# Generated by FakeRAM 2.0
VERSION 5.7 ;
BUSBITCHARS "[]" ;
PROPERTYDEFINITIONS
  MACRO width INTEGER ;
  MACRO depth INTEGER ;
  MACRO banks INTEGER ;
END PROPERTYDEFINITIONS
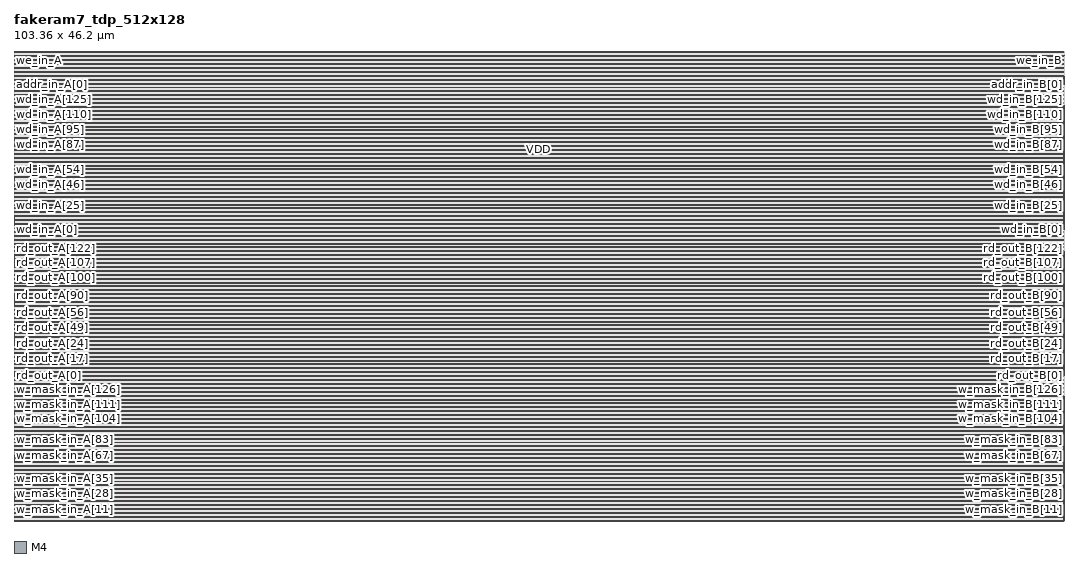
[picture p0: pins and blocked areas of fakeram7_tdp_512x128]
MACRO fakeram7_tdp_512x128
  PROPERTY width 128 ;
  PROPERTY depth 512 ;
  PROPERTY banks 4 ;
  FOREIGN fakeram7_tdp_512x128 0 0 ;
  SYMMETRY X Y ;
  SIZE 103.360 BY 46.200 ;
  CLASS BLOCK ;
  PIN w_mask_in_A[0]
    DIRECTION INPUT ;
    USE SIGNAL ;
    SHAPE ABUTMENT ;
    PORT
      LAYER M4 ;
      RECT 0.000 0.048 0.024 0.072 ;
    END
  END w_mask_in_A[0]
  PIN w_mask_in_B[0]
    DIRECTION INPUT ;
    USE SIGNAL ;
    SHAPE ABUTMENT ;
    PORT
      LAYER M4 ;
      RECT 103.336 0.048 103.360 0.072 ;
    END
  END w_mask_in_B[0]
  PIN w_mask_in_A[1]
    DIRECTION INPUT ;
    USE SIGNAL ;
    SHAPE ABUTMENT ;
    PORT
      LAYER M4 ;
      RECT 0.000 0.144 0.024 0.168 ;
    END
  END w_mask_in_A[1]
  PIN w_mask_in_B[1]
    DIRECTION INPUT ;
    USE SIGNAL ;
    SHAPE ABUTMENT ;
    PORT
      LAYER M4 ;
      RECT 103.336 0.144 103.360 0.168 ;
    END
  END w_mask_in_B[1]
  PIN w_mask_in_A[2]
    DIRECTION INPUT ;
    USE SIGNAL ;
    SHAPE ABUTMENT ;
    PORT
      LAYER M4 ;
      RECT 0.000 0.240 0.024 0.264 ;
    END
  END w_mask_in_A[2]
  PIN w_mask_in_B[2]
    DIRECTION INPUT ;
    USE SIGNAL ;
    SHAPE ABUTMENT ;
    PORT
      LAYER M4 ;
      RECT 103.336 0.240 103.360 0.264 ;
    END
  END w_mask_in_B[2]
  PIN w_mask_in_A[3]
    DIRECTION INPUT ;
    USE SIGNAL ;
    SHAPE ABUTMENT ;
    PORT
      LAYER M4 ;
      RECT 0.000 0.336 0.024 0.360 ;
    END
  END w_mask_in_A[3]
  PIN w_mask_in_B[3]
    DIRECTION INPUT ;
    USE SIGNAL ;
    SHAPE ABUTMENT ;
    PORT
      LAYER M4 ;
      RECT 103.336 0.336 103.360 0.360 ;
    END
  END w_mask_in_B[3]
  PIN w_mask_in_A[4]
    DIRECTION INPUT ;
    USE SIGNAL ;
    SHAPE ABUTMENT ;
    PORT
      LAYER M4 ;
      RECT 0.000 0.432 0.024 0.456 ;
    END
  END w_mask_in_A[4]
  PIN w_mask_in_B[4]
    DIRECTION INPUT ;
    USE SIGNAL ;
    SHAPE ABUTMENT ;
    PORT
      LAYER M4 ;
      RECT 103.336 0.432 103.360 0.456 ;
    END
  END w_mask_in_B[4]
  PIN w_mask_in_A[5]
    DIRECTION INPUT ;
    USE SIGNAL ;
    SHAPE ABUTMENT ;
    PORT
      LAYER M4 ;
      RECT 0.000 0.528 0.024 0.552 ;
    END
  END w_mask_in_A[5]
  PIN w_mask_in_B[5]
    DIRECTION INPUT ;
    USE SIGNAL ;
    SHAPE ABUTMENT ;
    PORT
      LAYER M4 ;
      RECT 103.336 0.528 103.360 0.552 ;
    END
  END w_mask_in_B[5]
  PIN w_mask_in_A[6]
    DIRECTION INPUT ;
    USE SIGNAL ;
    SHAPE ABUTMENT ;
    PORT
      LAYER M4 ;
      RECT 0.000 0.624 0.024 0.648 ;
    END
  END w_mask_in_A[6]
  PIN w_mask_in_B[6]
    DIRECTION INPUT ;
    USE SIGNAL ;
    SHAPE ABUTMENT ;
    PORT
      LAYER M4 ;
      RECT 103.336 0.624 103.360 0.648 ;
    END
  END w_mask_in_B[6]
  PIN w_mask_in_A[7]
    DIRECTION INPUT ;
    USE SIGNAL ;
    SHAPE ABUTMENT ;
    PORT
      LAYER M4 ;
      RECT 0.000 0.720 0.024 0.744 ;
    END
  END w_mask_in_A[7]
  PIN w_mask_in_B[7]
    DIRECTION INPUT ;
    USE SIGNAL ;
    SHAPE ABUTMENT ;
    PORT
      LAYER M4 ;
      RECT 103.336 0.720 103.360 0.744 ;
    END
  END w_mask_in_B[7]
  PIN w_mask_in_A[8]
    DIRECTION INPUT ;
    USE SIGNAL ;
    SHAPE ABUTMENT ;
    PORT
      LAYER M4 ;
      RECT 0.000 0.816 0.024 0.840 ;
    END
  END w_mask_in_A[8]
  PIN w_mask_in_B[8]
    DIRECTION INPUT ;
    USE SIGNAL ;
    SHAPE ABUTMENT ;
    PORT
      LAYER M4 ;
      RECT 103.336 0.816 103.360 0.840 ;
    END
  END w_mask_in_B[8]
  PIN w_mask_in_A[9]
    DIRECTION INPUT ;
    USE SIGNAL ;
    SHAPE ABUTMENT ;
    PORT
      LAYER M4 ;
      RECT 0.000 0.912 0.024 0.936 ;
    END
  END w_mask_in_A[9]
  PIN w_mask_in_B[9]
    DIRECTION INPUT ;
    USE SIGNAL ;
    SHAPE ABUTMENT ;
    PORT
      LAYER M4 ;
      RECT 103.336 0.912 103.360 0.936 ;
    END
  END w_mask_in_B[9]
  PIN w_mask_in_A[10]
    DIRECTION INPUT ;
    USE SIGNAL ;
    SHAPE ABUTMENT ;
    PORT
      LAYER M4 ;
      RECT 0.000 1.008 0.024 1.032 ;
    END
  END w_mask_in_A[10]
  PIN w_mask_in_B[10]
    DIRECTION INPUT ;
    USE SIGNAL ;
    SHAPE ABUTMENT ;
    PORT
      LAYER M4 ;
      RECT 103.336 1.008 103.360 1.032 ;
    END
  END w_mask_in_B[10]
  PIN w_mask_in_A[11]
    DIRECTION INPUT ;
    USE SIGNAL ;
    SHAPE ABUTMENT ;
    PORT
      LAYER M4 ;
      RECT 0.000 1.104 0.024 1.128 ;
    END
  END w_mask_in_A[11]
  PIN w_mask_in_B[11]
    DIRECTION INPUT ;
    USE SIGNAL ;
    SHAPE ABUTMENT ;
    PORT
      LAYER M4 ;
      RECT 103.336 1.104 103.360 1.128 ;
    END
  END w_mask_in_B[11]
  PIN w_mask_in_A[12]
    DIRECTION INPUT ;
    USE SIGNAL ;
    SHAPE ABUTMENT ;
    PORT
      LAYER M4 ;
      RECT 0.000 1.200 0.024 1.224 ;
    END
  END w_mask_in_A[12]
  PIN w_mask_in_B[12]
    DIRECTION INPUT ;
    USE SIGNAL ;
    SHAPE ABUTMENT ;
    PORT
      LAYER M4 ;
      RECT 103.336 1.200 103.360 1.224 ;
    END
  END w_mask_in_B[12]
  PIN w_mask_in_A[13]
    DIRECTION INPUT ;
    USE SIGNAL ;
    SHAPE ABUTMENT ;
    PORT
      LAYER M4 ;
      RECT 0.000 1.296 0.024 1.320 ;
    END
  END w_mask_in_A[13]
  PIN w_mask_in_B[13]
    DIRECTION INPUT ;
    USE SIGNAL ;
    SHAPE ABUTMENT ;
    PORT
      LAYER M4 ;
      RECT 103.336 1.296 103.360 1.320 ;
    END
  END w_mask_in_B[13]
  PIN w_mask_in_A[14]
    DIRECTION INPUT ;
    USE SIGNAL ;
    SHAPE ABUTMENT ;
    PORT
      LAYER M4 ;
      RECT 0.000 1.392 0.024 1.416 ;
    END
  END w_mask_in_A[14]
  PIN w_mask_in_B[14]
    DIRECTION INPUT ;
    USE SIGNAL ;
    SHAPE ABUTMENT ;
    PORT
      LAYER M4 ;
      RECT 103.336 1.392 103.360 1.416 ;
    END
  END w_mask_in_B[14]
  PIN w_mask_in_A[15]
    DIRECTION INPUT ;
    USE SIGNAL ;
    SHAPE ABUTMENT ;
    PORT
      LAYER M4 ;
      RECT 0.000 1.488 0.024 1.512 ;
    END
  END w_mask_in_A[15]
  PIN w_mask_in_B[15]
    DIRECTION INPUT ;
    USE SIGNAL ;
    SHAPE ABUTMENT ;
    PORT
      LAYER M4 ;
      RECT 103.336 1.488 103.360 1.512 ;
    END
  END w_mask_in_B[15]
  PIN w_mask_in_A[16]
    DIRECTION INPUT ;
    USE SIGNAL ;
    SHAPE ABUTMENT ;
    PORT
      LAYER M4 ;
      RECT 0.000 1.584 0.024 1.608 ;
    END
  END w_mask_in_A[16]
  PIN w_mask_in_B[16]
    DIRECTION INPUT ;
    USE SIGNAL ;
    SHAPE ABUTMENT ;
    PORT
      LAYER M4 ;
      RECT 103.336 1.584 103.360 1.608 ;
    END
  END w_mask_in_B[16]
  PIN w_mask_in_A[17]
    DIRECTION INPUT ;
    USE SIGNAL ;
    SHAPE ABUTMENT ;
    PORT
      LAYER M4 ;
      RECT 0.000 1.680 0.024 1.704 ;
    END
  END w_mask_in_A[17]
  PIN w_mask_in_B[17]
    DIRECTION INPUT ;
    USE SIGNAL ;
    SHAPE ABUTMENT ;
    PORT
      LAYER M4 ;
      RECT 103.336 1.680 103.360 1.704 ;
    END
  END w_mask_in_B[17]
  PIN w_mask_in_A[18]
    DIRECTION INPUT ;
    USE SIGNAL ;
    SHAPE ABUTMENT ;
    PORT
      LAYER M4 ;
      RECT 0.000 1.776 0.024 1.800 ;
    END
  END w_mask_in_A[18]
  PIN w_mask_in_B[18]
    DIRECTION INPUT ;
    USE SIGNAL ;
    SHAPE ABUTMENT ;
    PORT
      LAYER M4 ;
      RECT 103.336 1.776 103.360 1.800 ;
    END
  END w_mask_in_B[18]
  PIN w_mask_in_A[19]
    DIRECTION INPUT ;
    USE SIGNAL ;
    SHAPE ABUTMENT ;
    PORT
      LAYER M4 ;
      RECT 0.000 1.872 0.024 1.896 ;
    END
  END w_mask_in_A[19]
  PIN w_mask_in_B[19]
    DIRECTION INPUT ;
    USE SIGNAL ;
    SHAPE ABUTMENT ;
    PORT
      LAYER M4 ;
      RECT 103.336 1.872 103.360 1.896 ;
    END
  END w_mask_in_B[19]
  PIN w_mask_in_A[20]
    DIRECTION INPUT ;
    USE SIGNAL ;
    SHAPE ABUTMENT ;
    PORT
      LAYER M4 ;
      RECT 0.000 1.968 0.024 1.992 ;
    END
  END w_mask_in_A[20]
  PIN w_mask_in_B[20]
    DIRECTION INPUT ;
    USE SIGNAL ;
    SHAPE ABUTMENT ;
    PORT
      LAYER M4 ;
      RECT 103.336 1.968 103.360 1.992 ;
    END
  END w_mask_in_B[20]
  PIN w_mask_in_A[21]
    DIRECTION INPUT ;
    USE SIGNAL ;
    SHAPE ABUTMENT ;
    PORT
      LAYER M4 ;
      RECT 0.000 2.064 0.024 2.088 ;
    END
  END w_mask_in_A[21]
  PIN w_mask_in_B[21]
    DIRECTION INPUT ;
    USE SIGNAL ;
    SHAPE ABUTMENT ;
    PORT
      LAYER M4 ;
      RECT 103.336 2.064 103.360 2.088 ;
    END
  END w_mask_in_B[21]
  PIN w_mask_in_A[22]
    DIRECTION INPUT ;
    USE SIGNAL ;
    SHAPE ABUTMENT ;
    PORT
      LAYER M4 ;
      RECT 0.000 2.160 0.024 2.184 ;
    END
  END w_mask_in_A[22]
  PIN w_mask_in_B[22]
    DIRECTION INPUT ;
    USE SIGNAL ;
    SHAPE ABUTMENT ;
    PORT
      LAYER M4 ;
      RECT 103.336 2.160 103.360 2.184 ;
    END
  END w_mask_in_B[22]
  PIN w_mask_in_A[23]
    DIRECTION INPUT ;
    USE SIGNAL ;
    SHAPE ABUTMENT ;
    PORT
      LAYER M4 ;
      RECT 0.000 2.256 0.024 2.280 ;
    END
  END w_mask_in_A[23]
  PIN w_mask_in_B[23]
    DIRECTION INPUT ;
    USE SIGNAL ;
    SHAPE ABUTMENT ;
    PORT
      LAYER M4 ;
      RECT 103.336 2.256 103.360 2.280 ;
    END
  END w_mask_in_B[23]
  PIN w_mask_in_A[24]
    DIRECTION INPUT ;
    USE SIGNAL ;
    SHAPE ABUTMENT ;
    PORT
      LAYER M4 ;
      RECT 0.000 2.352 0.024 2.376 ;
    END
  END w_mask_in_A[24]
  PIN w_mask_in_B[24]
    DIRECTION INPUT ;
    USE SIGNAL ;
    SHAPE ABUTMENT ;
    PORT
      LAYER M4 ;
      RECT 103.336 2.352 103.360 2.376 ;
    END
  END w_mask_in_B[24]
  PIN w_mask_in_A[25]
    DIRECTION INPUT ;
    USE SIGNAL ;
    SHAPE ABUTMENT ;
    PORT
      LAYER M4 ;
      RECT 0.000 2.448 0.024 2.472 ;
    END
  END w_mask_in_A[25]
  PIN w_mask_in_B[25]
    DIRECTION INPUT ;
    USE SIGNAL ;
    SHAPE ABUTMENT ;
    PORT
      LAYER M4 ;
      RECT 103.336 2.448 103.360 2.472 ;
    END
  END w_mask_in_B[25]
  PIN w_mask_in_A[26]
    DIRECTION INPUT ;
    USE SIGNAL ;
    SHAPE ABUTMENT ;
    PORT
      LAYER M4 ;
      RECT 0.000 2.544 0.024 2.568 ;
    END
  END w_mask_in_A[26]
  PIN w_mask_in_B[26]
    DIRECTION INPUT ;
    USE SIGNAL ;
    SHAPE ABUTMENT ;
    PORT
      LAYER M4 ;
      RECT 103.336 2.544 103.360 2.568 ;
    END
  END w_mask_in_B[26]
  PIN w_mask_in_A[27]
    DIRECTION INPUT ;
    USE SIGNAL ;
    SHAPE ABUTMENT ;
    PORT
      LAYER M4 ;
      RECT 0.000 2.640 0.024 2.664 ;
    END
  END w_mask_in_A[27]
  PIN w_mask_in_B[27]
    DIRECTION INPUT ;
    USE SIGNAL ;
    SHAPE ABUTMENT ;
    PORT
      LAYER M4 ;
      RECT 103.336 2.640 103.360 2.664 ;
    END
  END w_mask_in_B[27]
  PIN w_mask_in_A[28]
    DIRECTION INPUT ;
    USE SIGNAL ;
    SHAPE ABUTMENT ;
    PORT
      LAYER M4 ;
      RECT 0.000 2.736 0.024 2.760 ;
    END
  END w_mask_in_A[28]
  PIN w_mask_in_B[28]
    DIRECTION INPUT ;
    USE SIGNAL ;
    SHAPE ABUTMENT ;
    PORT
      LAYER M4 ;
      RECT 103.336 2.736 103.360 2.760 ;
    END
  END w_mask_in_B[28]
  PIN w_mask_in_A[29]
    DIRECTION INPUT ;
    USE SIGNAL ;
    SHAPE ABUTMENT ;
    PORT
      LAYER M4 ;
      RECT 0.000 2.832 0.024 2.856 ;
    END
  END w_mask_in_A[29]
  PIN w_mask_in_B[29]
    DIRECTION INPUT ;
    USE SIGNAL ;
    SHAPE ABUTMENT ;
    PORT
      LAYER M4 ;
      RECT 103.336 2.832 103.360 2.856 ;
    END
  END w_mask_in_B[29]
  PIN w_mask_in_A[30]
    DIRECTION INPUT ;
    USE SIGNAL ;
    SHAPE ABUTMENT ;
    PORT
      LAYER M4 ;
      RECT 0.000 2.928 0.024 2.952 ;
    END
  END w_mask_in_A[30]
  PIN w_mask_in_B[30]
    DIRECTION INPUT ;
    USE SIGNAL ;
    SHAPE ABUTMENT ;
    PORT
      LAYER M4 ;
      RECT 103.336 2.928 103.360 2.952 ;
    END
  END w_mask_in_B[30]
  PIN w_mask_in_A[31]
    DIRECTION INPUT ;
    USE SIGNAL ;
    SHAPE ABUTMENT ;
    PORT
      LAYER M4 ;
      RECT 0.000 3.024 0.024 3.048 ;
    END
  END w_mask_in_A[31]
  PIN w_mask_in_B[31]
    DIRECTION INPUT ;
    USE SIGNAL ;
    SHAPE ABUTMENT ;
    PORT
      LAYER M4 ;
      RECT 103.336 3.024 103.360 3.048 ;
    END
  END w_mask_in_B[31]
  PIN w_mask_in_A[32]
    DIRECTION INPUT ;
    USE SIGNAL ;
    SHAPE ABUTMENT ;
    PORT
      LAYER M4 ;
      RECT 0.000 3.120 0.024 3.144 ;
    END
  END w_mask_in_A[32]
  PIN w_mask_in_B[32]
    DIRECTION INPUT ;
    USE SIGNAL ;
    SHAPE ABUTMENT ;
    PORT
      LAYER M4 ;
      RECT 103.336 3.120 103.360 3.144 ;
    END
  END w_mask_in_B[32]
  PIN w_mask_in_A[33]
    DIRECTION INPUT ;
    USE SIGNAL ;
    SHAPE ABUTMENT ;
    PORT
      LAYER M4 ;
      RECT 0.000 3.216 0.024 3.240 ;
    END
  END w_mask_in_A[33]
  PIN w_mask_in_B[33]
    DIRECTION INPUT ;
    USE SIGNAL ;
    SHAPE ABUTMENT ;
    PORT
      LAYER M4 ;
      RECT 103.336 3.216 103.360 3.240 ;
    END
  END w_mask_in_B[33]
  PIN w_mask_in_A[34]
    DIRECTION INPUT ;
    USE SIGNAL ;
    SHAPE ABUTMENT ;
    PORT
      LAYER M4 ;
      RECT 0.000 3.312 0.024 3.336 ;
    END
  END w_mask_in_A[34]
  PIN w_mask_in_B[34]
    DIRECTION INPUT ;
    USE SIGNAL ;
    SHAPE ABUTMENT ;
    PORT
      LAYER M4 ;
      RECT 103.336 3.312 103.360 3.336 ;
    END
  END w_mask_in_B[34]
  PIN w_mask_in_A[35]
    DIRECTION INPUT ;
    USE SIGNAL ;
    SHAPE ABUTMENT ;
    PORT
      LAYER M4 ;
      RECT 0.000 3.408 0.024 3.432 ;
    END
  END w_mask_in_A[35]
  PIN w_mask_in_B[35]
    DIRECTION INPUT ;
    USE SIGNAL ;
    SHAPE ABUTMENT ;
    PORT
      LAYER M4 ;
      RECT 103.336 3.408 103.360 3.432 ;
    END
  END w_mask_in_B[35]
  PIN w_mask_in_A[36]
    DIRECTION INPUT ;
    USE SIGNAL ;
    SHAPE ABUTMENT ;
    PORT
      LAYER M4 ;
      RECT 0.000 3.504 0.024 3.528 ;
    END
  END w_mask_in_A[36]
  PIN w_mask_in_B[36]
    DIRECTION INPUT ;
    USE SIGNAL ;
    SHAPE ABUTMENT ;
    PORT
      LAYER M4 ;
      RECT 103.336 3.504 103.360 3.528 ;
    END
  END w_mask_in_B[36]
  PIN w_mask_in_A[37]
    DIRECTION INPUT ;
    USE SIGNAL ;
    SHAPE ABUTMENT ;
    PORT
      LAYER M4 ;
      RECT 0.000 3.600 0.024 3.624 ;
    END
  END w_mask_in_A[37]
  PIN w_mask_in_B[37]
    DIRECTION INPUT ;
    USE SIGNAL ;
    SHAPE ABUTMENT ;
    PORT
      LAYER M4 ;
      RECT 103.336 3.600 103.360 3.624 ;
    END
  END w_mask_in_B[37]
  PIN w_mask_in_A[38]
    DIRECTION INPUT ;
    USE SIGNAL ;
    SHAPE ABUTMENT ;
    PORT
      LAYER M4 ;
      RECT 0.000 3.696 0.024 3.720 ;
    END
  END w_mask_in_A[38]
  PIN w_mask_in_B[38]
    DIRECTION INPUT ;
    USE SIGNAL ;
    SHAPE ABUTMENT ;
    PORT
      LAYER M4 ;
      RECT 103.336 3.696 103.360 3.720 ;
    END
  END w_mask_in_B[38]
  PIN w_mask_in_A[39]
    DIRECTION INPUT ;
    USE SIGNAL ;
    SHAPE ABUTMENT ;
    PORT
      LAYER M4 ;
      RECT 0.000 3.792 0.024 3.816 ;
    END
  END w_mask_in_A[39]
  PIN w_mask_in_B[39]
    DIRECTION INPUT ;
    USE SIGNAL ;
    SHAPE ABUTMENT ;
    PORT
      LAYER M4 ;
      RECT 103.336 3.792 103.360 3.816 ;
    END
  END w_mask_in_B[39]
  PIN w_mask_in_A[40]
    DIRECTION INPUT ;
    USE SIGNAL ;
    SHAPE ABUTMENT ;
    PORT
      LAYER M4 ;
      RECT 0.000 3.888 0.024 3.912 ;
    END
  END w_mask_in_A[40]
  PIN w_mask_in_B[40]
    DIRECTION INPUT ;
    USE SIGNAL ;
    SHAPE ABUTMENT ;
    PORT
      LAYER M4 ;
      RECT 103.336 3.888 103.360 3.912 ;
    END
  END w_mask_in_B[40]
  PIN w_mask_in_A[41]
    DIRECTION INPUT ;
    USE SIGNAL ;
    SHAPE ABUTMENT ;
    PORT
      LAYER M4 ;
      RECT 0.000 3.984 0.024 4.008 ;
    END
  END w_mask_in_A[41]
  PIN w_mask_in_B[41]
    DIRECTION INPUT ;
    USE SIGNAL ;
    SHAPE ABUTMENT ;
    PORT
      LAYER M4 ;
      RECT 103.336 3.984 103.360 4.008 ;
    END
  END w_mask_in_B[41]
  PIN w_mask_in_A[42]
    DIRECTION INPUT ;
    USE SIGNAL ;
    SHAPE ABUTMENT ;
    PORT
      LAYER M4 ;
      RECT 0.000 4.080 0.024 4.104 ;
    END
  END w_mask_in_A[42]
  PIN w_mask_in_B[42]
    DIRECTION INPUT ;
    USE SIGNAL ;
    SHAPE ABUTMENT ;
    PORT
      LAYER M4 ;
      RECT 103.336 4.080 103.360 4.104 ;
    END
  END w_mask_in_B[42]
  PIN w_mask_in_A[43]
    DIRECTION INPUT ;
    USE SIGNAL ;
    SHAPE ABUTMENT ;
    PORT
      LAYER M4 ;
      RECT 0.000 4.176 0.024 4.200 ;
    END
  END w_mask_in_A[43]
  PIN w_mask_in_B[43]
    DIRECTION INPUT ;
    USE SIGNAL ;
    SHAPE ABUTMENT ;
    PORT
      LAYER M4 ;
      RECT 103.336 4.176 103.360 4.200 ;
    END
  END w_mask_in_B[43]
  PIN w_mask_in_A[44]
    DIRECTION INPUT ;
    USE SIGNAL ;
    SHAPE ABUTMENT ;
    PORT
      LAYER M4 ;
      RECT 0.000 4.272 0.024 4.296 ;
    END
  END w_mask_in_A[44]
  PIN w_mask_in_B[44]
    DIRECTION INPUT ;
    USE SIGNAL ;
    SHAPE ABUTMENT ;
    PORT
      LAYER M4 ;
      RECT 103.336 4.272 103.360 4.296 ;
    END
  END w_mask_in_B[44]
  PIN w_mask_in_A[45]
    DIRECTION INPUT ;
    USE SIGNAL ;
    SHAPE ABUTMENT ;
    PORT
      LAYER M4 ;
      RECT 0.000 4.368 0.024 4.392 ;
    END
  END w_mask_in_A[45]
  PIN w_mask_in_B[45]
    DIRECTION INPUT ;
    USE SIGNAL ;
    SHAPE ABUTMENT ;
    PORT
      LAYER M4 ;
      RECT 103.336 4.368 103.360 4.392 ;
    END
  END w_mask_in_B[45]
  PIN w_mask_in_A[46]
    DIRECTION INPUT ;
    USE SIGNAL ;
    SHAPE ABUTMENT ;
    PORT
      LAYER M4 ;
      RECT 0.000 4.464 0.024 4.488 ;
    END
  END w_mask_in_A[46]
  PIN w_mask_in_B[46]
    DIRECTION INPUT ;
    USE SIGNAL ;
    SHAPE ABUTMENT ;
    PORT
      LAYER M4 ;
      RECT 103.336 4.464 103.360 4.488 ;
    END
  END w_mask_in_B[46]
  PIN w_mask_in_A[47]
    DIRECTION INPUT ;
    USE SIGNAL ;
    SHAPE ABUTMENT ;
    PORT
      LAYER M4 ;
      RECT 0.000 4.560 0.024 4.584 ;
    END
  END w_mask_in_A[47]
  PIN w_mask_in_B[47]
    DIRECTION INPUT ;
    USE SIGNAL ;
    SHAPE ABUTMENT ;
    PORT
      LAYER M4 ;
      RECT 103.336 4.560 103.360 4.584 ;
    END
  END w_mask_in_B[47]
  PIN w_mask_in_A[48]
    DIRECTION INPUT ;
    USE SIGNAL ;
    SHAPE ABUTMENT ;
    PORT
      LAYER M4 ;
      RECT 0.000 4.656 0.024 4.680 ;
    END
  END w_mask_in_A[48]
  PIN w_mask_in_B[48]
    DIRECTION INPUT ;
    USE SIGNAL ;
    SHAPE ABUTMENT ;
    PORT
      LAYER M4 ;
      RECT 103.336 4.656 103.360 4.680 ;
    END
  END w_mask_in_B[48]
  PIN w_mask_in_A[49]
    DIRECTION INPUT ;
    USE SIGNAL ;
    SHAPE ABUTMENT ;
    PORT
      LAYER M4 ;
      RECT 0.000 4.752 0.024 4.776 ;
    END
  END w_mask_in_A[49]
  PIN w_mask_in_B[49]
    DIRECTION INPUT ;
    USE SIGNAL ;
    SHAPE ABUTMENT ;
    PORT
      LAYER M4 ;
      RECT 103.336 4.752 103.360 4.776 ;
    END
  END w_mask_in_B[49]
  PIN w_mask_in_A[50]
    DIRECTION INPUT ;
    USE SIGNAL ;
    SHAPE ABUTMENT ;
    PORT
      LAYER M4 ;
      RECT 0.000 4.848 0.024 4.872 ;
    END
  END w_mask_in_A[50]
  PIN w_mask_in_B[50]
    DIRECTION INPUT ;
    USE SIGNAL ;
    SHAPE ABUTMENT ;
    PORT
      LAYER M4 ;
      RECT 103.336 4.848 103.360 4.872 ;
    END
  END w_mask_in_B[50]
  PIN w_mask_in_A[51]
    DIRECTION INPUT ;
    USE SIGNAL ;
    SHAPE ABUTMENT ;
    PORT
      LAYER M4 ;
      RECT 0.000 4.944 0.024 4.968 ;
    END
  END w_mask_in_A[51]
  PIN w_mask_in_B[51]
    DIRECTION INPUT ;
    USE SIGNAL ;
    SHAPE ABUTMENT ;
    PORT
      LAYER M4 ;
      RECT 103.336 4.944 103.360 4.968 ;
    END
  END w_mask_in_B[51]
  PIN w_mask_in_A[52]
    DIRECTION INPUT ;
    USE SIGNAL ;
    SHAPE ABUTMENT ;
    PORT
      LAYER M4 ;
      RECT 0.000 5.040 0.024 5.064 ;
    END
  END w_mask_in_A[52]
  PIN w_mask_in_B[52]
    DIRECTION INPUT ;
    USE SIGNAL ;
    SHAPE ABUTMENT ;
    PORT
      LAYER M4 ;
      RECT 103.336 5.040 103.360 5.064 ;
    END
  END w_mask_in_B[52]
  PIN w_mask_in_A[53]
    DIRECTION INPUT ;
    USE SIGNAL ;
    SHAPE ABUTMENT ;
    PORT
      LAYER M4 ;
      RECT 0.000 5.136 0.024 5.160 ;
    END
  END w_mask_in_A[53]
  PIN w_mask_in_B[53]
    DIRECTION INPUT ;
    USE SIGNAL ;
    SHAPE ABUTMENT ;
    PORT
      LAYER M4 ;
      RECT 103.336 5.136 103.360 5.160 ;
    END
  END w_mask_in_B[53]
  PIN w_mask_in_A[54]
    DIRECTION INPUT ;
    USE SIGNAL ;
    SHAPE ABUTMENT ;
    PORT
      LAYER M4 ;
      RECT 0.000 5.232 0.024 5.256 ;
    END
  END w_mask_in_A[54]
  PIN w_mask_in_B[54]
    DIRECTION INPUT ;
    USE SIGNAL ;
    SHAPE ABUTMENT ;
    PORT
      LAYER M4 ;
      RECT 103.336 5.232 103.360 5.256 ;
    END
  END w_mask_in_B[54]
  PIN w_mask_in_A[55]
    DIRECTION INPUT ;
    USE SIGNAL ;
    SHAPE ABUTMENT ;
    PORT
      LAYER M4 ;
      RECT 0.000 5.328 0.024 5.352 ;
    END
  END w_mask_in_A[55]
  PIN w_mask_in_B[55]
    DIRECTION INPUT ;
    USE SIGNAL ;
    SHAPE ABUTMENT ;
    PORT
      LAYER M4 ;
      RECT 103.336 5.328 103.360 5.352 ;
    END
  END w_mask_in_B[55]
  PIN w_mask_in_A[56]
    DIRECTION INPUT ;
    USE SIGNAL ;
    SHAPE ABUTMENT ;
    PORT
      LAYER M4 ;
      RECT 0.000 5.424 0.024 5.448 ;
    END
  END w_mask_in_A[56]
  PIN w_mask_in_B[56]
    DIRECTION INPUT ;
    USE SIGNAL ;
    SHAPE ABUTMENT ;
    PORT
      LAYER M4 ;
      RECT 103.336 5.424 103.360 5.448 ;
    END
  END w_mask_in_B[56]
  PIN w_mask_in_A[57]
    DIRECTION INPUT ;
    USE SIGNAL ;
    SHAPE ABUTMENT ;
    PORT
      LAYER M4 ;
      RECT 0.000 5.520 0.024 5.544 ;
    END
  END w_mask_in_A[57]
  PIN w_mask_in_B[57]
    DIRECTION INPUT ;
    USE SIGNAL ;
    SHAPE ABUTMENT ;
    PORT
      LAYER M4 ;
      RECT 103.336 5.520 103.360 5.544 ;
    END
  END w_mask_in_B[57]
  PIN w_mask_in_A[58]
    DIRECTION INPUT ;
    USE SIGNAL ;
    SHAPE ABUTMENT ;
    PORT
      LAYER M4 ;
      RECT 0.000 5.616 0.024 5.640 ;
    END
  END w_mask_in_A[58]
  PIN w_mask_in_B[58]
    DIRECTION INPUT ;
    USE SIGNAL ;
    SHAPE ABUTMENT ;
    PORT
      LAYER M4 ;
      RECT 103.336 5.616 103.360 5.640 ;
    END
  END w_mask_in_B[58]
  PIN w_mask_in_A[59]
    DIRECTION INPUT ;
    USE SIGNAL ;
    SHAPE ABUTMENT ;
    PORT
      LAYER M4 ;
      RECT 0.000 5.712 0.024 5.736 ;
    END
  END w_mask_in_A[59]
  PIN w_mask_in_B[59]
    DIRECTION INPUT ;
    USE SIGNAL ;
    SHAPE ABUTMENT ;
    PORT
      LAYER M4 ;
      RECT 103.336 5.712 103.360 5.736 ;
    END
  END w_mask_in_B[59]
  PIN w_mask_in_A[60]
    DIRECTION INPUT ;
    USE SIGNAL ;
    SHAPE ABUTMENT ;
    PORT
      LAYER M4 ;
      RECT 0.000 5.808 0.024 5.832 ;
    END
  END w_mask_in_A[60]
  PIN w_mask_in_B[60]
    DIRECTION INPUT ;
    USE SIGNAL ;
    SHAPE ABUTMENT ;
    PORT
      LAYER M4 ;
      RECT 103.336 5.808 103.360 5.832 ;
    END
  END w_mask_in_B[60]
  PIN w_mask_in_A[61]
    DIRECTION INPUT ;
    USE SIGNAL ;
    SHAPE ABUTMENT ;
    PORT
      LAYER M4 ;
      RECT 0.000 5.904 0.024 5.928 ;
    END
  END w_mask_in_A[61]
  PIN w_mask_in_B[61]
    DIRECTION INPUT ;
    USE SIGNAL ;
    SHAPE ABUTMENT ;
    PORT
      LAYER M4 ;
      RECT 103.336 5.904 103.360 5.928 ;
    END
  END w_mask_in_B[61]
  PIN w_mask_in_A[62]
    DIRECTION INPUT ;
    USE SIGNAL ;
    SHAPE ABUTMENT ;
    PORT
      LAYER M4 ;
      RECT 0.000 6.000 0.024 6.024 ;
    END
  END w_mask_in_A[62]
  PIN w_mask_in_B[62]
    DIRECTION INPUT ;
    USE SIGNAL ;
    SHAPE ABUTMENT ;
    PORT
      LAYER M4 ;
      RECT 103.336 6.000 103.360 6.024 ;
    END
  END w_mask_in_B[62]
  PIN w_mask_in_A[63]
    DIRECTION INPUT ;
    USE SIGNAL ;
    SHAPE ABUTMENT ;
    PORT
      LAYER M4 ;
      RECT 0.000 6.096 0.024 6.120 ;
    END
  END w_mask_in_A[63]
  PIN w_mask_in_B[63]
    DIRECTION INPUT ;
    USE SIGNAL ;
    SHAPE ABUTMENT ;
    PORT
      LAYER M4 ;
      RECT 103.336 6.096 103.360 6.120 ;
    END
  END w_mask_in_B[63]
  PIN w_mask_in_A[64]
    DIRECTION INPUT ;
    USE SIGNAL ;
    SHAPE ABUTMENT ;
    PORT
      LAYER M4 ;
      RECT 0.000 6.192 0.024 6.216 ;
    END
  END w_mask_in_A[64]
  PIN w_mask_in_B[64]
    DIRECTION INPUT ;
    USE SIGNAL ;
    SHAPE ABUTMENT ;
    PORT
      LAYER M4 ;
      RECT 103.336 6.192 103.360 6.216 ;
    END
  END w_mask_in_B[64]
  PIN w_mask_in_A[65]
    DIRECTION INPUT ;
    USE SIGNAL ;
    SHAPE ABUTMENT ;
    PORT
      LAYER M4 ;
      RECT 0.000 6.288 0.024 6.312 ;
    END
  END w_mask_in_A[65]
  PIN w_mask_in_B[65]
    DIRECTION INPUT ;
    USE SIGNAL ;
    SHAPE ABUTMENT ;
    PORT
      LAYER M4 ;
      RECT 103.336 6.288 103.360 6.312 ;
    END
  END w_mask_in_B[65]
  PIN w_mask_in_A[66]
    DIRECTION INPUT ;
    USE SIGNAL ;
    SHAPE ABUTMENT ;
    PORT
      LAYER M4 ;
      RECT 0.000 6.384 0.024 6.408 ;
    END
  END w_mask_in_A[66]
  PIN w_mask_in_B[66]
    DIRECTION INPUT ;
    USE SIGNAL ;
    SHAPE ABUTMENT ;
    PORT
      LAYER M4 ;
      RECT 103.336 6.384 103.360 6.408 ;
    END
  END w_mask_in_B[66]
  PIN w_mask_in_A[67]
    DIRECTION INPUT ;
    USE SIGNAL ;
    SHAPE ABUTMENT ;
    PORT
      LAYER M4 ;
      RECT 0.000 6.480 0.024 6.504 ;
    END
  END w_mask_in_A[67]
  PIN w_mask_in_B[67]
    DIRECTION INPUT ;
    USE SIGNAL ;
    SHAPE ABUTMENT ;
    PORT
      LAYER M4 ;
      RECT 103.336 6.480 103.360 6.504 ;
    END
  END w_mask_in_B[67]
  PIN w_mask_in_A[68]
    DIRECTION INPUT ;
    USE SIGNAL ;
    SHAPE ABUTMENT ;
    PORT
      LAYER M4 ;
      RECT 0.000 6.576 0.024 6.600 ;
    END
  END w_mask_in_A[68]
  PIN w_mask_in_B[68]
    DIRECTION INPUT ;
    USE SIGNAL ;
    SHAPE ABUTMENT ;
    PORT
      LAYER M4 ;
      RECT 103.336 6.576 103.360 6.600 ;
    END
  END w_mask_in_B[68]
  PIN w_mask_in_A[69]
    DIRECTION INPUT ;
    USE SIGNAL ;
    SHAPE ABUTMENT ;
    PORT
      LAYER M4 ;
      RECT 0.000 6.672 0.024 6.696 ;
    END
  END w_mask_in_A[69]
  PIN w_mask_in_B[69]
    DIRECTION INPUT ;
    USE SIGNAL ;
    SHAPE ABUTMENT ;
    PORT
      LAYER M4 ;
      RECT 103.336 6.672 103.360 6.696 ;
    END
  END w_mask_in_B[69]
  PIN w_mask_in_A[70]
    DIRECTION INPUT ;
    USE SIGNAL ;
    SHAPE ABUTMENT ;
    PORT
      LAYER M4 ;
      RECT 0.000 6.768 0.024 6.792 ;
    END
  END w_mask_in_A[70]
  PIN w_mask_in_B[70]
    DIRECTION INPUT ;
    USE SIGNAL ;
    SHAPE ABUTMENT ;
    PORT
      LAYER M4 ;
      RECT 103.336 6.768 103.360 6.792 ;
    END
  END w_mask_in_B[70]
  PIN w_mask_in_A[71]
    DIRECTION INPUT ;
    USE SIGNAL ;
    SHAPE ABUTMENT ;
    PORT
      LAYER M4 ;
      RECT 0.000 6.864 0.024 6.888 ;
    END
  END w_mask_in_A[71]
  PIN w_mask_in_B[71]
    DIRECTION INPUT ;
    USE SIGNAL ;
    SHAPE ABUTMENT ;
    PORT
      LAYER M4 ;
      RECT 103.336 6.864 103.360 6.888 ;
    END
  END w_mask_in_B[71]
  PIN w_mask_in_A[72]
    DIRECTION INPUT ;
    USE SIGNAL ;
    SHAPE ABUTMENT ;
    PORT
      LAYER M4 ;
      RECT 0.000 6.960 0.024 6.984 ;
    END
  END w_mask_in_A[72]
  PIN w_mask_in_B[72]
    DIRECTION INPUT ;
    USE SIGNAL ;
    SHAPE ABUTMENT ;
    PORT
      LAYER M4 ;
      RECT 103.336 6.960 103.360 6.984 ;
    END
  END w_mask_in_B[72]
  PIN w_mask_in_A[73]
    DIRECTION INPUT ;
    USE SIGNAL ;
    SHAPE ABUTMENT ;
    PORT
      LAYER M4 ;
      RECT 0.000 7.056 0.024 7.080 ;
    END
  END w_mask_in_A[73]
  PIN w_mask_in_B[73]
    DIRECTION INPUT ;
    USE SIGNAL ;
    SHAPE ABUTMENT ;
    PORT
      LAYER M4 ;
      RECT 103.336 7.056 103.360 7.080 ;
    END
  END w_mask_in_B[73]
  PIN w_mask_in_A[74]
    DIRECTION INPUT ;
    USE SIGNAL ;
    SHAPE ABUTMENT ;
    PORT
      LAYER M4 ;
      RECT 0.000 7.152 0.024 7.176 ;
    END
  END w_mask_in_A[74]
  PIN w_mask_in_B[74]
    DIRECTION INPUT ;
    USE SIGNAL ;
    SHAPE ABUTMENT ;
    PORT
      LAYER M4 ;
      RECT 103.336 7.152 103.360 7.176 ;
    END
  END w_mask_in_B[74]
  PIN w_mask_in_A[75]
    DIRECTION INPUT ;
    USE SIGNAL ;
    SHAPE ABUTMENT ;
    PORT
      LAYER M4 ;
      RECT 0.000 7.248 0.024 7.272 ;
    END
  END w_mask_in_A[75]
  PIN w_mask_in_B[75]
    DIRECTION INPUT ;
    USE SIGNAL ;
    SHAPE ABUTMENT ;
    PORT
      LAYER M4 ;
      RECT 103.336 7.248 103.360 7.272 ;
    END
  END w_mask_in_B[75]
  PIN w_mask_in_A[76]
    DIRECTION INPUT ;
    USE SIGNAL ;
    SHAPE ABUTMENT ;
    PORT
      LAYER M4 ;
      RECT 0.000 7.344 0.024 7.368 ;
    END
  END w_mask_in_A[76]
  PIN w_mask_in_B[76]
    DIRECTION INPUT ;
    USE SIGNAL ;
    SHAPE ABUTMENT ;
    PORT
      LAYER M4 ;
      RECT 103.336 7.344 103.360 7.368 ;
    END
  END w_mask_in_B[76]
  PIN w_mask_in_A[77]
    DIRECTION INPUT ;
    USE SIGNAL ;
    SHAPE ABUTMENT ;
    PORT
      LAYER M4 ;
      RECT 0.000 7.440 0.024 7.464 ;
    END
  END w_mask_in_A[77]
  PIN w_mask_in_B[77]
    DIRECTION INPUT ;
    USE SIGNAL ;
    SHAPE ABUTMENT ;
    PORT
      LAYER M4 ;
      RECT 103.336 7.440 103.360 7.464 ;
    END
  END w_mask_in_B[77]
  PIN w_mask_in_A[78]
    DIRECTION INPUT ;
    USE SIGNAL ;
    SHAPE ABUTMENT ;
    PORT
      LAYER M4 ;
      RECT 0.000 7.536 0.024 7.560 ;
    END
  END w_mask_in_A[78]
  PIN w_mask_in_B[78]
    DIRECTION INPUT ;
    USE SIGNAL ;
    SHAPE ABUTMENT ;
    PORT
      LAYER M4 ;
      RECT 103.336 7.536 103.360 7.560 ;
    END
  END w_mask_in_B[78]
  PIN w_mask_in_A[79]
    DIRECTION INPUT ;
    USE SIGNAL ;
    SHAPE ABUTMENT ;
    PORT
      LAYER M4 ;
      RECT 0.000 7.632 0.024 7.656 ;
    END
  END w_mask_in_A[79]
  PIN w_mask_in_B[79]
    DIRECTION INPUT ;
    USE SIGNAL ;
    SHAPE ABUTMENT ;
    PORT
      LAYER M4 ;
      RECT 103.336 7.632 103.360 7.656 ;
    END
  END w_mask_in_B[79]
  PIN w_mask_in_A[80]
    DIRECTION INPUT ;
    USE SIGNAL ;
    SHAPE ABUTMENT ;
    PORT
      LAYER M4 ;
      RECT 0.000 7.728 0.024 7.752 ;
    END
  END w_mask_in_A[80]
  PIN w_mask_in_B[80]
    DIRECTION INPUT ;
    USE SIGNAL ;
    SHAPE ABUTMENT ;
    PORT
      LAYER M4 ;
      RECT 103.336 7.728 103.360 7.752 ;
    END
  END w_mask_in_B[80]
  PIN w_mask_in_A[81]
    DIRECTION INPUT ;
    USE SIGNAL ;
    SHAPE ABUTMENT ;
    PORT
      LAYER M4 ;
      RECT 0.000 7.824 0.024 7.848 ;
    END
  END w_mask_in_A[81]
  PIN w_mask_in_B[81]
    DIRECTION INPUT ;
    USE SIGNAL ;
    SHAPE ABUTMENT ;
    PORT
      LAYER M4 ;
      RECT 103.336 7.824 103.360 7.848 ;
    END
  END w_mask_in_B[81]
  PIN w_mask_in_A[82]
    DIRECTION INPUT ;
    USE SIGNAL ;
    SHAPE ABUTMENT ;
    PORT
      LAYER M4 ;
      RECT 0.000 7.920 0.024 7.944 ;
    END
  END w_mask_in_A[82]
  PIN w_mask_in_B[82]
    DIRECTION INPUT ;
    USE SIGNAL ;
    SHAPE ABUTMENT ;
    PORT
      LAYER M4 ;
      RECT 103.336 7.920 103.360 7.944 ;
    END
  END w_mask_in_B[82]
  PIN w_mask_in_A[83]
    DIRECTION INPUT ;
    USE SIGNAL ;
    SHAPE ABUTMENT ;
    PORT
      LAYER M4 ;
      RECT 0.000 8.016 0.024 8.040 ;
    END
  END w_mask_in_A[83]
  PIN w_mask_in_B[83]
    DIRECTION INPUT ;
    USE SIGNAL ;
    SHAPE ABUTMENT ;
    PORT
      LAYER M4 ;
      RECT 103.336 8.016 103.360 8.040 ;
    END
  END w_mask_in_B[83]
  PIN w_mask_in_A[84]
    DIRECTION INPUT ;
    USE SIGNAL ;
    SHAPE ABUTMENT ;
    PORT
      LAYER M4 ;
      RECT 0.000 8.112 0.024 8.136 ;
    END
  END w_mask_in_A[84]
  PIN w_mask_in_B[84]
    DIRECTION INPUT ;
    USE SIGNAL ;
    SHAPE ABUTMENT ;
    PORT
      LAYER M4 ;
      RECT 103.336 8.112 103.360 8.136 ;
    END
  END w_mask_in_B[84]
  PIN w_mask_in_A[85]
    DIRECTION INPUT ;
    USE SIGNAL ;
    SHAPE ABUTMENT ;
    PORT
      LAYER M4 ;
      RECT 0.000 8.208 0.024 8.232 ;
    END
  END w_mask_in_A[85]
  PIN w_mask_in_B[85]
    DIRECTION INPUT ;
    USE SIGNAL ;
    SHAPE ABUTMENT ;
    PORT
      LAYER M4 ;
      RECT 103.336 8.208 103.360 8.232 ;
    END
  END w_mask_in_B[85]
  PIN w_mask_in_A[86]
    DIRECTION INPUT ;
    USE SIGNAL ;
    SHAPE ABUTMENT ;
    PORT
      LAYER M4 ;
      RECT 0.000 8.304 0.024 8.328 ;
    END
  END w_mask_in_A[86]
  PIN w_mask_in_B[86]
    DIRECTION INPUT ;
    USE SIGNAL ;
    SHAPE ABUTMENT ;
    PORT
      LAYER M4 ;
      RECT 103.336 8.304 103.360 8.328 ;
    END
  END w_mask_in_B[86]
  PIN w_mask_in_A[87]
    DIRECTION INPUT ;
    USE SIGNAL ;
    SHAPE ABUTMENT ;
    PORT
      LAYER M4 ;
      RECT 0.000 8.400 0.024 8.424 ;
    END
  END w_mask_in_A[87]
  PIN w_mask_in_B[87]
    DIRECTION INPUT ;
    USE SIGNAL ;
    SHAPE ABUTMENT ;
    PORT
      LAYER M4 ;
      RECT 103.336 8.400 103.360 8.424 ;
    END
  END w_mask_in_B[87]
  PIN w_mask_in_A[88]
    DIRECTION INPUT ;
    USE SIGNAL ;
    SHAPE ABUTMENT ;
    PORT
      LAYER M4 ;
      RECT 0.000 8.496 0.024 8.520 ;
    END
  END w_mask_in_A[88]
  PIN w_mask_in_B[88]
    DIRECTION INPUT ;
    USE SIGNAL ;
    SHAPE ABUTMENT ;
    PORT
      LAYER M4 ;
      RECT 103.336 8.496 103.360 8.520 ;
    END
  END w_mask_in_B[88]
  PIN w_mask_in_A[89]
    DIRECTION INPUT ;
    USE SIGNAL ;
    SHAPE ABUTMENT ;
    PORT
      LAYER M4 ;
      RECT 0.000 8.592 0.024 8.616 ;
    END
  END w_mask_in_A[89]
  PIN w_mask_in_B[89]
    DIRECTION INPUT ;
    USE SIGNAL ;
    SHAPE ABUTMENT ;
    PORT
      LAYER M4 ;
      RECT 103.336 8.592 103.360 8.616 ;
    END
  END w_mask_in_B[89]
  PIN w_mask_in_A[90]
    DIRECTION INPUT ;
    USE SIGNAL ;
    SHAPE ABUTMENT ;
    PORT
      LAYER M4 ;
      RECT 0.000 8.688 0.024 8.712 ;
    END
  END w_mask_in_A[90]
  PIN w_mask_in_B[90]
    DIRECTION INPUT ;
    USE SIGNAL ;
    SHAPE ABUTMENT ;
    PORT
      LAYER M4 ;
      RECT 103.336 8.688 103.360 8.712 ;
    END
  END w_mask_in_B[90]
  PIN w_mask_in_A[91]
    DIRECTION INPUT ;
    USE SIGNAL ;
    SHAPE ABUTMENT ;
    PORT
      LAYER M4 ;
      RECT 0.000 8.784 0.024 8.808 ;
    END
  END w_mask_in_A[91]
  PIN w_mask_in_B[91]
    DIRECTION INPUT ;
    USE SIGNAL ;
    SHAPE ABUTMENT ;
    PORT
      LAYER M4 ;
      RECT 103.336 8.784 103.360 8.808 ;
    END
  END w_mask_in_B[91]
  PIN w_mask_in_A[92]
    DIRECTION INPUT ;
    USE SIGNAL ;
    SHAPE ABUTMENT ;
    PORT
      LAYER M4 ;
      RECT 0.000 8.880 0.024 8.904 ;
    END
  END w_mask_in_A[92]
  PIN w_mask_in_B[92]
    DIRECTION INPUT ;
    USE SIGNAL ;
    SHAPE ABUTMENT ;
    PORT
      LAYER M4 ;
      RECT 103.336 8.880 103.360 8.904 ;
    END
  END w_mask_in_B[92]
  PIN w_mask_in_A[93]
    DIRECTION INPUT ;
    USE SIGNAL ;
    SHAPE ABUTMENT ;
    PORT
      LAYER M4 ;
      RECT 0.000 8.976 0.024 9.000 ;
    END
  END w_mask_in_A[93]
  PIN w_mask_in_B[93]
    DIRECTION INPUT ;
    USE SIGNAL ;
    SHAPE ABUTMENT ;
    PORT
      LAYER M4 ;
      RECT 103.336 8.976 103.360 9.000 ;
    END
  END w_mask_in_B[93]
  PIN w_mask_in_A[94]
    DIRECTION INPUT ;
    USE SIGNAL ;
    SHAPE ABUTMENT ;
    PORT
      LAYER M4 ;
      RECT 0.000 9.072 0.024 9.096 ;
    END
  END w_mask_in_A[94]
  PIN w_mask_in_B[94]
    DIRECTION INPUT ;
    USE SIGNAL ;
    SHAPE ABUTMENT ;
    PORT
      LAYER M4 ;
      RECT 103.336 9.072 103.360 9.096 ;
    END
  END w_mask_in_B[94]
  PIN w_mask_in_A[95]
    DIRECTION INPUT ;
    USE SIGNAL ;
    SHAPE ABUTMENT ;
    PORT
      LAYER M4 ;
      RECT 0.000 9.168 0.024 9.192 ;
    END
  END w_mask_in_A[95]
  PIN w_mask_in_B[95]
    DIRECTION INPUT ;
    USE SIGNAL ;
    SHAPE ABUTMENT ;
    PORT
      LAYER M4 ;
      RECT 103.336 9.168 103.360 9.192 ;
    END
  END w_mask_in_B[95]
  PIN w_mask_in_A[96]
    DIRECTION INPUT ;
    USE SIGNAL ;
    SHAPE ABUTMENT ;
    PORT
      LAYER M4 ;
      RECT 0.000 9.264 0.024 9.288 ;
    END
  END w_mask_in_A[96]
  PIN w_mask_in_B[96]
    DIRECTION INPUT ;
    USE SIGNAL ;
    SHAPE ABUTMENT ;
    PORT
      LAYER M4 ;
      RECT 103.336 9.264 103.360 9.288 ;
    END
  END w_mask_in_B[96]
  PIN w_mask_in_A[97]
    DIRECTION INPUT ;
    USE SIGNAL ;
    SHAPE ABUTMENT ;
    PORT
      LAYER M4 ;
      RECT 0.000 9.360 0.024 9.384 ;
    END
  END w_mask_in_A[97]
  PIN w_mask_in_B[97]
    DIRECTION INPUT ;
    USE SIGNAL ;
    SHAPE ABUTMENT ;
    PORT
      LAYER M4 ;
      RECT 103.336 9.360 103.360 9.384 ;
    END
  END w_mask_in_B[97]
  PIN w_mask_in_A[98]
    DIRECTION INPUT ;
    USE SIGNAL ;
    SHAPE ABUTMENT ;
    PORT
      LAYER M4 ;
      RECT 0.000 9.456 0.024 9.480 ;
    END
  END w_mask_in_A[98]
  PIN w_mask_in_B[98]
    DIRECTION INPUT ;
    USE SIGNAL ;
    SHAPE ABUTMENT ;
    PORT
      LAYER M4 ;
      RECT 103.336 9.456 103.360 9.480 ;
    END
  END w_mask_in_B[98]
  PIN w_mask_in_A[99]
    DIRECTION INPUT ;
    USE SIGNAL ;
    SHAPE ABUTMENT ;
    PORT
      LAYER M4 ;
      RECT 0.000 9.552 0.024 9.576 ;
    END
  END w_mask_in_A[99]
  PIN w_mask_in_B[99]
    DIRECTION INPUT ;
    USE SIGNAL ;
    SHAPE ABUTMENT ;
    PORT
      LAYER M4 ;
      RECT 103.336 9.552 103.360 9.576 ;
    END
  END w_mask_in_B[99]
  PIN w_mask_in_A[100]
    DIRECTION INPUT ;
    USE SIGNAL ;
    SHAPE ABUTMENT ;
    PORT
      LAYER M4 ;
      RECT 0.000 9.648 0.024 9.672 ;
    END
  END w_mask_in_A[100]
  PIN w_mask_in_B[100]
    DIRECTION INPUT ;
    USE SIGNAL ;
    SHAPE ABUTMENT ;
    PORT
      LAYER M4 ;
      RECT 103.336 9.648 103.360 9.672 ;
    END
  END w_mask_in_B[100]
  PIN w_mask_in_A[101]
    DIRECTION INPUT ;
    USE SIGNAL ;
    SHAPE ABUTMENT ;
    PORT
      LAYER M4 ;
      RECT 0.000 9.744 0.024 9.768 ;
    END
  END w_mask_in_A[101]
  PIN w_mask_in_B[101]
    DIRECTION INPUT ;
    USE SIGNAL ;
    SHAPE ABUTMENT ;
    PORT
      LAYER M4 ;
      RECT 103.336 9.744 103.360 9.768 ;
    END
  END w_mask_in_B[101]
  PIN w_mask_in_A[102]
    DIRECTION INPUT ;
    USE SIGNAL ;
    SHAPE ABUTMENT ;
    PORT
      LAYER M4 ;
      RECT 0.000 9.840 0.024 9.864 ;
    END
  END w_mask_in_A[102]
  PIN w_mask_in_B[102]
    DIRECTION INPUT ;
    USE SIGNAL ;
    SHAPE ABUTMENT ;
    PORT
      LAYER M4 ;
      RECT 103.336 9.840 103.360 9.864 ;
    END
  END w_mask_in_B[102]
  PIN w_mask_in_A[103]
    DIRECTION INPUT ;
    USE SIGNAL ;
    SHAPE ABUTMENT ;
    PORT
      LAYER M4 ;
      RECT 0.000 9.936 0.024 9.960 ;
    END
  END w_mask_in_A[103]
  PIN w_mask_in_B[103]
    DIRECTION INPUT ;
    USE SIGNAL ;
    SHAPE ABUTMENT ;
    PORT
      LAYER M4 ;
      RECT 103.336 9.936 103.360 9.960 ;
    END
  END w_mask_in_B[103]
  PIN w_mask_in_A[104]
    DIRECTION INPUT ;
    USE SIGNAL ;
    SHAPE ABUTMENT ;
    PORT
      LAYER M4 ;
      RECT 0.000 10.032 0.024 10.056 ;
    END
  END w_mask_in_A[104]
  PIN w_mask_in_B[104]
    DIRECTION INPUT ;
    USE SIGNAL ;
    SHAPE ABUTMENT ;
    PORT
      LAYER M4 ;
      RECT 103.336 10.032 103.360 10.056 ;
    END
  END w_mask_in_B[104]
  PIN w_mask_in_A[105]
    DIRECTION INPUT ;
    USE SIGNAL ;
    SHAPE ABUTMENT ;
    PORT
      LAYER M4 ;
      RECT 0.000 10.128 0.024 10.152 ;
    END
  END w_mask_in_A[105]
  PIN w_mask_in_B[105]
    DIRECTION INPUT ;
    USE SIGNAL ;
    SHAPE ABUTMENT ;
    PORT
      LAYER M4 ;
      RECT 103.336 10.128 103.360 10.152 ;
    END
  END w_mask_in_B[105]
  PIN w_mask_in_A[106]
    DIRECTION INPUT ;
    USE SIGNAL ;
    SHAPE ABUTMENT ;
    PORT
      LAYER M4 ;
      RECT 0.000 10.224 0.024 10.248 ;
    END
  END w_mask_in_A[106]
  PIN w_mask_in_B[106]
    DIRECTION INPUT ;
    USE SIGNAL ;
    SHAPE ABUTMENT ;
    PORT
      LAYER M4 ;
      RECT 103.336 10.224 103.360 10.248 ;
    END
  END w_mask_in_B[106]
  PIN w_mask_in_A[107]
    DIRECTION INPUT ;
    USE SIGNAL ;
    SHAPE ABUTMENT ;
    PORT
      LAYER M4 ;
      RECT 0.000 10.320 0.024 10.344 ;
    END
  END w_mask_in_A[107]
  PIN w_mask_in_B[107]
    DIRECTION INPUT ;
    USE SIGNAL ;
    SHAPE ABUTMENT ;
    PORT
      LAYER M4 ;
      RECT 103.336 10.320 103.360 10.344 ;
    END
  END w_mask_in_B[107]
  PIN w_mask_in_A[108]
    DIRECTION INPUT ;
    USE SIGNAL ;
    SHAPE ABUTMENT ;
    PORT
      LAYER M4 ;
      RECT 0.000 10.416 0.024 10.440 ;
    END
  END w_mask_in_A[108]
  PIN w_mask_in_B[108]
    DIRECTION INPUT ;
    USE SIGNAL ;
    SHAPE ABUTMENT ;
    PORT
      LAYER M4 ;
      RECT 103.336 10.416 103.360 10.440 ;
    END
  END w_mask_in_B[108]
  PIN w_mask_in_A[109]
    DIRECTION INPUT ;
    USE SIGNAL ;
    SHAPE ABUTMENT ;
    PORT
      LAYER M4 ;
      RECT 0.000 10.512 0.024 10.536 ;
    END
  END w_mask_in_A[109]
  PIN w_mask_in_B[109]
    DIRECTION INPUT ;
    USE SIGNAL ;
    SHAPE ABUTMENT ;
    PORT
      LAYER M4 ;
      RECT 103.336 10.512 103.360 10.536 ;
    END
  END w_mask_in_B[109]
  PIN w_mask_in_A[110]
    DIRECTION INPUT ;
    USE SIGNAL ;
    SHAPE ABUTMENT ;
    PORT
      LAYER M4 ;
      RECT 0.000 10.608 0.024 10.632 ;
    END
  END w_mask_in_A[110]
  PIN w_mask_in_B[110]
    DIRECTION INPUT ;
    USE SIGNAL ;
    SHAPE ABUTMENT ;
    PORT
      LAYER M4 ;
      RECT 103.336 10.608 103.360 10.632 ;
    END
  END w_mask_in_B[110]
  PIN w_mask_in_A[111]
    DIRECTION INPUT ;
    USE SIGNAL ;
    SHAPE ABUTMENT ;
    PORT
      LAYER M4 ;
      RECT 0.000 10.704 0.024 10.728 ;
    END
  END w_mask_in_A[111]
  PIN w_mask_in_B[111]
    DIRECTION INPUT ;
    USE SIGNAL ;
    SHAPE ABUTMENT ;
    PORT
      LAYER M4 ;
      RECT 103.336 10.704 103.360 10.728 ;
    END
  END w_mask_in_B[111]
  PIN w_mask_in_A[112]
    DIRECTION INPUT ;
    USE SIGNAL ;
    SHAPE ABUTMENT ;
    PORT
      LAYER M4 ;
      RECT 0.000 10.800 0.024 10.824 ;
    END
  END w_mask_in_A[112]
  PIN w_mask_in_B[112]
    DIRECTION INPUT ;
    USE SIGNAL ;
    SHAPE ABUTMENT ;
    PORT
      LAYER M4 ;
      RECT 103.336 10.800 103.360 10.824 ;
    END
  END w_mask_in_B[112]
  PIN w_mask_in_A[113]
    DIRECTION INPUT ;
    USE SIGNAL ;
    SHAPE ABUTMENT ;
    PORT
      LAYER M4 ;
      RECT 0.000 10.896 0.024 10.920 ;
    END
  END w_mask_in_A[113]
  PIN w_mask_in_B[113]
    DIRECTION INPUT ;
    USE SIGNAL ;
    SHAPE ABUTMENT ;
    PORT
      LAYER M4 ;
      RECT 103.336 10.896 103.360 10.920 ;
    END
  END w_mask_in_B[113]
  PIN w_mask_in_A[114]
    DIRECTION INPUT ;
    USE SIGNAL ;
    SHAPE ABUTMENT ;
    PORT
      LAYER M4 ;
      RECT 0.000 10.992 0.024 11.016 ;
    END
  END w_mask_in_A[114]
  PIN w_mask_in_B[114]
    DIRECTION INPUT ;
    USE SIGNAL ;
    SHAPE ABUTMENT ;
    PORT
      LAYER M4 ;
      RECT 103.336 10.992 103.360 11.016 ;
    END
  END w_mask_in_B[114]
  PIN w_mask_in_A[115]
    DIRECTION INPUT ;
    USE SIGNAL ;
    SHAPE ABUTMENT ;
    PORT
      LAYER M4 ;
      RECT 0.000 11.088 0.024 11.112 ;
    END
  END w_mask_in_A[115]
  PIN w_mask_in_B[115]
    DIRECTION INPUT ;
    USE SIGNAL ;
    SHAPE ABUTMENT ;
    PORT
      LAYER M4 ;
      RECT 103.336 11.088 103.360 11.112 ;
    END
  END w_mask_in_B[115]
  PIN w_mask_in_A[116]
    DIRECTION INPUT ;
    USE SIGNAL ;
    SHAPE ABUTMENT ;
    PORT
      LAYER M4 ;
      RECT 0.000 11.184 0.024 11.208 ;
    END
  END w_mask_in_A[116]
  PIN w_mask_in_B[116]
    DIRECTION INPUT ;
    USE SIGNAL ;
    SHAPE ABUTMENT ;
    PORT
      LAYER M4 ;
      RECT 103.336 11.184 103.360 11.208 ;
    END
  END w_mask_in_B[116]
  PIN w_mask_in_A[117]
    DIRECTION INPUT ;
    USE SIGNAL ;
    SHAPE ABUTMENT ;
    PORT
      LAYER M4 ;
      RECT 0.000 11.280 0.024 11.304 ;
    END
  END w_mask_in_A[117]
  PIN w_mask_in_B[117]
    DIRECTION INPUT ;
    USE SIGNAL ;
    SHAPE ABUTMENT ;
    PORT
      LAYER M4 ;
      RECT 103.336 11.280 103.360 11.304 ;
    END
  END w_mask_in_B[117]
  PIN w_mask_in_A[118]
    DIRECTION INPUT ;
    USE SIGNAL ;
    SHAPE ABUTMENT ;
    PORT
      LAYER M4 ;
      RECT 0.000 11.376 0.024 11.400 ;
    END
  END w_mask_in_A[118]
  PIN w_mask_in_B[118]
    DIRECTION INPUT ;
    USE SIGNAL ;
    SHAPE ABUTMENT ;
    PORT
      LAYER M4 ;
      RECT 103.336 11.376 103.360 11.400 ;
    END
  END w_mask_in_B[118]
  PIN w_mask_in_A[119]
    DIRECTION INPUT ;
    USE SIGNAL ;
    SHAPE ABUTMENT ;
    PORT
      LAYER M4 ;
      RECT 0.000 11.472 0.024 11.496 ;
    END
  END w_mask_in_A[119]
  PIN w_mask_in_B[119]
    DIRECTION INPUT ;
    USE SIGNAL ;
    SHAPE ABUTMENT ;
    PORT
      LAYER M4 ;
      RECT 103.336 11.472 103.360 11.496 ;
    END
  END w_mask_in_B[119]
  PIN w_mask_in_A[120]
    DIRECTION INPUT ;
    USE SIGNAL ;
    SHAPE ABUTMENT ;
    PORT
      LAYER M4 ;
      RECT 0.000 11.568 0.024 11.592 ;
    END
  END w_mask_in_A[120]
  PIN w_mask_in_B[120]
    DIRECTION INPUT ;
    USE SIGNAL ;
    SHAPE ABUTMENT ;
    PORT
      LAYER M4 ;
      RECT 103.336 11.568 103.360 11.592 ;
    END
  END w_mask_in_B[120]
  PIN w_mask_in_A[121]
    DIRECTION INPUT ;
    USE SIGNAL ;
    SHAPE ABUTMENT ;
    PORT
      LAYER M4 ;
      RECT 0.000 11.664 0.024 11.688 ;
    END
  END w_mask_in_A[121]
  PIN w_mask_in_B[121]
    DIRECTION INPUT ;
    USE SIGNAL ;
    SHAPE ABUTMENT ;
    PORT
      LAYER M4 ;
      RECT 103.336 11.664 103.360 11.688 ;
    END
  END w_mask_in_B[121]
  PIN w_mask_in_A[122]
    DIRECTION INPUT ;
    USE SIGNAL ;
    SHAPE ABUTMENT ;
    PORT
      LAYER M4 ;
      RECT 0.000 11.760 0.024 11.784 ;
    END
  END w_mask_in_A[122]
  PIN w_mask_in_B[122]
    DIRECTION INPUT ;
    USE SIGNAL ;
    SHAPE ABUTMENT ;
    PORT
      LAYER M4 ;
      RECT 103.336 11.760 103.360 11.784 ;
    END
  END w_mask_in_B[122]
  PIN w_mask_in_A[123]
    DIRECTION INPUT ;
    USE SIGNAL ;
    SHAPE ABUTMENT ;
    PORT
      LAYER M4 ;
      RECT 0.000 11.856 0.024 11.880 ;
    END
  END w_mask_in_A[123]
  PIN w_mask_in_B[123]
    DIRECTION INPUT ;
    USE SIGNAL ;
    SHAPE ABUTMENT ;
    PORT
      LAYER M4 ;
      RECT 103.336 11.856 103.360 11.880 ;
    END
  END w_mask_in_B[123]
  PIN w_mask_in_A[124]
    DIRECTION INPUT ;
    USE SIGNAL ;
    SHAPE ABUTMENT ;
    PORT
      LAYER M4 ;
      RECT 0.000 11.952 0.024 11.976 ;
    END
  END w_mask_in_A[124]
  PIN w_mask_in_B[124]
    DIRECTION INPUT ;
    USE SIGNAL ;
    SHAPE ABUTMENT ;
    PORT
      LAYER M4 ;
      RECT 103.336 11.952 103.360 11.976 ;
    END
  END w_mask_in_B[124]
  PIN w_mask_in_A[125]
    DIRECTION INPUT ;
    USE SIGNAL ;
    SHAPE ABUTMENT ;
    PORT
      LAYER M4 ;
      RECT 0.000 12.048 0.024 12.072 ;
    END
  END w_mask_in_A[125]
  PIN w_mask_in_B[125]
    DIRECTION INPUT ;
    USE SIGNAL ;
    SHAPE ABUTMENT ;
    PORT
      LAYER M4 ;
      RECT 103.336 12.048 103.360 12.072 ;
    END
  END w_mask_in_B[125]
  PIN w_mask_in_A[126]
    DIRECTION INPUT ;
    USE SIGNAL ;
    SHAPE ABUTMENT ;
    PORT
      LAYER M4 ;
      RECT 0.000 12.144 0.024 12.168 ;
    END
  END w_mask_in_A[126]
  PIN w_mask_in_B[126]
    DIRECTION INPUT ;
    USE SIGNAL ;
    SHAPE ABUTMENT ;
    PORT
      LAYER M4 ;
      RECT 103.336 12.144 103.360 12.168 ;
    END
  END w_mask_in_B[126]
  PIN w_mask_in_A[127]
    DIRECTION INPUT ;
    USE SIGNAL ;
    SHAPE ABUTMENT ;
    PORT
      LAYER M4 ;
      RECT 0.000 12.240 0.024 12.264 ;
    END
  END w_mask_in_A[127]
  PIN w_mask_in_B[127]
    DIRECTION INPUT ;
    USE SIGNAL ;
    SHAPE ABUTMENT ;
    PORT
      LAYER M4 ;
      RECT 103.336 12.240 103.360 12.264 ;
    END
  END w_mask_in_B[127]
  PIN rd_out_A[0]
    DIRECTION OUTPUT ;
    USE SIGNAL ;
    SHAPE ABUTMENT ;
    PORT
      LAYER M4 ;
      RECT 0.000 14.352 0.024 14.376 ;
    END
  END rd_out_A[0]
  PIN rd_out_B[0]
    DIRECTION OUTPUT ;
    USE SIGNAL ;
    SHAPE ABUTMENT ;
    PORT
      LAYER M4 ;
      RECT 103.336 14.352 103.360 14.376 ;
    END
  END rd_out_B[0]
  PIN rd_out_A[1]
    DIRECTION OUTPUT ;
    USE SIGNAL ;
    SHAPE ABUTMENT ;
    PORT
      LAYER M4 ;
      RECT 0.000 14.448 0.024 14.472 ;
    END
  END rd_out_A[1]
  PIN rd_out_B[1]
    DIRECTION OUTPUT ;
    USE SIGNAL ;
    SHAPE ABUTMENT ;
    PORT
      LAYER M4 ;
      RECT 103.336 14.448 103.360 14.472 ;
    END
  END rd_out_B[1]
  PIN rd_out_A[2]
    DIRECTION OUTPUT ;
    USE SIGNAL ;
    SHAPE ABUTMENT ;
    PORT
      LAYER M4 ;
      RECT 0.000 14.544 0.024 14.568 ;
    END
  END rd_out_A[2]
  PIN rd_out_B[2]
    DIRECTION OUTPUT ;
    USE SIGNAL ;
    SHAPE ABUTMENT ;
    PORT
      LAYER M4 ;
      RECT 103.336 14.544 103.360 14.568 ;
    END
  END rd_out_B[2]
  PIN rd_out_A[3]
    DIRECTION OUTPUT ;
    USE SIGNAL ;
    SHAPE ABUTMENT ;
    PORT
      LAYER M4 ;
      RECT 0.000 14.640 0.024 14.664 ;
    END
  END rd_out_A[3]
  PIN rd_out_B[3]
    DIRECTION OUTPUT ;
    USE SIGNAL ;
    SHAPE ABUTMENT ;
    PORT
      LAYER M4 ;
      RECT 103.336 14.640 103.360 14.664 ;
    END
  END rd_out_B[3]
  PIN rd_out_A[4]
    DIRECTION OUTPUT ;
    USE SIGNAL ;
    SHAPE ABUTMENT ;
    PORT
      LAYER M4 ;
      RECT 0.000 14.736 0.024 14.760 ;
    END
  END rd_out_A[4]
  PIN rd_out_B[4]
    DIRECTION OUTPUT ;
    USE SIGNAL ;
    SHAPE ABUTMENT ;
    PORT
      LAYER M4 ;
      RECT 103.336 14.736 103.360 14.760 ;
    END
  END rd_out_B[4]
  PIN rd_out_A[5]
    DIRECTION OUTPUT ;
    USE SIGNAL ;
    SHAPE ABUTMENT ;
    PORT
      LAYER M4 ;
      RECT 0.000 14.832 0.024 14.856 ;
    END
  END rd_out_A[5]
  PIN rd_out_B[5]
    DIRECTION OUTPUT ;
    USE SIGNAL ;
    SHAPE ABUTMENT ;
    PORT
      LAYER M4 ;
      RECT 103.336 14.832 103.360 14.856 ;
    END
  END rd_out_B[5]
  PIN rd_out_A[6]
    DIRECTION OUTPUT ;
    USE SIGNAL ;
    SHAPE ABUTMENT ;
    PORT
      LAYER M4 ;
      RECT 0.000 14.928 0.024 14.952 ;
    END
  END rd_out_A[6]
  PIN rd_out_B[6]
    DIRECTION OUTPUT ;
    USE SIGNAL ;
    SHAPE ABUTMENT ;
    PORT
      LAYER M4 ;
      RECT 103.336 14.928 103.360 14.952 ;
    END
  END rd_out_B[6]
  PIN rd_out_A[7]
    DIRECTION OUTPUT ;
    USE SIGNAL ;
    SHAPE ABUTMENT ;
    PORT
      LAYER M4 ;
      RECT 0.000 15.024 0.024 15.048 ;
    END
  END rd_out_A[7]
  PIN rd_out_B[7]
    DIRECTION OUTPUT ;
    USE SIGNAL ;
    SHAPE ABUTMENT ;
    PORT
      LAYER M4 ;
      RECT 103.336 15.024 103.360 15.048 ;
    END
  END rd_out_B[7]
  PIN rd_out_A[8]
    DIRECTION OUTPUT ;
    USE SIGNAL ;
    SHAPE ABUTMENT ;
    PORT
      LAYER M4 ;
      RECT 0.000 15.120 0.024 15.144 ;
    END
  END rd_out_A[8]
  PIN rd_out_B[8]
    DIRECTION OUTPUT ;
    USE SIGNAL ;
    SHAPE ABUTMENT ;
    PORT
      LAYER M4 ;
      RECT 103.336 15.120 103.360 15.144 ;
    END
  END rd_out_B[8]
  PIN rd_out_A[9]
    DIRECTION OUTPUT ;
    USE SIGNAL ;
    SHAPE ABUTMENT ;
    PORT
      LAYER M4 ;
      RECT 0.000 15.216 0.024 15.240 ;
    END
  END rd_out_A[9]
  PIN rd_out_B[9]
    DIRECTION OUTPUT ;
    USE SIGNAL ;
    SHAPE ABUTMENT ;
    PORT
      LAYER M4 ;
      RECT 103.336 15.216 103.360 15.240 ;
    END
  END rd_out_B[9]
  PIN rd_out_A[10]
    DIRECTION OUTPUT ;
    USE SIGNAL ;
    SHAPE ABUTMENT ;
    PORT
      LAYER M4 ;
      RECT 0.000 15.312 0.024 15.336 ;
    END
  END rd_out_A[10]
  PIN rd_out_B[10]
    DIRECTION OUTPUT ;
    USE SIGNAL ;
    SHAPE ABUTMENT ;
    PORT
      LAYER M4 ;
      RECT 103.336 15.312 103.360 15.336 ;
    END
  END rd_out_B[10]
  PIN rd_out_A[11]
    DIRECTION OUTPUT ;
    USE SIGNAL ;
    SHAPE ABUTMENT ;
    PORT
      LAYER M4 ;
      RECT 0.000 15.408 0.024 15.432 ;
    END
  END rd_out_A[11]
  PIN rd_out_B[11]
    DIRECTION OUTPUT ;
    USE SIGNAL ;
    SHAPE ABUTMENT ;
    PORT
      LAYER M4 ;
      RECT 103.336 15.408 103.360 15.432 ;
    END
  END rd_out_B[11]
  PIN rd_out_A[12]
    DIRECTION OUTPUT ;
    USE SIGNAL ;
    SHAPE ABUTMENT ;
    PORT
      LAYER M4 ;
      RECT 0.000 15.504 0.024 15.528 ;
    END
  END rd_out_A[12]
  PIN rd_out_B[12]
    DIRECTION OUTPUT ;
    USE SIGNAL ;
    SHAPE ABUTMENT ;
    PORT
      LAYER M4 ;
      RECT 103.336 15.504 103.360 15.528 ;
    END
  END rd_out_B[12]
  PIN rd_out_A[13]
    DIRECTION OUTPUT ;
    USE SIGNAL ;
    SHAPE ABUTMENT ;
    PORT
      LAYER M4 ;
      RECT 0.000 15.600 0.024 15.624 ;
    END
  END rd_out_A[13]
  PIN rd_out_B[13]
    DIRECTION OUTPUT ;
    USE SIGNAL ;
    SHAPE ABUTMENT ;
    PORT
      LAYER M4 ;
      RECT 103.336 15.600 103.360 15.624 ;
    END
  END rd_out_B[13]
  PIN rd_out_A[14]
    DIRECTION OUTPUT ;
    USE SIGNAL ;
    SHAPE ABUTMENT ;
    PORT
      LAYER M4 ;
      RECT 0.000 15.696 0.024 15.720 ;
    END
  END rd_out_A[14]
  PIN rd_out_B[14]
    DIRECTION OUTPUT ;
    USE SIGNAL ;
    SHAPE ABUTMENT ;
    PORT
      LAYER M4 ;
      RECT 103.336 15.696 103.360 15.720 ;
    END
  END rd_out_B[14]
  PIN rd_out_A[15]
    DIRECTION OUTPUT ;
    USE SIGNAL ;
    SHAPE ABUTMENT ;
    PORT
      LAYER M4 ;
      RECT 0.000 15.792 0.024 15.816 ;
    END
  END rd_out_A[15]
  PIN rd_out_B[15]
    DIRECTION OUTPUT ;
    USE SIGNAL ;
    SHAPE ABUTMENT ;
    PORT
      LAYER M4 ;
      RECT 103.336 15.792 103.360 15.816 ;
    END
  END rd_out_B[15]
  PIN rd_out_A[16]
    DIRECTION OUTPUT ;
    USE SIGNAL ;
    SHAPE ABUTMENT ;
    PORT
      LAYER M4 ;
      RECT 0.000 15.888 0.024 15.912 ;
    END
  END rd_out_A[16]
  PIN rd_out_B[16]
    DIRECTION OUTPUT ;
    USE SIGNAL ;
    SHAPE ABUTMENT ;
    PORT
      LAYER M4 ;
      RECT 103.336 15.888 103.360 15.912 ;
    END
  END rd_out_B[16]
  PIN rd_out_A[17]
    DIRECTION OUTPUT ;
    USE SIGNAL ;
    SHAPE ABUTMENT ;
    PORT
      LAYER M4 ;
      RECT 0.000 15.984 0.024 16.008 ;
    END
  END rd_out_A[17]
  PIN rd_out_B[17]
    DIRECTION OUTPUT ;
    USE SIGNAL ;
    SHAPE ABUTMENT ;
    PORT
      LAYER M4 ;
      RECT 103.336 15.984 103.360 16.008 ;
    END
  END rd_out_B[17]
  PIN rd_out_A[18]
    DIRECTION OUTPUT ;
    USE SIGNAL ;
    SHAPE ABUTMENT ;
    PORT
      LAYER M4 ;
      RECT 0.000 16.080 0.024 16.104 ;
    END
  END rd_out_A[18]
  PIN rd_out_B[18]
    DIRECTION OUTPUT ;
    USE SIGNAL ;
    SHAPE ABUTMENT ;
    PORT
      LAYER M4 ;
      RECT 103.336 16.080 103.360 16.104 ;
    END
  END rd_out_B[18]
  PIN rd_out_A[19]
    DIRECTION OUTPUT ;
    USE SIGNAL ;
    SHAPE ABUTMENT ;
    PORT
      LAYER M4 ;
      RECT 0.000 16.176 0.024 16.200 ;
    END
  END rd_out_A[19]
  PIN rd_out_B[19]
    DIRECTION OUTPUT ;
    USE SIGNAL ;
    SHAPE ABUTMENT ;
    PORT
      LAYER M4 ;
      RECT 103.336 16.176 103.360 16.200 ;
    END
  END rd_out_B[19]
  PIN rd_out_A[20]
    DIRECTION OUTPUT ;
    USE SIGNAL ;
    SHAPE ABUTMENT ;
    PORT
      LAYER M4 ;
      RECT 0.000 16.272 0.024 16.296 ;
    END
  END rd_out_A[20]
  PIN rd_out_B[20]
    DIRECTION OUTPUT ;
    USE SIGNAL ;
    SHAPE ABUTMENT ;
    PORT
      LAYER M4 ;
      RECT 103.336 16.272 103.360 16.296 ;
    END
  END rd_out_B[20]
  PIN rd_out_A[21]
    DIRECTION OUTPUT ;
    USE SIGNAL ;
    SHAPE ABUTMENT ;
    PORT
      LAYER M4 ;
      RECT 0.000 16.368 0.024 16.392 ;
    END
  END rd_out_A[21]
  PIN rd_out_B[21]
    DIRECTION OUTPUT ;
    USE SIGNAL ;
    SHAPE ABUTMENT ;
    PORT
      LAYER M4 ;
      RECT 103.336 16.368 103.360 16.392 ;
    END
  END rd_out_B[21]
  PIN rd_out_A[22]
    DIRECTION OUTPUT ;
    USE SIGNAL ;
    SHAPE ABUTMENT ;
    PORT
      LAYER M4 ;
      RECT 0.000 16.464 0.024 16.488 ;
    END
  END rd_out_A[22]
  PIN rd_out_B[22]
    DIRECTION OUTPUT ;
    USE SIGNAL ;
    SHAPE ABUTMENT ;
    PORT
      LAYER M4 ;
      RECT 103.336 16.464 103.360 16.488 ;
    END
  END rd_out_B[22]
  PIN rd_out_A[23]
    DIRECTION OUTPUT ;
    USE SIGNAL ;
    SHAPE ABUTMENT ;
    PORT
      LAYER M4 ;
      RECT 0.000 16.560 0.024 16.584 ;
    END
  END rd_out_A[23]
  PIN rd_out_B[23]
    DIRECTION OUTPUT ;
    USE SIGNAL ;
    SHAPE ABUTMENT ;
    PORT
      LAYER M4 ;
      RECT 103.336 16.560 103.360 16.584 ;
    END
  END rd_out_B[23]
  PIN rd_out_A[24]
    DIRECTION OUTPUT ;
    USE SIGNAL ;
    SHAPE ABUTMENT ;
    PORT
      LAYER M4 ;
      RECT 0.000 16.656 0.024 16.680 ;
    END
  END rd_out_A[24]
  PIN rd_out_B[24]
    DIRECTION OUTPUT ;
    USE SIGNAL ;
    SHAPE ABUTMENT ;
    PORT
      LAYER M4 ;
      RECT 103.336 16.656 103.360 16.680 ;
    END
  END rd_out_B[24]
  PIN rd_out_A[25]
    DIRECTION OUTPUT ;
    USE SIGNAL ;
    SHAPE ABUTMENT ;
    PORT
      LAYER M4 ;
      RECT 0.000 16.752 0.024 16.776 ;
    END
  END rd_out_A[25]
  PIN rd_out_B[25]
    DIRECTION OUTPUT ;
    USE SIGNAL ;
    SHAPE ABUTMENT ;
    PORT
      LAYER M4 ;
      RECT 103.336 16.752 103.360 16.776 ;
    END
  END rd_out_B[25]
  PIN rd_out_A[26]
    DIRECTION OUTPUT ;
    USE SIGNAL ;
    SHAPE ABUTMENT ;
    PORT
      LAYER M4 ;
      RECT 0.000 16.848 0.024 16.872 ;
    END
  END rd_out_A[26]
  PIN rd_out_B[26]
    DIRECTION OUTPUT ;
    USE SIGNAL ;
    SHAPE ABUTMENT ;
    PORT
      LAYER M4 ;
      RECT 103.336 16.848 103.360 16.872 ;
    END
  END rd_out_B[26]
  PIN rd_out_A[27]
    DIRECTION OUTPUT ;
    USE SIGNAL ;
    SHAPE ABUTMENT ;
    PORT
      LAYER M4 ;
      RECT 0.000 16.944 0.024 16.968 ;
    END
  END rd_out_A[27]
  PIN rd_out_B[27]
    DIRECTION OUTPUT ;
    USE SIGNAL ;
    SHAPE ABUTMENT ;
    PORT
      LAYER M4 ;
      RECT 103.336 16.944 103.360 16.968 ;
    END
  END rd_out_B[27]
  PIN rd_out_A[28]
    DIRECTION OUTPUT ;
    USE SIGNAL ;
    SHAPE ABUTMENT ;
    PORT
      LAYER M4 ;
      RECT 0.000 17.040 0.024 17.064 ;
    END
  END rd_out_A[28]
  PIN rd_out_B[28]
    DIRECTION OUTPUT ;
    USE SIGNAL ;
    SHAPE ABUTMENT ;
    PORT
      LAYER M4 ;
      RECT 103.336 17.040 103.360 17.064 ;
    END
  END rd_out_B[28]
  PIN rd_out_A[29]
    DIRECTION OUTPUT ;
    USE SIGNAL ;
    SHAPE ABUTMENT ;
    PORT
      LAYER M4 ;
      RECT 0.000 17.136 0.024 17.160 ;
    END
  END rd_out_A[29]
  PIN rd_out_B[29]
    DIRECTION OUTPUT ;
    USE SIGNAL ;
    SHAPE ABUTMENT ;
    PORT
      LAYER M4 ;
      RECT 103.336 17.136 103.360 17.160 ;
    END
  END rd_out_B[29]
  PIN rd_out_A[30]
    DIRECTION OUTPUT ;
    USE SIGNAL ;
    SHAPE ABUTMENT ;
    PORT
      LAYER M4 ;
      RECT 0.000 17.232 0.024 17.256 ;
    END
  END rd_out_A[30]
  PIN rd_out_B[30]
    DIRECTION OUTPUT ;
    USE SIGNAL ;
    SHAPE ABUTMENT ;
    PORT
      LAYER M4 ;
      RECT 103.336 17.232 103.360 17.256 ;
    END
  END rd_out_B[30]
  PIN rd_out_A[31]
    DIRECTION OUTPUT ;
    USE SIGNAL ;
    SHAPE ABUTMENT ;
    PORT
      LAYER M4 ;
      RECT 0.000 17.328 0.024 17.352 ;
    END
  END rd_out_A[31]
  PIN rd_out_B[31]
    DIRECTION OUTPUT ;
    USE SIGNAL ;
    SHAPE ABUTMENT ;
    PORT
      LAYER M4 ;
      RECT 103.336 17.328 103.360 17.352 ;
    END
  END rd_out_B[31]
  PIN rd_out_A[32]
    DIRECTION OUTPUT ;
    USE SIGNAL ;
    SHAPE ABUTMENT ;
    PORT
      LAYER M4 ;
      RECT 0.000 17.424 0.024 17.448 ;
    END
  END rd_out_A[32]
  PIN rd_out_B[32]
    DIRECTION OUTPUT ;
    USE SIGNAL ;
    SHAPE ABUTMENT ;
    PORT
      LAYER M4 ;
      RECT 103.336 17.424 103.360 17.448 ;
    END
  END rd_out_B[32]
  PIN rd_out_A[33]
    DIRECTION OUTPUT ;
    USE SIGNAL ;
    SHAPE ABUTMENT ;
    PORT
      LAYER M4 ;
      RECT 0.000 17.520 0.024 17.544 ;
    END
  END rd_out_A[33]
  PIN rd_out_B[33]
    DIRECTION OUTPUT ;
    USE SIGNAL ;
    SHAPE ABUTMENT ;
    PORT
      LAYER M4 ;
      RECT 103.336 17.520 103.360 17.544 ;
    END
  END rd_out_B[33]
  PIN rd_out_A[34]
    DIRECTION OUTPUT ;
    USE SIGNAL ;
    SHAPE ABUTMENT ;
    PORT
      LAYER M4 ;
      RECT 0.000 17.616 0.024 17.640 ;
    END
  END rd_out_A[34]
  PIN rd_out_B[34]
    DIRECTION OUTPUT ;
    USE SIGNAL ;
    SHAPE ABUTMENT ;
    PORT
      LAYER M4 ;
      RECT 103.336 17.616 103.360 17.640 ;
    END
  END rd_out_B[34]
  PIN rd_out_A[35]
    DIRECTION OUTPUT ;
    USE SIGNAL ;
    SHAPE ABUTMENT ;
    PORT
      LAYER M4 ;
      RECT 0.000 17.712 0.024 17.736 ;
    END
  END rd_out_A[35]
  PIN rd_out_B[35]
    DIRECTION OUTPUT ;
    USE SIGNAL ;
    SHAPE ABUTMENT ;
    PORT
      LAYER M4 ;
      RECT 103.336 17.712 103.360 17.736 ;
    END
  END rd_out_B[35]
  PIN rd_out_A[36]
    DIRECTION OUTPUT ;
    USE SIGNAL ;
    SHAPE ABUTMENT ;
    PORT
      LAYER M4 ;
      RECT 0.000 17.808 0.024 17.832 ;
    END
  END rd_out_A[36]
  PIN rd_out_B[36]
    DIRECTION OUTPUT ;
    USE SIGNAL ;
    SHAPE ABUTMENT ;
    PORT
      LAYER M4 ;
      RECT 103.336 17.808 103.360 17.832 ;
    END
  END rd_out_B[36]
  PIN rd_out_A[37]
    DIRECTION OUTPUT ;
    USE SIGNAL ;
    SHAPE ABUTMENT ;
    PORT
      LAYER M4 ;
      RECT 0.000 17.904 0.024 17.928 ;
    END
  END rd_out_A[37]
  PIN rd_out_B[37]
    DIRECTION OUTPUT ;
    USE SIGNAL ;
    SHAPE ABUTMENT ;
    PORT
      LAYER M4 ;
      RECT 103.336 17.904 103.360 17.928 ;
    END
  END rd_out_B[37]
  PIN rd_out_A[38]
    DIRECTION OUTPUT ;
    USE SIGNAL ;
    SHAPE ABUTMENT ;
    PORT
      LAYER M4 ;
      RECT 0.000 18.000 0.024 18.024 ;
    END
  END rd_out_A[38]
  PIN rd_out_B[38]
    DIRECTION OUTPUT ;
    USE SIGNAL ;
    SHAPE ABUTMENT ;
    PORT
      LAYER M4 ;
      RECT 103.336 18.000 103.360 18.024 ;
    END
  END rd_out_B[38]
  PIN rd_out_A[39]
    DIRECTION OUTPUT ;
    USE SIGNAL ;
    SHAPE ABUTMENT ;
    PORT
      LAYER M4 ;
      RECT 0.000 18.096 0.024 18.120 ;
    END
  END rd_out_A[39]
  PIN rd_out_B[39]
    DIRECTION OUTPUT ;
    USE SIGNAL ;
    SHAPE ABUTMENT ;
    PORT
      LAYER M4 ;
      RECT 103.336 18.096 103.360 18.120 ;
    END
  END rd_out_B[39]
  PIN rd_out_A[40]
    DIRECTION OUTPUT ;
    USE SIGNAL ;
    SHAPE ABUTMENT ;
    PORT
      LAYER M4 ;
      RECT 0.000 18.192 0.024 18.216 ;
    END
  END rd_out_A[40]
  PIN rd_out_B[40]
    DIRECTION OUTPUT ;
    USE SIGNAL ;
    SHAPE ABUTMENT ;
    PORT
      LAYER M4 ;
      RECT 103.336 18.192 103.360 18.216 ;
    END
  END rd_out_B[40]
  PIN rd_out_A[41]
    DIRECTION OUTPUT ;
    USE SIGNAL ;
    SHAPE ABUTMENT ;
    PORT
      LAYER M4 ;
      RECT 0.000 18.288 0.024 18.312 ;
    END
  END rd_out_A[41]
  PIN rd_out_B[41]
    DIRECTION OUTPUT ;
    USE SIGNAL ;
    SHAPE ABUTMENT ;
    PORT
      LAYER M4 ;
      RECT 103.336 18.288 103.360 18.312 ;
    END
  END rd_out_B[41]
  PIN rd_out_A[42]
    DIRECTION OUTPUT ;
    USE SIGNAL ;
    SHAPE ABUTMENT ;
    PORT
      LAYER M4 ;
      RECT 0.000 18.384 0.024 18.408 ;
    END
  END rd_out_A[42]
  PIN rd_out_B[42]
    DIRECTION OUTPUT ;
    USE SIGNAL ;
    SHAPE ABUTMENT ;
    PORT
      LAYER M4 ;
      RECT 103.336 18.384 103.360 18.408 ;
    END
  END rd_out_B[42]
  PIN rd_out_A[43]
    DIRECTION OUTPUT ;
    USE SIGNAL ;
    SHAPE ABUTMENT ;
    PORT
      LAYER M4 ;
      RECT 0.000 18.480 0.024 18.504 ;
    END
  END rd_out_A[43]
  PIN rd_out_B[43]
    DIRECTION OUTPUT ;
    USE SIGNAL ;
    SHAPE ABUTMENT ;
    PORT
      LAYER M4 ;
      RECT 103.336 18.480 103.360 18.504 ;
    END
  END rd_out_B[43]
  PIN rd_out_A[44]
    DIRECTION OUTPUT ;
    USE SIGNAL ;
    SHAPE ABUTMENT ;
    PORT
      LAYER M4 ;
      RECT 0.000 18.576 0.024 18.600 ;
    END
  END rd_out_A[44]
  PIN rd_out_B[44]
    DIRECTION OUTPUT ;
    USE SIGNAL ;
    SHAPE ABUTMENT ;
    PORT
      LAYER M4 ;
      RECT 103.336 18.576 103.360 18.600 ;
    END
  END rd_out_B[44]
  PIN rd_out_A[45]
    DIRECTION OUTPUT ;
    USE SIGNAL ;
    SHAPE ABUTMENT ;
    PORT
      LAYER M4 ;
      RECT 0.000 18.672 0.024 18.696 ;
    END
  END rd_out_A[45]
  PIN rd_out_B[45]
    DIRECTION OUTPUT ;
    USE SIGNAL ;
    SHAPE ABUTMENT ;
    PORT
      LAYER M4 ;
      RECT 103.336 18.672 103.360 18.696 ;
    END
  END rd_out_B[45]
  PIN rd_out_A[46]
    DIRECTION OUTPUT ;
    USE SIGNAL ;
    SHAPE ABUTMENT ;
    PORT
      LAYER M4 ;
      RECT 0.000 18.768 0.024 18.792 ;
    END
  END rd_out_A[46]
  PIN rd_out_B[46]
    DIRECTION OUTPUT ;
    USE SIGNAL ;
    SHAPE ABUTMENT ;
    PORT
      LAYER M4 ;
      RECT 103.336 18.768 103.360 18.792 ;
    END
  END rd_out_B[46]
  PIN rd_out_A[47]
    DIRECTION OUTPUT ;
    USE SIGNAL ;
    SHAPE ABUTMENT ;
    PORT
      LAYER M4 ;
      RECT 0.000 18.864 0.024 18.888 ;
    END
  END rd_out_A[47]
  PIN rd_out_B[47]
    DIRECTION OUTPUT ;
    USE SIGNAL ;
    SHAPE ABUTMENT ;
    PORT
      LAYER M4 ;
      RECT 103.336 18.864 103.360 18.888 ;
    END
  END rd_out_B[47]
  PIN rd_out_A[48]
    DIRECTION OUTPUT ;
    USE SIGNAL ;
    SHAPE ABUTMENT ;
    PORT
      LAYER M4 ;
      RECT 0.000 18.960 0.024 18.984 ;
    END
  END rd_out_A[48]
  PIN rd_out_B[48]
    DIRECTION OUTPUT ;
    USE SIGNAL ;
    SHAPE ABUTMENT ;
    PORT
      LAYER M4 ;
      RECT 103.336 18.960 103.360 18.984 ;
    END
  END rd_out_B[48]
  PIN rd_out_A[49]
    DIRECTION OUTPUT ;
    USE SIGNAL ;
    SHAPE ABUTMENT ;
    PORT
      LAYER M4 ;
      RECT 0.000 19.056 0.024 19.080 ;
    END
  END rd_out_A[49]
  PIN rd_out_B[49]
    DIRECTION OUTPUT ;
    USE SIGNAL ;
    SHAPE ABUTMENT ;
    PORT
      LAYER M4 ;
      RECT 103.336 19.056 103.360 19.080 ;
    END
  END rd_out_B[49]
  PIN rd_out_A[50]
    DIRECTION OUTPUT ;
    USE SIGNAL ;
    SHAPE ABUTMENT ;
    PORT
      LAYER M4 ;
      RECT 0.000 19.152 0.024 19.176 ;
    END
  END rd_out_A[50]
  PIN rd_out_B[50]
    DIRECTION OUTPUT ;
    USE SIGNAL ;
    SHAPE ABUTMENT ;
    PORT
      LAYER M4 ;
      RECT 103.336 19.152 103.360 19.176 ;
    END
  END rd_out_B[50]
  PIN rd_out_A[51]
    DIRECTION OUTPUT ;
    USE SIGNAL ;
    SHAPE ABUTMENT ;
    PORT
      LAYER M4 ;
      RECT 0.000 19.248 0.024 19.272 ;
    END
  END rd_out_A[51]
  PIN rd_out_B[51]
    DIRECTION OUTPUT ;
    USE SIGNAL ;
    SHAPE ABUTMENT ;
    PORT
      LAYER M4 ;
      RECT 103.336 19.248 103.360 19.272 ;
    END
  END rd_out_B[51]
  PIN rd_out_A[52]
    DIRECTION OUTPUT ;
    USE SIGNAL ;
    SHAPE ABUTMENT ;
    PORT
      LAYER M4 ;
      RECT 0.000 19.344 0.024 19.368 ;
    END
  END rd_out_A[52]
  PIN rd_out_B[52]
    DIRECTION OUTPUT ;
    USE SIGNAL ;
    SHAPE ABUTMENT ;
    PORT
      LAYER M4 ;
      RECT 103.336 19.344 103.360 19.368 ;
    END
  END rd_out_B[52]
  PIN rd_out_A[53]
    DIRECTION OUTPUT ;
    USE SIGNAL ;
    SHAPE ABUTMENT ;
    PORT
      LAYER M4 ;
      RECT 0.000 19.440 0.024 19.464 ;
    END
  END rd_out_A[53]
  PIN rd_out_B[53]
    DIRECTION OUTPUT ;
    USE SIGNAL ;
    SHAPE ABUTMENT ;
    PORT
      LAYER M4 ;
      RECT 103.336 19.440 103.360 19.464 ;
    END
  END rd_out_B[53]
  PIN rd_out_A[54]
    DIRECTION OUTPUT ;
    USE SIGNAL ;
    SHAPE ABUTMENT ;
    PORT
      LAYER M4 ;
      RECT 0.000 19.536 0.024 19.560 ;
    END
  END rd_out_A[54]
  PIN rd_out_B[54]
    DIRECTION OUTPUT ;
    USE SIGNAL ;
    SHAPE ABUTMENT ;
    PORT
      LAYER M4 ;
      RECT 103.336 19.536 103.360 19.560 ;
    END
  END rd_out_B[54]
  PIN rd_out_A[55]
    DIRECTION OUTPUT ;
    USE SIGNAL ;
    SHAPE ABUTMENT ;
    PORT
      LAYER M4 ;
      RECT 0.000 19.632 0.024 19.656 ;
    END
  END rd_out_A[55]
  PIN rd_out_B[55]
    DIRECTION OUTPUT ;
    USE SIGNAL ;
    SHAPE ABUTMENT ;
    PORT
      LAYER M4 ;
      RECT 103.336 19.632 103.360 19.656 ;
    END
  END rd_out_B[55]
  PIN rd_out_A[56]
    DIRECTION OUTPUT ;
    USE SIGNAL ;
    SHAPE ABUTMENT ;
    PORT
      LAYER M4 ;
      RECT 0.000 19.728 0.024 19.752 ;
    END
  END rd_out_A[56]
  PIN rd_out_B[56]
    DIRECTION OUTPUT ;
    USE SIGNAL ;
    SHAPE ABUTMENT ;
    PORT
      LAYER M4 ;
      RECT 103.336 19.728 103.360 19.752 ;
    END
  END rd_out_B[56]
  PIN rd_out_A[57]
    DIRECTION OUTPUT ;
    USE SIGNAL ;
    SHAPE ABUTMENT ;
    PORT
      LAYER M4 ;
      RECT 0.000 19.824 0.024 19.848 ;
    END
  END rd_out_A[57]
  PIN rd_out_B[57]
    DIRECTION OUTPUT ;
    USE SIGNAL ;
    SHAPE ABUTMENT ;
    PORT
      LAYER M4 ;
      RECT 103.336 19.824 103.360 19.848 ;
    END
  END rd_out_B[57]
  PIN rd_out_A[58]
    DIRECTION OUTPUT ;
    USE SIGNAL ;
    SHAPE ABUTMENT ;
    PORT
      LAYER M4 ;
      RECT 0.000 19.920 0.024 19.944 ;
    END
  END rd_out_A[58]
  PIN rd_out_B[58]
    DIRECTION OUTPUT ;
    USE SIGNAL ;
    SHAPE ABUTMENT ;
    PORT
      LAYER M4 ;
      RECT 103.336 19.920 103.360 19.944 ;
    END
  END rd_out_B[58]
  PIN rd_out_A[59]
    DIRECTION OUTPUT ;
    USE SIGNAL ;
    SHAPE ABUTMENT ;
    PORT
      LAYER M4 ;
      RECT 0.000 20.016 0.024 20.040 ;
    END
  END rd_out_A[59]
  PIN rd_out_B[59]
    DIRECTION OUTPUT ;
    USE SIGNAL ;
    SHAPE ABUTMENT ;
    PORT
      LAYER M4 ;
      RECT 103.336 20.016 103.360 20.040 ;
    END
  END rd_out_B[59]
  PIN rd_out_A[60]
    DIRECTION OUTPUT ;
    USE SIGNAL ;
    SHAPE ABUTMENT ;
    PORT
      LAYER M4 ;
      RECT 0.000 20.112 0.024 20.136 ;
    END
  END rd_out_A[60]
  PIN rd_out_B[60]
    DIRECTION OUTPUT ;
    USE SIGNAL ;
    SHAPE ABUTMENT ;
    PORT
      LAYER M4 ;
      RECT 103.336 20.112 103.360 20.136 ;
    END
  END rd_out_B[60]
  PIN rd_out_A[61]
    DIRECTION OUTPUT ;
    USE SIGNAL ;
    SHAPE ABUTMENT ;
    PORT
      LAYER M4 ;
      RECT 0.000 20.208 0.024 20.232 ;
    END
  END rd_out_A[61]
  PIN rd_out_B[61]
    DIRECTION OUTPUT ;
    USE SIGNAL ;
    SHAPE ABUTMENT ;
    PORT
      LAYER M4 ;
      RECT 103.336 20.208 103.360 20.232 ;
    END
  END rd_out_B[61]
  PIN rd_out_A[62]
    DIRECTION OUTPUT ;
    USE SIGNAL ;
    SHAPE ABUTMENT ;
    PORT
      LAYER M4 ;
      RECT 0.000 20.304 0.024 20.328 ;
    END
  END rd_out_A[62]
  PIN rd_out_B[62]
    DIRECTION OUTPUT ;
    USE SIGNAL ;
    SHAPE ABUTMENT ;
    PORT
      LAYER M4 ;
      RECT 103.336 20.304 103.360 20.328 ;
    END
  END rd_out_B[62]
  PIN rd_out_A[63]
    DIRECTION OUTPUT ;
    USE SIGNAL ;
    SHAPE ABUTMENT ;
    PORT
      LAYER M4 ;
      RECT 0.000 20.400 0.024 20.424 ;
    END
  END rd_out_A[63]
  PIN rd_out_B[63]
    DIRECTION OUTPUT ;
    USE SIGNAL ;
    SHAPE ABUTMENT ;
    PORT
      LAYER M4 ;
      RECT 103.336 20.400 103.360 20.424 ;
    END
  END rd_out_B[63]
  PIN rd_out_A[64]
    DIRECTION OUTPUT ;
    USE SIGNAL ;
    SHAPE ABUTMENT ;
    PORT
      LAYER M4 ;
      RECT 0.000 20.496 0.024 20.520 ;
    END
  END rd_out_A[64]
  PIN rd_out_B[64]
    DIRECTION OUTPUT ;
    USE SIGNAL ;
    SHAPE ABUTMENT ;
    PORT
      LAYER M4 ;
      RECT 103.336 20.496 103.360 20.520 ;
    END
  END rd_out_B[64]
  PIN rd_out_A[65]
    DIRECTION OUTPUT ;
    USE SIGNAL ;
    SHAPE ABUTMENT ;
    PORT
      LAYER M4 ;
      RECT 0.000 20.592 0.024 20.616 ;
    END
  END rd_out_A[65]
  PIN rd_out_B[65]
    DIRECTION OUTPUT ;
    USE SIGNAL ;
    SHAPE ABUTMENT ;
    PORT
      LAYER M4 ;
      RECT 103.336 20.592 103.360 20.616 ;
    END
  END rd_out_B[65]
  PIN rd_out_A[66]
    DIRECTION OUTPUT ;
    USE SIGNAL ;
    SHAPE ABUTMENT ;
    PORT
      LAYER M4 ;
      RECT 0.000 20.688 0.024 20.712 ;
    END
  END rd_out_A[66]
  PIN rd_out_B[66]
    DIRECTION OUTPUT ;
    USE SIGNAL ;
    SHAPE ABUTMENT ;
    PORT
      LAYER M4 ;
      RECT 103.336 20.688 103.360 20.712 ;
    END
  END rd_out_B[66]
  PIN rd_out_A[67]
    DIRECTION OUTPUT ;
    USE SIGNAL ;
    SHAPE ABUTMENT ;
    PORT
      LAYER M4 ;
      RECT 0.000 20.784 0.024 20.808 ;
    END
  END rd_out_A[67]
  PIN rd_out_B[67]
    DIRECTION OUTPUT ;
    USE SIGNAL ;
    SHAPE ABUTMENT ;
    PORT
      LAYER M4 ;
      RECT 103.336 20.784 103.360 20.808 ;
    END
  END rd_out_B[67]
  PIN rd_out_A[68]
    DIRECTION OUTPUT ;
    USE SIGNAL ;
    SHAPE ABUTMENT ;
    PORT
      LAYER M4 ;
      RECT 0.000 20.880 0.024 20.904 ;
    END
  END rd_out_A[68]
  PIN rd_out_B[68]
    DIRECTION OUTPUT ;
    USE SIGNAL ;
    SHAPE ABUTMENT ;
    PORT
      LAYER M4 ;
      RECT 103.336 20.880 103.360 20.904 ;
    END
  END rd_out_B[68]
  PIN rd_out_A[69]
    DIRECTION OUTPUT ;
    USE SIGNAL ;
    SHAPE ABUTMENT ;
    PORT
      LAYER M4 ;
      RECT 0.000 20.976 0.024 21.000 ;
    END
  END rd_out_A[69]
  PIN rd_out_B[69]
    DIRECTION OUTPUT ;
    USE SIGNAL ;
    SHAPE ABUTMENT ;
    PORT
      LAYER M4 ;
      RECT 103.336 20.976 103.360 21.000 ;
    END
  END rd_out_B[69]
  PIN rd_out_A[70]
    DIRECTION OUTPUT ;
    USE SIGNAL ;
    SHAPE ABUTMENT ;
    PORT
      LAYER M4 ;
      RECT 0.000 21.072 0.024 21.096 ;
    END
  END rd_out_A[70]
  PIN rd_out_B[70]
    DIRECTION OUTPUT ;
    USE SIGNAL ;
    SHAPE ABUTMENT ;
    PORT
      LAYER M4 ;
      RECT 103.336 21.072 103.360 21.096 ;
    END
  END rd_out_B[70]
  PIN rd_out_A[71]
    DIRECTION OUTPUT ;
    USE SIGNAL ;
    SHAPE ABUTMENT ;
    PORT
      LAYER M4 ;
      RECT 0.000 21.168 0.024 21.192 ;
    END
  END rd_out_A[71]
  PIN rd_out_B[71]
    DIRECTION OUTPUT ;
    USE SIGNAL ;
    SHAPE ABUTMENT ;
    PORT
      LAYER M4 ;
      RECT 103.336 21.168 103.360 21.192 ;
    END
  END rd_out_B[71]
  PIN rd_out_A[72]
    DIRECTION OUTPUT ;
    USE SIGNAL ;
    SHAPE ABUTMENT ;
    PORT
      LAYER M4 ;
      RECT 0.000 21.264 0.024 21.288 ;
    END
  END rd_out_A[72]
  PIN rd_out_B[72]
    DIRECTION OUTPUT ;
    USE SIGNAL ;
    SHAPE ABUTMENT ;
    PORT
      LAYER M4 ;
      RECT 103.336 21.264 103.360 21.288 ;
    END
  END rd_out_B[72]
  PIN rd_out_A[73]
    DIRECTION OUTPUT ;
    USE SIGNAL ;
    SHAPE ABUTMENT ;
    PORT
      LAYER M4 ;
      RECT 0.000 21.360 0.024 21.384 ;
    END
  END rd_out_A[73]
  PIN rd_out_B[73]
    DIRECTION OUTPUT ;
    USE SIGNAL ;
    SHAPE ABUTMENT ;
    PORT
      LAYER M4 ;
      RECT 103.336 21.360 103.360 21.384 ;
    END
  END rd_out_B[73]
  PIN rd_out_A[74]
    DIRECTION OUTPUT ;
    USE SIGNAL ;
    SHAPE ABUTMENT ;
    PORT
      LAYER M4 ;
      RECT 0.000 21.456 0.024 21.480 ;
    END
  END rd_out_A[74]
  PIN rd_out_B[74]
    DIRECTION OUTPUT ;
    USE SIGNAL ;
    SHAPE ABUTMENT ;
    PORT
      LAYER M4 ;
      RECT 103.336 21.456 103.360 21.480 ;
    END
  END rd_out_B[74]
  PIN rd_out_A[75]
    DIRECTION OUTPUT ;
    USE SIGNAL ;
    SHAPE ABUTMENT ;
    PORT
      LAYER M4 ;
      RECT 0.000 21.552 0.024 21.576 ;
    END
  END rd_out_A[75]
  PIN rd_out_B[75]
    DIRECTION OUTPUT ;
    USE SIGNAL ;
    SHAPE ABUTMENT ;
    PORT
      LAYER M4 ;
      RECT 103.336 21.552 103.360 21.576 ;
    END
  END rd_out_B[75]
  PIN rd_out_A[76]
    DIRECTION OUTPUT ;
    USE SIGNAL ;
    SHAPE ABUTMENT ;
    PORT
      LAYER M4 ;
      RECT 0.000 21.648 0.024 21.672 ;
    END
  END rd_out_A[76]
  PIN rd_out_B[76]
    DIRECTION OUTPUT ;
    USE SIGNAL ;
    SHAPE ABUTMENT ;
    PORT
      LAYER M4 ;
      RECT 103.336 21.648 103.360 21.672 ;
    END
  END rd_out_B[76]
  PIN rd_out_A[77]
    DIRECTION OUTPUT ;
    USE SIGNAL ;
    SHAPE ABUTMENT ;
    PORT
      LAYER M4 ;
      RECT 0.000 21.744 0.024 21.768 ;
    END
  END rd_out_A[77]
  PIN rd_out_B[77]
    DIRECTION OUTPUT ;
    USE SIGNAL ;
    SHAPE ABUTMENT ;
    PORT
      LAYER M4 ;
      RECT 103.336 21.744 103.360 21.768 ;
    END
  END rd_out_B[77]
  PIN rd_out_A[78]
    DIRECTION OUTPUT ;
    USE SIGNAL ;
    SHAPE ABUTMENT ;
    PORT
      LAYER M4 ;
      RECT 0.000 21.840 0.024 21.864 ;
    END
  END rd_out_A[78]
  PIN rd_out_B[78]
    DIRECTION OUTPUT ;
    USE SIGNAL ;
    SHAPE ABUTMENT ;
    PORT
      LAYER M4 ;
      RECT 103.336 21.840 103.360 21.864 ;
    END
  END rd_out_B[78]
  PIN rd_out_A[79]
    DIRECTION OUTPUT ;
    USE SIGNAL ;
    SHAPE ABUTMENT ;
    PORT
      LAYER M4 ;
      RECT 0.000 21.936 0.024 21.960 ;
    END
  END rd_out_A[79]
  PIN rd_out_B[79]
    DIRECTION OUTPUT ;
    USE SIGNAL ;
    SHAPE ABUTMENT ;
    PORT
      LAYER M4 ;
      RECT 103.336 21.936 103.360 21.960 ;
    END
  END rd_out_B[79]
  PIN rd_out_A[80]
    DIRECTION OUTPUT ;
    USE SIGNAL ;
    SHAPE ABUTMENT ;
    PORT
      LAYER M4 ;
      RECT 0.000 22.032 0.024 22.056 ;
    END
  END rd_out_A[80]
  PIN rd_out_B[80]
    DIRECTION OUTPUT ;
    USE SIGNAL ;
    SHAPE ABUTMENT ;
    PORT
      LAYER M4 ;
      RECT 103.336 22.032 103.360 22.056 ;
    END
  END rd_out_B[80]
  PIN rd_out_A[81]
    DIRECTION OUTPUT ;
    USE SIGNAL ;
    SHAPE ABUTMENT ;
    PORT
      LAYER M4 ;
      RECT 0.000 22.128 0.024 22.152 ;
    END
  END rd_out_A[81]
  PIN rd_out_B[81]
    DIRECTION OUTPUT ;
    USE SIGNAL ;
    SHAPE ABUTMENT ;
    PORT
      LAYER M4 ;
      RECT 103.336 22.128 103.360 22.152 ;
    END
  END rd_out_B[81]
  PIN rd_out_A[82]
    DIRECTION OUTPUT ;
    USE SIGNAL ;
    SHAPE ABUTMENT ;
    PORT
      LAYER M4 ;
      RECT 0.000 22.224 0.024 22.248 ;
    END
  END rd_out_A[82]
  PIN rd_out_B[82]
    DIRECTION OUTPUT ;
    USE SIGNAL ;
    SHAPE ABUTMENT ;
    PORT
      LAYER M4 ;
      RECT 103.336 22.224 103.360 22.248 ;
    END
  END rd_out_B[82]
  PIN rd_out_A[83]
    DIRECTION OUTPUT ;
    USE SIGNAL ;
    SHAPE ABUTMENT ;
    PORT
      LAYER M4 ;
      RECT 0.000 22.320 0.024 22.344 ;
    END
  END rd_out_A[83]
  PIN rd_out_B[83]
    DIRECTION OUTPUT ;
    USE SIGNAL ;
    SHAPE ABUTMENT ;
    PORT
      LAYER M4 ;
      RECT 103.336 22.320 103.360 22.344 ;
    END
  END rd_out_B[83]
  PIN rd_out_A[84]
    DIRECTION OUTPUT ;
    USE SIGNAL ;
    SHAPE ABUTMENT ;
    PORT
      LAYER M4 ;
      RECT 0.000 22.416 0.024 22.440 ;
    END
  END rd_out_A[84]
  PIN rd_out_B[84]
    DIRECTION OUTPUT ;
    USE SIGNAL ;
    SHAPE ABUTMENT ;
    PORT
      LAYER M4 ;
      RECT 103.336 22.416 103.360 22.440 ;
    END
  END rd_out_B[84]
  PIN rd_out_A[85]
    DIRECTION OUTPUT ;
    USE SIGNAL ;
    SHAPE ABUTMENT ;
    PORT
      LAYER M4 ;
      RECT 0.000 22.512 0.024 22.536 ;
    END
  END rd_out_A[85]
  PIN rd_out_B[85]
    DIRECTION OUTPUT ;
    USE SIGNAL ;
    SHAPE ABUTMENT ;
    PORT
      LAYER M4 ;
      RECT 103.336 22.512 103.360 22.536 ;
    END
  END rd_out_B[85]
  PIN rd_out_A[86]
    DIRECTION OUTPUT ;
    USE SIGNAL ;
    SHAPE ABUTMENT ;
    PORT
      LAYER M4 ;
      RECT 0.000 22.608 0.024 22.632 ;
    END
  END rd_out_A[86]
  PIN rd_out_B[86]
    DIRECTION OUTPUT ;
    USE SIGNAL ;
    SHAPE ABUTMENT ;
    PORT
      LAYER M4 ;
      RECT 103.336 22.608 103.360 22.632 ;
    END
  END rd_out_B[86]
  PIN rd_out_A[87]
    DIRECTION OUTPUT ;
    USE SIGNAL ;
    SHAPE ABUTMENT ;
    PORT
      LAYER M4 ;
      RECT 0.000 22.704 0.024 22.728 ;
    END
  END rd_out_A[87]
  PIN rd_out_B[87]
    DIRECTION OUTPUT ;
    USE SIGNAL ;
    SHAPE ABUTMENT ;
    PORT
      LAYER M4 ;
      RECT 103.336 22.704 103.360 22.728 ;
    END
  END rd_out_B[87]
  PIN rd_out_A[88]
    DIRECTION OUTPUT ;
    USE SIGNAL ;
    SHAPE ABUTMENT ;
    PORT
      LAYER M4 ;
      RECT 0.000 22.800 0.024 22.824 ;
    END
  END rd_out_A[88]
  PIN rd_out_B[88]
    DIRECTION OUTPUT ;
    USE SIGNAL ;
    SHAPE ABUTMENT ;
    PORT
      LAYER M4 ;
      RECT 103.336 22.800 103.360 22.824 ;
    END
  END rd_out_B[88]
  PIN rd_out_A[89]
    DIRECTION OUTPUT ;
    USE SIGNAL ;
    SHAPE ABUTMENT ;
    PORT
      LAYER M4 ;
      RECT 0.000 22.896 0.024 22.920 ;
    END
  END rd_out_A[89]
  PIN rd_out_B[89]
    DIRECTION OUTPUT ;
    USE SIGNAL ;
    SHAPE ABUTMENT ;
    PORT
      LAYER M4 ;
      RECT 103.336 22.896 103.360 22.920 ;
    END
  END rd_out_B[89]
  PIN rd_out_A[90]
    DIRECTION OUTPUT ;
    USE SIGNAL ;
    SHAPE ABUTMENT ;
    PORT
      LAYER M4 ;
      RECT 0.000 22.992 0.024 23.016 ;
    END
  END rd_out_A[90]
  PIN rd_out_B[90]
    DIRECTION OUTPUT ;
    USE SIGNAL ;
    SHAPE ABUTMENT ;
    PORT
      LAYER M4 ;
      RECT 103.336 22.992 103.360 23.016 ;
    END
  END rd_out_B[90]
  PIN rd_out_A[91]
    DIRECTION OUTPUT ;
    USE SIGNAL ;
    SHAPE ABUTMENT ;
    PORT
      LAYER M4 ;
      RECT 0.000 23.088 0.024 23.112 ;
    END
  END rd_out_A[91]
  PIN rd_out_B[91]
    DIRECTION OUTPUT ;
    USE SIGNAL ;
    SHAPE ABUTMENT ;
    PORT
      LAYER M4 ;
      RECT 103.336 23.088 103.360 23.112 ;
    END
  END rd_out_B[91]
  PIN rd_out_A[92]
    DIRECTION OUTPUT ;
    USE SIGNAL ;
    SHAPE ABUTMENT ;
    PORT
      LAYER M4 ;
      RECT 0.000 23.184 0.024 23.208 ;
    END
  END rd_out_A[92]
  PIN rd_out_B[92]
    DIRECTION OUTPUT ;
    USE SIGNAL ;
    SHAPE ABUTMENT ;
    PORT
      LAYER M4 ;
      RECT 103.336 23.184 103.360 23.208 ;
    END
  END rd_out_B[92]
  PIN rd_out_A[93]
    DIRECTION OUTPUT ;
    USE SIGNAL ;
    SHAPE ABUTMENT ;
    PORT
      LAYER M4 ;
      RECT 0.000 23.280 0.024 23.304 ;
    END
  END rd_out_A[93]
  PIN rd_out_B[93]
    DIRECTION OUTPUT ;
    USE SIGNAL ;
    SHAPE ABUTMENT ;
    PORT
      LAYER M4 ;
      RECT 103.336 23.280 103.360 23.304 ;
    END
  END rd_out_B[93]
  PIN rd_out_A[94]
    DIRECTION OUTPUT ;
    USE SIGNAL ;
    SHAPE ABUTMENT ;
    PORT
      LAYER M4 ;
      RECT 0.000 23.376 0.024 23.400 ;
    END
  END rd_out_A[94]
  PIN rd_out_B[94]
    DIRECTION OUTPUT ;
    USE SIGNAL ;
    SHAPE ABUTMENT ;
    PORT
      LAYER M4 ;
      RECT 103.336 23.376 103.360 23.400 ;
    END
  END rd_out_B[94]
  PIN rd_out_A[95]
    DIRECTION OUTPUT ;
    USE SIGNAL ;
    SHAPE ABUTMENT ;
    PORT
      LAYER M4 ;
      RECT 0.000 23.472 0.024 23.496 ;
    END
  END rd_out_A[95]
  PIN rd_out_B[95]
    DIRECTION OUTPUT ;
    USE SIGNAL ;
    SHAPE ABUTMENT ;
    PORT
      LAYER M4 ;
      RECT 103.336 23.472 103.360 23.496 ;
    END
  END rd_out_B[95]
  PIN rd_out_A[96]
    DIRECTION OUTPUT ;
    USE SIGNAL ;
    SHAPE ABUTMENT ;
    PORT
      LAYER M4 ;
      RECT 0.000 23.568 0.024 23.592 ;
    END
  END rd_out_A[96]
  PIN rd_out_B[96]
    DIRECTION OUTPUT ;
    USE SIGNAL ;
    SHAPE ABUTMENT ;
    PORT
      LAYER M4 ;
      RECT 103.336 23.568 103.360 23.592 ;
    END
  END rd_out_B[96]
  PIN rd_out_A[97]
    DIRECTION OUTPUT ;
    USE SIGNAL ;
    SHAPE ABUTMENT ;
    PORT
      LAYER M4 ;
      RECT 0.000 23.664 0.024 23.688 ;
    END
  END rd_out_A[97]
  PIN rd_out_B[97]
    DIRECTION OUTPUT ;
    USE SIGNAL ;
    SHAPE ABUTMENT ;
    PORT
      LAYER M4 ;
      RECT 103.336 23.664 103.360 23.688 ;
    END
  END rd_out_B[97]
  PIN rd_out_A[98]
    DIRECTION OUTPUT ;
    USE SIGNAL ;
    SHAPE ABUTMENT ;
    PORT
      LAYER M4 ;
      RECT 0.000 23.760 0.024 23.784 ;
    END
  END rd_out_A[98]
  PIN rd_out_B[98]
    DIRECTION OUTPUT ;
    USE SIGNAL ;
    SHAPE ABUTMENT ;
    PORT
      LAYER M4 ;
      RECT 103.336 23.760 103.360 23.784 ;
    END
  END rd_out_B[98]
  PIN rd_out_A[99]
    DIRECTION OUTPUT ;
    USE SIGNAL ;
    SHAPE ABUTMENT ;
    PORT
      LAYER M4 ;
      RECT 0.000 23.856 0.024 23.880 ;
    END
  END rd_out_A[99]
  PIN rd_out_B[99]
    DIRECTION OUTPUT ;
    USE SIGNAL ;
    SHAPE ABUTMENT ;
    PORT
      LAYER M4 ;
      RECT 103.336 23.856 103.360 23.880 ;
    END
  END rd_out_B[99]
  PIN rd_out_A[100]
    DIRECTION OUTPUT ;
    USE SIGNAL ;
    SHAPE ABUTMENT ;
    PORT
      LAYER M4 ;
      RECT 0.000 23.952 0.024 23.976 ;
    END
  END rd_out_A[100]
  PIN rd_out_B[100]
    DIRECTION OUTPUT ;
    USE SIGNAL ;
    SHAPE ABUTMENT ;
    PORT
      LAYER M4 ;
      RECT 103.336 23.952 103.360 23.976 ;
    END
  END rd_out_B[100]
  PIN rd_out_A[101]
    DIRECTION OUTPUT ;
    USE SIGNAL ;
    SHAPE ABUTMENT ;
    PORT
      LAYER M4 ;
      RECT 0.000 24.048 0.024 24.072 ;
    END
  END rd_out_A[101]
  PIN rd_out_B[101]
    DIRECTION OUTPUT ;
    USE SIGNAL ;
    SHAPE ABUTMENT ;
    PORT
      LAYER M4 ;
      RECT 103.336 24.048 103.360 24.072 ;
    END
  END rd_out_B[101]
  PIN rd_out_A[102]
    DIRECTION OUTPUT ;
    USE SIGNAL ;
    SHAPE ABUTMENT ;
    PORT
      LAYER M4 ;
      RECT 0.000 24.144 0.024 24.168 ;
    END
  END rd_out_A[102]
  PIN rd_out_B[102]
    DIRECTION OUTPUT ;
    USE SIGNAL ;
    SHAPE ABUTMENT ;
    PORT
      LAYER M4 ;
      RECT 103.336 24.144 103.360 24.168 ;
    END
  END rd_out_B[102]
  PIN rd_out_A[103]
    DIRECTION OUTPUT ;
    USE SIGNAL ;
    SHAPE ABUTMENT ;
    PORT
      LAYER M4 ;
      RECT 0.000 24.240 0.024 24.264 ;
    END
  END rd_out_A[103]
  PIN rd_out_B[103]
    DIRECTION OUTPUT ;
    USE SIGNAL ;
    SHAPE ABUTMENT ;
    PORT
      LAYER M4 ;
      RECT 103.336 24.240 103.360 24.264 ;
    END
  END rd_out_B[103]
  PIN rd_out_A[104]
    DIRECTION OUTPUT ;
    USE SIGNAL ;
    SHAPE ABUTMENT ;
    PORT
      LAYER M4 ;
      RECT 0.000 24.336 0.024 24.360 ;
    END
  END rd_out_A[104]
  PIN rd_out_B[104]
    DIRECTION OUTPUT ;
    USE SIGNAL ;
    SHAPE ABUTMENT ;
    PORT
      LAYER M4 ;
      RECT 103.336 24.336 103.360 24.360 ;
    END
  END rd_out_B[104]
  PIN rd_out_A[105]
    DIRECTION OUTPUT ;
    USE SIGNAL ;
    SHAPE ABUTMENT ;
    PORT
      LAYER M4 ;
      RECT 0.000 24.432 0.024 24.456 ;
    END
  END rd_out_A[105]
  PIN rd_out_B[105]
    DIRECTION OUTPUT ;
    USE SIGNAL ;
    SHAPE ABUTMENT ;
    PORT
      LAYER M4 ;
      RECT 103.336 24.432 103.360 24.456 ;
    END
  END rd_out_B[105]
  PIN rd_out_A[106]
    DIRECTION OUTPUT ;
    USE SIGNAL ;
    SHAPE ABUTMENT ;
    PORT
      LAYER M4 ;
      RECT 0.000 24.528 0.024 24.552 ;
    END
  END rd_out_A[106]
  PIN rd_out_B[106]
    DIRECTION OUTPUT ;
    USE SIGNAL ;
    SHAPE ABUTMENT ;
    PORT
      LAYER M4 ;
      RECT 103.336 24.528 103.360 24.552 ;
    END
  END rd_out_B[106]
  PIN rd_out_A[107]
    DIRECTION OUTPUT ;
    USE SIGNAL ;
    SHAPE ABUTMENT ;
    PORT
      LAYER M4 ;
      RECT 0.000 24.624 0.024 24.648 ;
    END
  END rd_out_A[107]
  PIN rd_out_B[107]
    DIRECTION OUTPUT ;
    USE SIGNAL ;
    SHAPE ABUTMENT ;
    PORT
      LAYER M4 ;
      RECT 103.336 24.624 103.360 24.648 ;
    END
  END rd_out_B[107]
  PIN rd_out_A[108]
    DIRECTION OUTPUT ;
    USE SIGNAL ;
    SHAPE ABUTMENT ;
    PORT
      LAYER M4 ;
      RECT 0.000 24.720 0.024 24.744 ;
    END
  END rd_out_A[108]
  PIN rd_out_B[108]
    DIRECTION OUTPUT ;
    USE SIGNAL ;
    SHAPE ABUTMENT ;
    PORT
      LAYER M4 ;
      RECT 103.336 24.720 103.360 24.744 ;
    END
  END rd_out_B[108]
  PIN rd_out_A[109]
    DIRECTION OUTPUT ;
    USE SIGNAL ;
    SHAPE ABUTMENT ;
    PORT
      LAYER M4 ;
      RECT 0.000 24.816 0.024 24.840 ;
    END
  END rd_out_A[109]
  PIN rd_out_B[109]
    DIRECTION OUTPUT ;
    USE SIGNAL ;
    SHAPE ABUTMENT ;
    PORT
      LAYER M4 ;
      RECT 103.336 24.816 103.360 24.840 ;
    END
  END rd_out_B[109]
  PIN rd_out_A[110]
    DIRECTION OUTPUT ;
    USE SIGNAL ;
    SHAPE ABUTMENT ;
    PORT
      LAYER M4 ;
      RECT 0.000 24.912 0.024 24.936 ;
    END
  END rd_out_A[110]
  PIN rd_out_B[110]
    DIRECTION OUTPUT ;
    USE SIGNAL ;
    SHAPE ABUTMENT ;
    PORT
      LAYER M4 ;
      RECT 103.336 24.912 103.360 24.936 ;
    END
  END rd_out_B[110]
  PIN rd_out_A[111]
    DIRECTION OUTPUT ;
    USE SIGNAL ;
    SHAPE ABUTMENT ;
    PORT
      LAYER M4 ;
      RECT 0.000 25.008 0.024 25.032 ;
    END
  END rd_out_A[111]
  PIN rd_out_B[111]
    DIRECTION OUTPUT ;
    USE SIGNAL ;
    SHAPE ABUTMENT ;
    PORT
      LAYER M4 ;
      RECT 103.336 25.008 103.360 25.032 ;
    END
  END rd_out_B[111]
  PIN rd_out_A[112]
    DIRECTION OUTPUT ;
    USE SIGNAL ;
    SHAPE ABUTMENT ;
    PORT
      LAYER M4 ;
      RECT 0.000 25.104 0.024 25.128 ;
    END
  END rd_out_A[112]
  PIN rd_out_B[112]
    DIRECTION OUTPUT ;
    USE SIGNAL ;
    SHAPE ABUTMENT ;
    PORT
      LAYER M4 ;
      RECT 103.336 25.104 103.360 25.128 ;
    END
  END rd_out_B[112]
  PIN rd_out_A[113]
    DIRECTION OUTPUT ;
    USE SIGNAL ;
    SHAPE ABUTMENT ;
    PORT
      LAYER M4 ;
      RECT 0.000 25.200 0.024 25.224 ;
    END
  END rd_out_A[113]
  PIN rd_out_B[113]
    DIRECTION OUTPUT ;
    USE SIGNAL ;
    SHAPE ABUTMENT ;
    PORT
      LAYER M4 ;
      RECT 103.336 25.200 103.360 25.224 ;
    END
  END rd_out_B[113]
  PIN rd_out_A[114]
    DIRECTION OUTPUT ;
    USE SIGNAL ;
    SHAPE ABUTMENT ;
    PORT
      LAYER M4 ;
      RECT 0.000 25.296 0.024 25.320 ;
    END
  END rd_out_A[114]
  PIN rd_out_B[114]
    DIRECTION OUTPUT ;
    USE SIGNAL ;
    SHAPE ABUTMENT ;
    PORT
      LAYER M4 ;
      RECT 103.336 25.296 103.360 25.320 ;
    END
  END rd_out_B[114]
  PIN rd_out_A[115]
    DIRECTION OUTPUT ;
    USE SIGNAL ;
    SHAPE ABUTMENT ;
    PORT
      LAYER M4 ;
      RECT 0.000 25.392 0.024 25.416 ;
    END
  END rd_out_A[115]
  PIN rd_out_B[115]
    DIRECTION OUTPUT ;
    USE SIGNAL ;
    SHAPE ABUTMENT ;
    PORT
      LAYER M4 ;
      RECT 103.336 25.392 103.360 25.416 ;
    END
  END rd_out_B[115]
  PIN rd_out_A[116]
    DIRECTION OUTPUT ;
    USE SIGNAL ;
    SHAPE ABUTMENT ;
    PORT
      LAYER M4 ;
      RECT 0.000 25.488 0.024 25.512 ;
    END
  END rd_out_A[116]
  PIN rd_out_B[116]
    DIRECTION OUTPUT ;
    USE SIGNAL ;
    SHAPE ABUTMENT ;
    PORT
      LAYER M4 ;
      RECT 103.336 25.488 103.360 25.512 ;
    END
  END rd_out_B[116]
  PIN rd_out_A[117]
    DIRECTION OUTPUT ;
    USE SIGNAL ;
    SHAPE ABUTMENT ;
    PORT
      LAYER M4 ;
      RECT 0.000 25.584 0.024 25.608 ;
    END
  END rd_out_A[117]
  PIN rd_out_B[117]
    DIRECTION OUTPUT ;
    USE SIGNAL ;
    SHAPE ABUTMENT ;
    PORT
      LAYER M4 ;
      RECT 103.336 25.584 103.360 25.608 ;
    END
  END rd_out_B[117]
  PIN rd_out_A[118]
    DIRECTION OUTPUT ;
    USE SIGNAL ;
    SHAPE ABUTMENT ;
    PORT
      LAYER M4 ;
      RECT 0.000 25.680 0.024 25.704 ;
    END
  END rd_out_A[118]
  PIN rd_out_B[118]
    DIRECTION OUTPUT ;
    USE SIGNAL ;
    SHAPE ABUTMENT ;
    PORT
      LAYER M4 ;
      RECT 103.336 25.680 103.360 25.704 ;
    END
  END rd_out_B[118]
  PIN rd_out_A[119]
    DIRECTION OUTPUT ;
    USE SIGNAL ;
    SHAPE ABUTMENT ;
    PORT
      LAYER M4 ;
      RECT 0.000 25.776 0.024 25.800 ;
    END
  END rd_out_A[119]
  PIN rd_out_B[119]
    DIRECTION OUTPUT ;
    USE SIGNAL ;
    SHAPE ABUTMENT ;
    PORT
      LAYER M4 ;
      RECT 103.336 25.776 103.360 25.800 ;
    END
  END rd_out_B[119]
  PIN rd_out_A[120]
    DIRECTION OUTPUT ;
    USE SIGNAL ;
    SHAPE ABUTMENT ;
    PORT
      LAYER M4 ;
      RECT 0.000 25.872 0.024 25.896 ;
    END
  END rd_out_A[120]
  PIN rd_out_B[120]
    DIRECTION OUTPUT ;
    USE SIGNAL ;
    SHAPE ABUTMENT ;
    PORT
      LAYER M4 ;
      RECT 103.336 25.872 103.360 25.896 ;
    END
  END rd_out_B[120]
  PIN rd_out_A[121]
    DIRECTION OUTPUT ;
    USE SIGNAL ;
    SHAPE ABUTMENT ;
    PORT
      LAYER M4 ;
      RECT 0.000 25.968 0.024 25.992 ;
    END
  END rd_out_A[121]
  PIN rd_out_B[121]
    DIRECTION OUTPUT ;
    USE SIGNAL ;
    SHAPE ABUTMENT ;
    PORT
      LAYER M4 ;
      RECT 103.336 25.968 103.360 25.992 ;
    END
  END rd_out_B[121]
  PIN rd_out_A[122]
    DIRECTION OUTPUT ;
    USE SIGNAL ;
    SHAPE ABUTMENT ;
    PORT
      LAYER M4 ;
      RECT 0.000 26.064 0.024 26.088 ;
    END
  END rd_out_A[122]
  PIN rd_out_B[122]
    DIRECTION OUTPUT ;
    USE SIGNAL ;
    SHAPE ABUTMENT ;
    PORT
      LAYER M4 ;
      RECT 103.336 26.064 103.360 26.088 ;
    END
  END rd_out_B[122]
  PIN rd_out_A[123]
    DIRECTION OUTPUT ;
    USE SIGNAL ;
    SHAPE ABUTMENT ;
    PORT
      LAYER M4 ;
      RECT 0.000 26.160 0.024 26.184 ;
    END
  END rd_out_A[123]
  PIN rd_out_B[123]
    DIRECTION OUTPUT ;
    USE SIGNAL ;
    SHAPE ABUTMENT ;
    PORT
      LAYER M4 ;
      RECT 103.336 26.160 103.360 26.184 ;
    END
  END rd_out_B[123]
  PIN rd_out_A[124]
    DIRECTION OUTPUT ;
    USE SIGNAL ;
    SHAPE ABUTMENT ;
    PORT
      LAYER M4 ;
      RECT 0.000 26.256 0.024 26.280 ;
    END
  END rd_out_A[124]
  PIN rd_out_B[124]
    DIRECTION OUTPUT ;
    USE SIGNAL ;
    SHAPE ABUTMENT ;
    PORT
      LAYER M4 ;
      RECT 103.336 26.256 103.360 26.280 ;
    END
  END rd_out_B[124]
  PIN rd_out_A[125]
    DIRECTION OUTPUT ;
    USE SIGNAL ;
    SHAPE ABUTMENT ;
    PORT
      LAYER M4 ;
      RECT 0.000 26.352 0.024 26.376 ;
    END
  END rd_out_A[125]
  PIN rd_out_B[125]
    DIRECTION OUTPUT ;
    USE SIGNAL ;
    SHAPE ABUTMENT ;
    PORT
      LAYER M4 ;
      RECT 103.336 26.352 103.360 26.376 ;
    END
  END rd_out_B[125]
  PIN rd_out_A[126]
    DIRECTION OUTPUT ;
    USE SIGNAL ;
    SHAPE ABUTMENT ;
    PORT
      LAYER M4 ;
      RECT 0.000 26.448 0.024 26.472 ;
    END
  END rd_out_A[126]
  PIN rd_out_B[126]
    DIRECTION OUTPUT ;
    USE SIGNAL ;
    SHAPE ABUTMENT ;
    PORT
      LAYER M4 ;
      RECT 103.336 26.448 103.360 26.472 ;
    END
  END rd_out_B[126]
  PIN rd_out_A[127]
    DIRECTION OUTPUT ;
    USE SIGNAL ;
    SHAPE ABUTMENT ;
    PORT
      LAYER M4 ;
      RECT 0.000 26.544 0.024 26.568 ;
    END
  END rd_out_A[127]
  PIN rd_out_B[127]
    DIRECTION OUTPUT ;
    USE SIGNAL ;
    SHAPE ABUTMENT ;
    PORT
      LAYER M4 ;
      RECT 103.336 26.544 103.360 26.568 ;
    END
  END rd_out_B[127]
  PIN wd_in_A[0]
    DIRECTION INPUT ;
    USE SIGNAL ;
    SHAPE ABUTMENT ;
    PORT
      LAYER M4 ;
      RECT 0.000 28.656 0.024 28.680 ;
    END
  END wd_in_A[0]
  PIN wd_in_B[0]
    DIRECTION INPUT ;
    USE SIGNAL ;
    SHAPE ABUTMENT ;
    PORT
      LAYER M4 ;
      RECT 103.336 28.656 103.360 28.680 ;
    END
  END wd_in_B[0]
  PIN wd_in_A[1]
    DIRECTION INPUT ;
    USE SIGNAL ;
    SHAPE ABUTMENT ;
    PORT
      LAYER M4 ;
      RECT 0.000 28.752 0.024 28.776 ;
    END
  END wd_in_A[1]
  PIN wd_in_B[1]
    DIRECTION INPUT ;
    USE SIGNAL ;
    SHAPE ABUTMENT ;
    PORT
      LAYER M4 ;
      RECT 103.336 28.752 103.360 28.776 ;
    END
  END wd_in_B[1]
  PIN wd_in_A[2]
    DIRECTION INPUT ;
    USE SIGNAL ;
    SHAPE ABUTMENT ;
    PORT
      LAYER M4 ;
      RECT 0.000 28.848 0.024 28.872 ;
    END
  END wd_in_A[2]
  PIN wd_in_B[2]
    DIRECTION INPUT ;
    USE SIGNAL ;
    SHAPE ABUTMENT ;
    PORT
      LAYER M4 ;
      RECT 103.336 28.848 103.360 28.872 ;
    END
  END wd_in_B[2]
  PIN wd_in_A[3]
    DIRECTION INPUT ;
    USE SIGNAL ;
    SHAPE ABUTMENT ;
    PORT
      LAYER M4 ;
      RECT 0.000 28.944 0.024 28.968 ;
    END
  END wd_in_A[3]
  PIN wd_in_B[3]
    DIRECTION INPUT ;
    USE SIGNAL ;
    SHAPE ABUTMENT ;
    PORT
      LAYER M4 ;
      RECT 103.336 28.944 103.360 28.968 ;
    END
  END wd_in_B[3]
  PIN wd_in_A[4]
    DIRECTION INPUT ;
    USE SIGNAL ;
    SHAPE ABUTMENT ;
    PORT
      LAYER M4 ;
      RECT 0.000 29.040 0.024 29.064 ;
    END
  END wd_in_A[4]
  PIN wd_in_B[4]
    DIRECTION INPUT ;
    USE SIGNAL ;
    SHAPE ABUTMENT ;
    PORT
      LAYER M4 ;
      RECT 103.336 29.040 103.360 29.064 ;
    END
  END wd_in_B[4]
  PIN wd_in_A[5]
    DIRECTION INPUT ;
    USE SIGNAL ;
    SHAPE ABUTMENT ;
    PORT
      LAYER M4 ;
      RECT 0.000 29.136 0.024 29.160 ;
    END
  END wd_in_A[5]
  PIN wd_in_B[5]
    DIRECTION INPUT ;
    USE SIGNAL ;
    SHAPE ABUTMENT ;
    PORT
      LAYER M4 ;
      RECT 103.336 29.136 103.360 29.160 ;
    END
  END wd_in_B[5]
  PIN wd_in_A[6]
    DIRECTION INPUT ;
    USE SIGNAL ;
    SHAPE ABUTMENT ;
    PORT
      LAYER M4 ;
      RECT 0.000 29.232 0.024 29.256 ;
    END
  END wd_in_A[6]
  PIN wd_in_B[6]
    DIRECTION INPUT ;
    USE SIGNAL ;
    SHAPE ABUTMENT ;
    PORT
      LAYER M4 ;
      RECT 103.336 29.232 103.360 29.256 ;
    END
  END wd_in_B[6]
  PIN wd_in_A[7]
    DIRECTION INPUT ;
    USE SIGNAL ;
    SHAPE ABUTMENT ;
    PORT
      LAYER M4 ;
      RECT 0.000 29.328 0.024 29.352 ;
    END
  END wd_in_A[7]
  PIN wd_in_B[7]
    DIRECTION INPUT ;
    USE SIGNAL ;
    SHAPE ABUTMENT ;
    PORT
      LAYER M4 ;
      RECT 103.336 29.328 103.360 29.352 ;
    END
  END wd_in_B[7]
  PIN wd_in_A[8]
    DIRECTION INPUT ;
    USE SIGNAL ;
    SHAPE ABUTMENT ;
    PORT
      LAYER M4 ;
      RECT 0.000 29.424 0.024 29.448 ;
    END
  END wd_in_A[8]
  PIN wd_in_B[8]
    DIRECTION INPUT ;
    USE SIGNAL ;
    SHAPE ABUTMENT ;
    PORT
      LAYER M4 ;
      RECT 103.336 29.424 103.360 29.448 ;
    END
  END wd_in_B[8]
  PIN wd_in_A[9]
    DIRECTION INPUT ;
    USE SIGNAL ;
    SHAPE ABUTMENT ;
    PORT
      LAYER M4 ;
      RECT 0.000 29.520 0.024 29.544 ;
    END
  END wd_in_A[9]
  PIN wd_in_B[9]
    DIRECTION INPUT ;
    USE SIGNAL ;
    SHAPE ABUTMENT ;
    PORT
      LAYER M4 ;
      RECT 103.336 29.520 103.360 29.544 ;
    END
  END wd_in_B[9]
  PIN wd_in_A[10]
    DIRECTION INPUT ;
    USE SIGNAL ;
    SHAPE ABUTMENT ;
    PORT
      LAYER M4 ;
      RECT 0.000 29.616 0.024 29.640 ;
    END
  END wd_in_A[10]
  PIN wd_in_B[10]
    DIRECTION INPUT ;
    USE SIGNAL ;
    SHAPE ABUTMENT ;
    PORT
      LAYER M4 ;
      RECT 103.336 29.616 103.360 29.640 ;
    END
  END wd_in_B[10]
  PIN wd_in_A[11]
    DIRECTION INPUT ;
    USE SIGNAL ;
    SHAPE ABUTMENT ;
    PORT
      LAYER M4 ;
      RECT 0.000 29.712 0.024 29.736 ;
    END
  END wd_in_A[11]
  PIN wd_in_B[11]
    DIRECTION INPUT ;
    USE SIGNAL ;
    SHAPE ABUTMENT ;
    PORT
      LAYER M4 ;
      RECT 103.336 29.712 103.360 29.736 ;
    END
  END wd_in_B[11]
  PIN wd_in_A[12]
    DIRECTION INPUT ;
    USE SIGNAL ;
    SHAPE ABUTMENT ;
    PORT
      LAYER M4 ;
      RECT 0.000 29.808 0.024 29.832 ;
    END
  END wd_in_A[12]
  PIN wd_in_B[12]
    DIRECTION INPUT ;
    USE SIGNAL ;
    SHAPE ABUTMENT ;
    PORT
      LAYER M4 ;
      RECT 103.336 29.808 103.360 29.832 ;
    END
  END wd_in_B[12]
  PIN wd_in_A[13]
    DIRECTION INPUT ;
    USE SIGNAL ;
    SHAPE ABUTMENT ;
    PORT
      LAYER M4 ;
      RECT 0.000 29.904 0.024 29.928 ;
    END
  END wd_in_A[13]
  PIN wd_in_B[13]
    DIRECTION INPUT ;
    USE SIGNAL ;
    SHAPE ABUTMENT ;
    PORT
      LAYER M4 ;
      RECT 103.336 29.904 103.360 29.928 ;
    END
  END wd_in_B[13]
  PIN wd_in_A[14]
    DIRECTION INPUT ;
    USE SIGNAL ;
    SHAPE ABUTMENT ;
    PORT
      LAYER M4 ;
      RECT 0.000 30.000 0.024 30.024 ;
    END
  END wd_in_A[14]
  PIN wd_in_B[14]
    DIRECTION INPUT ;
    USE SIGNAL ;
    SHAPE ABUTMENT ;
    PORT
      LAYER M4 ;
      RECT 103.336 30.000 103.360 30.024 ;
    END
  END wd_in_B[14]
  PIN wd_in_A[15]
    DIRECTION INPUT ;
    USE SIGNAL ;
    SHAPE ABUTMENT ;
    PORT
      LAYER M4 ;
      RECT 0.000 30.096 0.024 30.120 ;
    END
  END wd_in_A[15]
  PIN wd_in_B[15]
    DIRECTION INPUT ;
    USE SIGNAL ;
    SHAPE ABUTMENT ;
    PORT
      LAYER M4 ;
      RECT 103.336 30.096 103.360 30.120 ;
    END
  END wd_in_B[15]
  PIN wd_in_A[16]
    DIRECTION INPUT ;
    USE SIGNAL ;
    SHAPE ABUTMENT ;
    PORT
      LAYER M4 ;
      RECT 0.000 30.192 0.024 30.216 ;
    END
  END wd_in_A[16]
  PIN wd_in_B[16]
    DIRECTION INPUT ;
    USE SIGNAL ;
    SHAPE ABUTMENT ;
    PORT
      LAYER M4 ;
      RECT 103.336 30.192 103.360 30.216 ;
    END
  END wd_in_B[16]
  PIN wd_in_A[17]
    DIRECTION INPUT ;
    USE SIGNAL ;
    SHAPE ABUTMENT ;
    PORT
      LAYER M4 ;
      RECT 0.000 30.288 0.024 30.312 ;
    END
  END wd_in_A[17]
  PIN wd_in_B[17]
    DIRECTION INPUT ;
    USE SIGNAL ;
    SHAPE ABUTMENT ;
    PORT
      LAYER M4 ;
      RECT 103.336 30.288 103.360 30.312 ;
    END
  END wd_in_B[17]
  PIN wd_in_A[18]
    DIRECTION INPUT ;
    USE SIGNAL ;
    SHAPE ABUTMENT ;
    PORT
      LAYER M4 ;
      RECT 0.000 30.384 0.024 30.408 ;
    END
  END wd_in_A[18]
  PIN wd_in_B[18]
    DIRECTION INPUT ;
    USE SIGNAL ;
    SHAPE ABUTMENT ;
    PORT
      LAYER M4 ;
      RECT 103.336 30.384 103.360 30.408 ;
    END
  END wd_in_B[18]
  PIN wd_in_A[19]
    DIRECTION INPUT ;
    USE SIGNAL ;
    SHAPE ABUTMENT ;
    PORT
      LAYER M4 ;
      RECT 0.000 30.480 0.024 30.504 ;
    END
  END wd_in_A[19]
  PIN wd_in_B[19]
    DIRECTION INPUT ;
    USE SIGNAL ;
    SHAPE ABUTMENT ;
    PORT
      LAYER M4 ;
      RECT 103.336 30.480 103.360 30.504 ;
    END
  END wd_in_B[19]
  PIN wd_in_A[20]
    DIRECTION INPUT ;
    USE SIGNAL ;
    SHAPE ABUTMENT ;
    PORT
      LAYER M4 ;
      RECT 0.000 30.576 0.024 30.600 ;
    END
  END wd_in_A[20]
  PIN wd_in_B[20]
    DIRECTION INPUT ;
    USE SIGNAL ;
    SHAPE ABUTMENT ;
    PORT
      LAYER M4 ;
      RECT 103.336 30.576 103.360 30.600 ;
    END
  END wd_in_B[20]
  PIN wd_in_A[21]
    DIRECTION INPUT ;
    USE SIGNAL ;
    SHAPE ABUTMENT ;
    PORT
      LAYER M4 ;
      RECT 0.000 30.672 0.024 30.696 ;
    END
  END wd_in_A[21]
  PIN wd_in_B[21]
    DIRECTION INPUT ;
    USE SIGNAL ;
    SHAPE ABUTMENT ;
    PORT
      LAYER M4 ;
      RECT 103.336 30.672 103.360 30.696 ;
    END
  END wd_in_B[21]
  PIN wd_in_A[22]
    DIRECTION INPUT ;
    USE SIGNAL ;
    SHAPE ABUTMENT ;
    PORT
      LAYER M4 ;
      RECT 0.000 30.768 0.024 30.792 ;
    END
  END wd_in_A[22]
  PIN wd_in_B[22]
    DIRECTION INPUT ;
    USE SIGNAL ;
    SHAPE ABUTMENT ;
    PORT
      LAYER M4 ;
      RECT 103.336 30.768 103.360 30.792 ;
    END
  END wd_in_B[22]
  PIN wd_in_A[23]
    DIRECTION INPUT ;
    USE SIGNAL ;
    SHAPE ABUTMENT ;
    PORT
      LAYER M4 ;
      RECT 0.000 30.864 0.024 30.888 ;
    END
  END wd_in_A[23]
  PIN wd_in_B[23]
    DIRECTION INPUT ;
    USE SIGNAL ;
    SHAPE ABUTMENT ;
    PORT
      LAYER M4 ;
      RECT 103.336 30.864 103.360 30.888 ;
    END
  END wd_in_B[23]
  PIN wd_in_A[24]
    DIRECTION INPUT ;
    USE SIGNAL ;
    SHAPE ABUTMENT ;
    PORT
      LAYER M4 ;
      RECT 0.000 30.960 0.024 30.984 ;
    END
  END wd_in_A[24]
  PIN wd_in_B[24]
    DIRECTION INPUT ;
    USE SIGNAL ;
    SHAPE ABUTMENT ;
    PORT
      LAYER M4 ;
      RECT 103.336 30.960 103.360 30.984 ;
    END
  END wd_in_B[24]
  PIN wd_in_A[25]
    DIRECTION INPUT ;
    USE SIGNAL ;
    SHAPE ABUTMENT ;
    PORT
      LAYER M4 ;
      RECT 0.000 31.056 0.024 31.080 ;
    END
  END wd_in_A[25]
  PIN wd_in_B[25]
    DIRECTION INPUT ;
    USE SIGNAL ;
    SHAPE ABUTMENT ;
    PORT
      LAYER M4 ;
      RECT 103.336 31.056 103.360 31.080 ;
    END
  END wd_in_B[25]
  PIN wd_in_A[26]
    DIRECTION INPUT ;
    USE SIGNAL ;
    SHAPE ABUTMENT ;
    PORT
      LAYER M4 ;
      RECT 0.000 31.152 0.024 31.176 ;
    END
  END wd_in_A[26]
  PIN wd_in_B[26]
    DIRECTION INPUT ;
    USE SIGNAL ;
    SHAPE ABUTMENT ;
    PORT
      LAYER M4 ;
      RECT 103.336 31.152 103.360 31.176 ;
    END
  END wd_in_B[26]
  PIN wd_in_A[27]
    DIRECTION INPUT ;
    USE SIGNAL ;
    SHAPE ABUTMENT ;
    PORT
      LAYER M4 ;
      RECT 0.000 31.248 0.024 31.272 ;
    END
  END wd_in_A[27]
  PIN wd_in_B[27]
    DIRECTION INPUT ;
    USE SIGNAL ;
    SHAPE ABUTMENT ;
    PORT
      LAYER M4 ;
      RECT 103.336 31.248 103.360 31.272 ;
    END
  END wd_in_B[27]
  PIN wd_in_A[28]
    DIRECTION INPUT ;
    USE SIGNAL ;
    SHAPE ABUTMENT ;
    PORT
      LAYER M4 ;
      RECT 0.000 31.344 0.024 31.368 ;
    END
  END wd_in_A[28]
  PIN wd_in_B[28]
    DIRECTION INPUT ;
    USE SIGNAL ;
    SHAPE ABUTMENT ;
    PORT
      LAYER M4 ;
      RECT 103.336 31.344 103.360 31.368 ;
    END
  END wd_in_B[28]
  PIN wd_in_A[29]
    DIRECTION INPUT ;
    USE SIGNAL ;
    SHAPE ABUTMENT ;
    PORT
      LAYER M4 ;
      RECT 0.000 31.440 0.024 31.464 ;
    END
  END wd_in_A[29]
  PIN wd_in_B[29]
    DIRECTION INPUT ;
    USE SIGNAL ;
    SHAPE ABUTMENT ;
    PORT
      LAYER M4 ;
      RECT 103.336 31.440 103.360 31.464 ;
    END
  END wd_in_B[29]
  PIN wd_in_A[30]
    DIRECTION INPUT ;
    USE SIGNAL ;
    SHAPE ABUTMENT ;
    PORT
      LAYER M4 ;
      RECT 0.000 31.536 0.024 31.560 ;
    END
  END wd_in_A[30]
  PIN wd_in_B[30]
    DIRECTION INPUT ;
    USE SIGNAL ;
    SHAPE ABUTMENT ;
    PORT
      LAYER M4 ;
      RECT 103.336 31.536 103.360 31.560 ;
    END
  END wd_in_B[30]
  PIN wd_in_A[31]
    DIRECTION INPUT ;
    USE SIGNAL ;
    SHAPE ABUTMENT ;
    PORT
      LAYER M4 ;
      RECT 0.000 31.632 0.024 31.656 ;
    END
  END wd_in_A[31]
  PIN wd_in_B[31]
    DIRECTION INPUT ;
    USE SIGNAL ;
    SHAPE ABUTMENT ;
    PORT
      LAYER M4 ;
      RECT 103.336 31.632 103.360 31.656 ;
    END
  END wd_in_B[31]
  PIN wd_in_A[32]
    DIRECTION INPUT ;
    USE SIGNAL ;
    SHAPE ABUTMENT ;
    PORT
      LAYER M4 ;
      RECT 0.000 31.728 0.024 31.752 ;
    END
  END wd_in_A[32]
  PIN wd_in_B[32]
    DIRECTION INPUT ;
    USE SIGNAL ;
    SHAPE ABUTMENT ;
    PORT
      LAYER M4 ;
      RECT 103.336 31.728 103.360 31.752 ;
    END
  END wd_in_B[32]
  PIN wd_in_A[33]
    DIRECTION INPUT ;
    USE SIGNAL ;
    SHAPE ABUTMENT ;
    PORT
      LAYER M4 ;
      RECT 0.000 31.824 0.024 31.848 ;
    END
  END wd_in_A[33]
  PIN wd_in_B[33]
    DIRECTION INPUT ;
    USE SIGNAL ;
    SHAPE ABUTMENT ;
    PORT
      LAYER M4 ;
      RECT 103.336 31.824 103.360 31.848 ;
    END
  END wd_in_B[33]
  PIN wd_in_A[34]
    DIRECTION INPUT ;
    USE SIGNAL ;
    SHAPE ABUTMENT ;
    PORT
      LAYER M4 ;
      RECT 0.000 31.920 0.024 31.944 ;
    END
  END wd_in_A[34]
  PIN wd_in_B[34]
    DIRECTION INPUT ;
    USE SIGNAL ;
    SHAPE ABUTMENT ;
    PORT
      LAYER M4 ;
      RECT 103.336 31.920 103.360 31.944 ;
    END
  END wd_in_B[34]
  PIN wd_in_A[35]
    DIRECTION INPUT ;
    USE SIGNAL ;
    SHAPE ABUTMENT ;
    PORT
      LAYER M4 ;
      RECT 0.000 32.016 0.024 32.040 ;
    END
  END wd_in_A[35]
  PIN wd_in_B[35]
    DIRECTION INPUT ;
    USE SIGNAL ;
    SHAPE ABUTMENT ;
    PORT
      LAYER M4 ;
      RECT 103.336 32.016 103.360 32.040 ;
    END
  END wd_in_B[35]
  PIN wd_in_A[36]
    DIRECTION INPUT ;
    USE SIGNAL ;
    SHAPE ABUTMENT ;
    PORT
      LAYER M4 ;
      RECT 0.000 32.112 0.024 32.136 ;
    END
  END wd_in_A[36]
  PIN wd_in_B[36]
    DIRECTION INPUT ;
    USE SIGNAL ;
    SHAPE ABUTMENT ;
    PORT
      LAYER M4 ;
      RECT 103.336 32.112 103.360 32.136 ;
    END
  END wd_in_B[36]
  PIN wd_in_A[37]
    DIRECTION INPUT ;
    USE SIGNAL ;
    SHAPE ABUTMENT ;
    PORT
      LAYER M4 ;
      RECT 0.000 32.208 0.024 32.232 ;
    END
  END wd_in_A[37]
  PIN wd_in_B[37]
    DIRECTION INPUT ;
    USE SIGNAL ;
    SHAPE ABUTMENT ;
    PORT
      LAYER M4 ;
      RECT 103.336 32.208 103.360 32.232 ;
    END
  END wd_in_B[37]
  PIN wd_in_A[38]
    DIRECTION INPUT ;
    USE SIGNAL ;
    SHAPE ABUTMENT ;
    PORT
      LAYER M4 ;
      RECT 0.000 32.304 0.024 32.328 ;
    END
  END wd_in_A[38]
  PIN wd_in_B[38]
    DIRECTION INPUT ;
    USE SIGNAL ;
    SHAPE ABUTMENT ;
    PORT
      LAYER M4 ;
      RECT 103.336 32.304 103.360 32.328 ;
    END
  END wd_in_B[38]
  PIN wd_in_A[39]
    DIRECTION INPUT ;
    USE SIGNAL ;
    SHAPE ABUTMENT ;
    PORT
      LAYER M4 ;
      RECT 0.000 32.400 0.024 32.424 ;
    END
  END wd_in_A[39]
  PIN wd_in_B[39]
    DIRECTION INPUT ;
    USE SIGNAL ;
    SHAPE ABUTMENT ;
    PORT
      LAYER M4 ;
      RECT 103.336 32.400 103.360 32.424 ;
    END
  END wd_in_B[39]
  PIN wd_in_A[40]
    DIRECTION INPUT ;
    USE SIGNAL ;
    SHAPE ABUTMENT ;
    PORT
      LAYER M4 ;
      RECT 0.000 32.496 0.024 32.520 ;
    END
  END wd_in_A[40]
  PIN wd_in_B[40]
    DIRECTION INPUT ;
    USE SIGNAL ;
    SHAPE ABUTMENT ;
    PORT
      LAYER M4 ;
      RECT 103.336 32.496 103.360 32.520 ;
    END
  END wd_in_B[40]
  PIN wd_in_A[41]
    DIRECTION INPUT ;
    USE SIGNAL ;
    SHAPE ABUTMENT ;
    PORT
      LAYER M4 ;
      RECT 0.000 32.592 0.024 32.616 ;
    END
  END wd_in_A[41]
  PIN wd_in_B[41]
    DIRECTION INPUT ;
    USE SIGNAL ;
    SHAPE ABUTMENT ;
    PORT
      LAYER M4 ;
      RECT 103.336 32.592 103.360 32.616 ;
    END
  END wd_in_B[41]
  PIN wd_in_A[42]
    DIRECTION INPUT ;
    USE SIGNAL ;
    SHAPE ABUTMENT ;
    PORT
      LAYER M4 ;
      RECT 0.000 32.688 0.024 32.712 ;
    END
  END wd_in_A[42]
  PIN wd_in_B[42]
    DIRECTION INPUT ;
    USE SIGNAL ;
    SHAPE ABUTMENT ;
    PORT
      LAYER M4 ;
      RECT 103.336 32.688 103.360 32.712 ;
    END
  END wd_in_B[42]
  PIN wd_in_A[43]
    DIRECTION INPUT ;
    USE SIGNAL ;
    SHAPE ABUTMENT ;
    PORT
      LAYER M4 ;
      RECT 0.000 32.784 0.024 32.808 ;
    END
  END wd_in_A[43]
  PIN wd_in_B[43]
    DIRECTION INPUT ;
    USE SIGNAL ;
    SHAPE ABUTMENT ;
    PORT
      LAYER M4 ;
      RECT 103.336 32.784 103.360 32.808 ;
    END
  END wd_in_B[43]
  PIN wd_in_A[44]
    DIRECTION INPUT ;
    USE SIGNAL ;
    SHAPE ABUTMENT ;
    PORT
      LAYER M4 ;
      RECT 0.000 32.880 0.024 32.904 ;
    END
  END wd_in_A[44]
  PIN wd_in_B[44]
    DIRECTION INPUT ;
    USE SIGNAL ;
    SHAPE ABUTMENT ;
    PORT
      LAYER M4 ;
      RECT 103.336 32.880 103.360 32.904 ;
    END
  END wd_in_B[44]
  PIN wd_in_A[45]
    DIRECTION INPUT ;
    USE SIGNAL ;
    SHAPE ABUTMENT ;
    PORT
      LAYER M4 ;
      RECT 0.000 32.976 0.024 33.000 ;
    END
  END wd_in_A[45]
  PIN wd_in_B[45]
    DIRECTION INPUT ;
    USE SIGNAL ;
    SHAPE ABUTMENT ;
    PORT
      LAYER M4 ;
      RECT 103.336 32.976 103.360 33.000 ;
    END
  END wd_in_B[45]
  PIN wd_in_A[46]
    DIRECTION INPUT ;
    USE SIGNAL ;
    SHAPE ABUTMENT ;
    PORT
      LAYER M4 ;
      RECT 0.000 33.072 0.024 33.096 ;
    END
  END wd_in_A[46]
  PIN wd_in_B[46]
    DIRECTION INPUT ;
    USE SIGNAL ;
    SHAPE ABUTMENT ;
    PORT
      LAYER M4 ;
      RECT 103.336 33.072 103.360 33.096 ;
    END
  END wd_in_B[46]
  PIN wd_in_A[47]
    DIRECTION INPUT ;
    USE SIGNAL ;
    SHAPE ABUTMENT ;
    PORT
      LAYER M4 ;
      RECT 0.000 33.168 0.024 33.192 ;
    END
  END wd_in_A[47]
  PIN wd_in_B[47]
    DIRECTION INPUT ;
    USE SIGNAL ;
    SHAPE ABUTMENT ;
    PORT
      LAYER M4 ;
      RECT 103.336 33.168 103.360 33.192 ;
    END
  END wd_in_B[47]
  PIN wd_in_A[48]
    DIRECTION INPUT ;
    USE SIGNAL ;
    SHAPE ABUTMENT ;
    PORT
      LAYER M4 ;
      RECT 0.000 33.264 0.024 33.288 ;
    END
  END wd_in_A[48]
  PIN wd_in_B[48]
    DIRECTION INPUT ;
    USE SIGNAL ;
    SHAPE ABUTMENT ;
    PORT
      LAYER M4 ;
      RECT 103.336 33.264 103.360 33.288 ;
    END
  END wd_in_B[48]
  PIN wd_in_A[49]
    DIRECTION INPUT ;
    USE SIGNAL ;
    SHAPE ABUTMENT ;
    PORT
      LAYER M4 ;
      RECT 0.000 33.360 0.024 33.384 ;
    END
  END wd_in_A[49]
  PIN wd_in_B[49]
    DIRECTION INPUT ;
    USE SIGNAL ;
    SHAPE ABUTMENT ;
    PORT
      LAYER M4 ;
      RECT 103.336 33.360 103.360 33.384 ;
    END
  END wd_in_B[49]
  PIN wd_in_A[50]
    DIRECTION INPUT ;
    USE SIGNAL ;
    SHAPE ABUTMENT ;
    PORT
      LAYER M4 ;
      RECT 0.000 33.456 0.024 33.480 ;
    END
  END wd_in_A[50]
  PIN wd_in_B[50]
    DIRECTION INPUT ;
    USE SIGNAL ;
    SHAPE ABUTMENT ;
    PORT
      LAYER M4 ;
      RECT 103.336 33.456 103.360 33.480 ;
    END
  END wd_in_B[50]
  PIN wd_in_A[51]
    DIRECTION INPUT ;
    USE SIGNAL ;
    SHAPE ABUTMENT ;
    PORT
      LAYER M4 ;
      RECT 0.000 33.552 0.024 33.576 ;
    END
  END wd_in_A[51]
  PIN wd_in_B[51]
    DIRECTION INPUT ;
    USE SIGNAL ;
    SHAPE ABUTMENT ;
    PORT
      LAYER M4 ;
      RECT 103.336 33.552 103.360 33.576 ;
    END
  END wd_in_B[51]
  PIN wd_in_A[52]
    DIRECTION INPUT ;
    USE SIGNAL ;
    SHAPE ABUTMENT ;
    PORT
      LAYER M4 ;
      RECT 0.000 33.648 0.024 33.672 ;
    END
  END wd_in_A[52]
  PIN wd_in_B[52]
    DIRECTION INPUT ;
    USE SIGNAL ;
    SHAPE ABUTMENT ;
    PORT
      LAYER M4 ;
      RECT 103.336 33.648 103.360 33.672 ;
    END
  END wd_in_B[52]
  PIN wd_in_A[53]
    DIRECTION INPUT ;
    USE SIGNAL ;
    SHAPE ABUTMENT ;
    PORT
      LAYER M4 ;
      RECT 0.000 33.744 0.024 33.768 ;
    END
  END wd_in_A[53]
  PIN wd_in_B[53]
    DIRECTION INPUT ;
    USE SIGNAL ;
    SHAPE ABUTMENT ;
    PORT
      LAYER M4 ;
      RECT 103.336 33.744 103.360 33.768 ;
    END
  END wd_in_B[53]
  PIN wd_in_A[54]
    DIRECTION INPUT ;
    USE SIGNAL ;
    SHAPE ABUTMENT ;
    PORT
      LAYER M4 ;
      RECT 0.000 33.840 0.024 33.864 ;
    END
  END wd_in_A[54]
  PIN wd_in_B[54]
    DIRECTION INPUT ;
    USE SIGNAL ;
    SHAPE ABUTMENT ;
    PORT
      LAYER M4 ;
      RECT 103.336 33.840 103.360 33.864 ;
    END
  END wd_in_B[54]
  PIN wd_in_A[55]
    DIRECTION INPUT ;
    USE SIGNAL ;
    SHAPE ABUTMENT ;
    PORT
      LAYER M4 ;
      RECT 0.000 33.936 0.024 33.960 ;
    END
  END wd_in_A[55]
  PIN wd_in_B[55]
    DIRECTION INPUT ;
    USE SIGNAL ;
    SHAPE ABUTMENT ;
    PORT
      LAYER M4 ;
      RECT 103.336 33.936 103.360 33.960 ;
    END
  END wd_in_B[55]
  PIN wd_in_A[56]
    DIRECTION INPUT ;
    USE SIGNAL ;
    SHAPE ABUTMENT ;
    PORT
      LAYER M4 ;
      RECT 0.000 34.032 0.024 34.056 ;
    END
  END wd_in_A[56]
  PIN wd_in_B[56]
    DIRECTION INPUT ;
    USE SIGNAL ;
    SHAPE ABUTMENT ;
    PORT
      LAYER M4 ;
      RECT 103.336 34.032 103.360 34.056 ;
    END
  END wd_in_B[56]
  PIN wd_in_A[57]
    DIRECTION INPUT ;
    USE SIGNAL ;
    SHAPE ABUTMENT ;
    PORT
      LAYER M4 ;
      RECT 0.000 34.128 0.024 34.152 ;
    END
  END wd_in_A[57]
  PIN wd_in_B[57]
    DIRECTION INPUT ;
    USE SIGNAL ;
    SHAPE ABUTMENT ;
    PORT
      LAYER M4 ;
      RECT 103.336 34.128 103.360 34.152 ;
    END
  END wd_in_B[57]
  PIN wd_in_A[58]
    DIRECTION INPUT ;
    USE SIGNAL ;
    SHAPE ABUTMENT ;
    PORT
      LAYER M4 ;
      RECT 0.000 34.224 0.024 34.248 ;
    END
  END wd_in_A[58]
  PIN wd_in_B[58]
    DIRECTION INPUT ;
    USE SIGNAL ;
    SHAPE ABUTMENT ;
    PORT
      LAYER M4 ;
      RECT 103.336 34.224 103.360 34.248 ;
    END
  END wd_in_B[58]
  PIN wd_in_A[59]
    DIRECTION INPUT ;
    USE SIGNAL ;
    SHAPE ABUTMENT ;
    PORT
      LAYER M4 ;
      RECT 0.000 34.320 0.024 34.344 ;
    END
  END wd_in_A[59]
  PIN wd_in_B[59]
    DIRECTION INPUT ;
    USE SIGNAL ;
    SHAPE ABUTMENT ;
    PORT
      LAYER M4 ;
      RECT 103.336 34.320 103.360 34.344 ;
    END
  END wd_in_B[59]
  PIN wd_in_A[60]
    DIRECTION INPUT ;
    USE SIGNAL ;
    SHAPE ABUTMENT ;
    PORT
      LAYER M4 ;
      RECT 0.000 34.416 0.024 34.440 ;
    END
  END wd_in_A[60]
  PIN wd_in_B[60]
    DIRECTION INPUT ;
    USE SIGNAL ;
    SHAPE ABUTMENT ;
    PORT
      LAYER M4 ;
      RECT 103.336 34.416 103.360 34.440 ;
    END
  END wd_in_B[60]
  PIN wd_in_A[61]
    DIRECTION INPUT ;
    USE SIGNAL ;
    SHAPE ABUTMENT ;
    PORT
      LAYER M4 ;
      RECT 0.000 34.512 0.024 34.536 ;
    END
  END wd_in_A[61]
  PIN wd_in_B[61]
    DIRECTION INPUT ;
    USE SIGNAL ;
    SHAPE ABUTMENT ;
    PORT
      LAYER M4 ;
      RECT 103.336 34.512 103.360 34.536 ;
    END
  END wd_in_B[61]
  PIN wd_in_A[62]
    DIRECTION INPUT ;
    USE SIGNAL ;
    SHAPE ABUTMENT ;
    PORT
      LAYER M4 ;
      RECT 0.000 34.608 0.024 34.632 ;
    END
  END wd_in_A[62]
  PIN wd_in_B[62]
    DIRECTION INPUT ;
    USE SIGNAL ;
    SHAPE ABUTMENT ;
    PORT
      LAYER M4 ;
      RECT 103.336 34.608 103.360 34.632 ;
    END
  END wd_in_B[62]
  PIN wd_in_A[63]
    DIRECTION INPUT ;
    USE SIGNAL ;
    SHAPE ABUTMENT ;
    PORT
      LAYER M4 ;
      RECT 0.000 34.704 0.024 34.728 ;
    END
  END wd_in_A[63]
  PIN wd_in_B[63]
    DIRECTION INPUT ;
    USE SIGNAL ;
    SHAPE ABUTMENT ;
    PORT
      LAYER M4 ;
      RECT 103.336 34.704 103.360 34.728 ;
    END
  END wd_in_B[63]
  PIN wd_in_A[64]
    DIRECTION INPUT ;
    USE SIGNAL ;
    SHAPE ABUTMENT ;
    PORT
      LAYER M4 ;
      RECT 0.000 34.800 0.024 34.824 ;
    END
  END wd_in_A[64]
  PIN wd_in_B[64]
    DIRECTION INPUT ;
    USE SIGNAL ;
    SHAPE ABUTMENT ;
    PORT
      LAYER M4 ;
      RECT 103.336 34.800 103.360 34.824 ;
    END
  END wd_in_B[64]
  PIN wd_in_A[65]
    DIRECTION INPUT ;
    USE SIGNAL ;
    SHAPE ABUTMENT ;
    PORT
      LAYER M4 ;
      RECT 0.000 34.896 0.024 34.920 ;
    END
  END wd_in_A[65]
  PIN wd_in_B[65]
    DIRECTION INPUT ;
    USE SIGNAL ;
    SHAPE ABUTMENT ;
    PORT
      LAYER M4 ;
      RECT 103.336 34.896 103.360 34.920 ;
    END
  END wd_in_B[65]
  PIN wd_in_A[66]
    DIRECTION INPUT ;
    USE SIGNAL ;
    SHAPE ABUTMENT ;
    PORT
      LAYER M4 ;
      RECT 0.000 34.992 0.024 35.016 ;
    END
  END wd_in_A[66]
  PIN wd_in_B[66]
    DIRECTION INPUT ;
    USE SIGNAL ;
    SHAPE ABUTMENT ;
    PORT
      LAYER M4 ;
      RECT 103.336 34.992 103.360 35.016 ;
    END
  END wd_in_B[66]
  PIN wd_in_A[67]
    DIRECTION INPUT ;
    USE SIGNAL ;
    SHAPE ABUTMENT ;
    PORT
      LAYER M4 ;
      RECT 0.000 35.088 0.024 35.112 ;
    END
  END wd_in_A[67]
  PIN wd_in_B[67]
    DIRECTION INPUT ;
    USE SIGNAL ;
    SHAPE ABUTMENT ;
    PORT
      LAYER M4 ;
      RECT 103.336 35.088 103.360 35.112 ;
    END
  END wd_in_B[67]
  PIN wd_in_A[68]
    DIRECTION INPUT ;
    USE SIGNAL ;
    SHAPE ABUTMENT ;
    PORT
      LAYER M4 ;
      RECT 0.000 35.184 0.024 35.208 ;
    END
  END wd_in_A[68]
  PIN wd_in_B[68]
    DIRECTION INPUT ;
    USE SIGNAL ;
    SHAPE ABUTMENT ;
    PORT
      LAYER M4 ;
      RECT 103.336 35.184 103.360 35.208 ;
    END
  END wd_in_B[68]
  PIN wd_in_A[69]
    DIRECTION INPUT ;
    USE SIGNAL ;
    SHAPE ABUTMENT ;
    PORT
      LAYER M4 ;
      RECT 0.000 35.280 0.024 35.304 ;
    END
  END wd_in_A[69]
  PIN wd_in_B[69]
    DIRECTION INPUT ;
    USE SIGNAL ;
    SHAPE ABUTMENT ;
    PORT
      LAYER M4 ;
      RECT 103.336 35.280 103.360 35.304 ;
    END
  END wd_in_B[69]
  PIN wd_in_A[70]
    DIRECTION INPUT ;
    USE SIGNAL ;
    SHAPE ABUTMENT ;
    PORT
      LAYER M4 ;
      RECT 0.000 35.376 0.024 35.400 ;
    END
  END wd_in_A[70]
  PIN wd_in_B[70]
    DIRECTION INPUT ;
    USE SIGNAL ;
    SHAPE ABUTMENT ;
    PORT
      LAYER M4 ;
      RECT 103.336 35.376 103.360 35.400 ;
    END
  END wd_in_B[70]
  PIN wd_in_A[71]
    DIRECTION INPUT ;
    USE SIGNAL ;
    SHAPE ABUTMENT ;
    PORT
      LAYER M4 ;
      RECT 0.000 35.472 0.024 35.496 ;
    END
  END wd_in_A[71]
  PIN wd_in_B[71]
    DIRECTION INPUT ;
    USE SIGNAL ;
    SHAPE ABUTMENT ;
    PORT
      LAYER M4 ;
      RECT 103.336 35.472 103.360 35.496 ;
    END
  END wd_in_B[71]
  PIN wd_in_A[72]
    DIRECTION INPUT ;
    USE SIGNAL ;
    SHAPE ABUTMENT ;
    PORT
      LAYER M4 ;
      RECT 0.000 35.568 0.024 35.592 ;
    END
  END wd_in_A[72]
  PIN wd_in_B[72]
    DIRECTION INPUT ;
    USE SIGNAL ;
    SHAPE ABUTMENT ;
    PORT
      LAYER M4 ;
      RECT 103.336 35.568 103.360 35.592 ;
    END
  END wd_in_B[72]
  PIN wd_in_A[73]
    DIRECTION INPUT ;
    USE SIGNAL ;
    SHAPE ABUTMENT ;
    PORT
      LAYER M4 ;
      RECT 0.000 35.664 0.024 35.688 ;
    END
  END wd_in_A[73]
  PIN wd_in_B[73]
    DIRECTION INPUT ;
    USE SIGNAL ;
    SHAPE ABUTMENT ;
    PORT
      LAYER M4 ;
      RECT 103.336 35.664 103.360 35.688 ;
    END
  END wd_in_B[73]
  PIN wd_in_A[74]
    DIRECTION INPUT ;
    USE SIGNAL ;
    SHAPE ABUTMENT ;
    PORT
      LAYER M4 ;
      RECT 0.000 35.760 0.024 35.784 ;
    END
  END wd_in_A[74]
  PIN wd_in_B[74]
    DIRECTION INPUT ;
    USE SIGNAL ;
    SHAPE ABUTMENT ;
    PORT
      LAYER M4 ;
      RECT 103.336 35.760 103.360 35.784 ;
    END
  END wd_in_B[74]
  PIN wd_in_A[75]
    DIRECTION INPUT ;
    USE SIGNAL ;
    SHAPE ABUTMENT ;
    PORT
      LAYER M4 ;
      RECT 0.000 35.856 0.024 35.880 ;
    END
  END wd_in_A[75]
  PIN wd_in_B[75]
    DIRECTION INPUT ;
    USE SIGNAL ;
    SHAPE ABUTMENT ;
    PORT
      LAYER M4 ;
      RECT 103.336 35.856 103.360 35.880 ;
    END
  END wd_in_B[75]
  PIN wd_in_A[76]
    DIRECTION INPUT ;
    USE SIGNAL ;
    SHAPE ABUTMENT ;
    PORT
      LAYER M4 ;
      RECT 0.000 35.952 0.024 35.976 ;
    END
  END wd_in_A[76]
  PIN wd_in_B[76]
    DIRECTION INPUT ;
    USE SIGNAL ;
    SHAPE ABUTMENT ;
    PORT
      LAYER M4 ;
      RECT 103.336 35.952 103.360 35.976 ;
    END
  END wd_in_B[76]
  PIN wd_in_A[77]
    DIRECTION INPUT ;
    USE SIGNAL ;
    SHAPE ABUTMENT ;
    PORT
      LAYER M4 ;
      RECT 0.000 36.048 0.024 36.072 ;
    END
  END wd_in_A[77]
  PIN wd_in_B[77]
    DIRECTION INPUT ;
    USE SIGNAL ;
    SHAPE ABUTMENT ;
    PORT
      LAYER M4 ;
      RECT 103.336 36.048 103.360 36.072 ;
    END
  END wd_in_B[77]
  PIN wd_in_A[78]
    DIRECTION INPUT ;
    USE SIGNAL ;
    SHAPE ABUTMENT ;
    PORT
      LAYER M4 ;
      RECT 0.000 36.144 0.024 36.168 ;
    END
  END wd_in_A[78]
  PIN wd_in_B[78]
    DIRECTION INPUT ;
    USE SIGNAL ;
    SHAPE ABUTMENT ;
    PORT
      LAYER M4 ;
      RECT 103.336 36.144 103.360 36.168 ;
    END
  END wd_in_B[78]
  PIN wd_in_A[79]
    DIRECTION INPUT ;
    USE SIGNAL ;
    SHAPE ABUTMENT ;
    PORT
      LAYER M4 ;
      RECT 0.000 36.240 0.024 36.264 ;
    END
  END wd_in_A[79]
  PIN wd_in_B[79]
    DIRECTION INPUT ;
    USE SIGNAL ;
    SHAPE ABUTMENT ;
    PORT
      LAYER M4 ;
      RECT 103.336 36.240 103.360 36.264 ;
    END
  END wd_in_B[79]
  PIN wd_in_A[80]
    DIRECTION INPUT ;
    USE SIGNAL ;
    SHAPE ABUTMENT ;
    PORT
      LAYER M4 ;
      RECT 0.000 36.336 0.024 36.360 ;
    END
  END wd_in_A[80]
  PIN wd_in_B[80]
    DIRECTION INPUT ;
    USE SIGNAL ;
    SHAPE ABUTMENT ;
    PORT
      LAYER M4 ;
      RECT 103.336 36.336 103.360 36.360 ;
    END
  END wd_in_B[80]
  PIN wd_in_A[81]
    DIRECTION INPUT ;
    USE SIGNAL ;
    SHAPE ABUTMENT ;
    PORT
      LAYER M4 ;
      RECT 0.000 36.432 0.024 36.456 ;
    END
  END wd_in_A[81]
  PIN wd_in_B[81]
    DIRECTION INPUT ;
    USE SIGNAL ;
    SHAPE ABUTMENT ;
    PORT
      LAYER M4 ;
      RECT 103.336 36.432 103.360 36.456 ;
    END
  END wd_in_B[81]
  PIN wd_in_A[82]
    DIRECTION INPUT ;
    USE SIGNAL ;
    SHAPE ABUTMENT ;
    PORT
      LAYER M4 ;
      RECT 0.000 36.528 0.024 36.552 ;
    END
  END wd_in_A[82]
  PIN wd_in_B[82]
    DIRECTION INPUT ;
    USE SIGNAL ;
    SHAPE ABUTMENT ;
    PORT
      LAYER M4 ;
      RECT 103.336 36.528 103.360 36.552 ;
    END
  END wd_in_B[82]
  PIN wd_in_A[83]
    DIRECTION INPUT ;
    USE SIGNAL ;
    SHAPE ABUTMENT ;
    PORT
      LAYER M4 ;
      RECT 0.000 36.624 0.024 36.648 ;
    END
  END wd_in_A[83]
  PIN wd_in_B[83]
    DIRECTION INPUT ;
    USE SIGNAL ;
    SHAPE ABUTMENT ;
    PORT
      LAYER M4 ;
      RECT 103.336 36.624 103.360 36.648 ;
    END
  END wd_in_B[83]
  PIN wd_in_A[84]
    DIRECTION INPUT ;
    USE SIGNAL ;
    SHAPE ABUTMENT ;
    PORT
      LAYER M4 ;
      RECT 0.000 36.720 0.024 36.744 ;
    END
  END wd_in_A[84]
  PIN wd_in_B[84]
    DIRECTION INPUT ;
    USE SIGNAL ;
    SHAPE ABUTMENT ;
    PORT
      LAYER M4 ;
      RECT 103.336 36.720 103.360 36.744 ;
    END
  END wd_in_B[84]
  PIN wd_in_A[85]
    DIRECTION INPUT ;
    USE SIGNAL ;
    SHAPE ABUTMENT ;
    PORT
      LAYER M4 ;
      RECT 0.000 36.816 0.024 36.840 ;
    END
  END wd_in_A[85]
  PIN wd_in_B[85]
    DIRECTION INPUT ;
    USE SIGNAL ;
    SHAPE ABUTMENT ;
    PORT
      LAYER M4 ;
      RECT 103.336 36.816 103.360 36.840 ;
    END
  END wd_in_B[85]
  PIN wd_in_A[86]
    DIRECTION INPUT ;
    USE SIGNAL ;
    SHAPE ABUTMENT ;
    PORT
      LAYER M4 ;
      RECT 0.000 36.912 0.024 36.936 ;
    END
  END wd_in_A[86]
  PIN wd_in_B[86]
    DIRECTION INPUT ;
    USE SIGNAL ;
    SHAPE ABUTMENT ;
    PORT
      LAYER M4 ;
      RECT 103.336 36.912 103.360 36.936 ;
    END
  END wd_in_B[86]
  PIN wd_in_A[87]
    DIRECTION INPUT ;
    USE SIGNAL ;
    SHAPE ABUTMENT ;
    PORT
      LAYER M4 ;
      RECT 0.000 37.008 0.024 37.032 ;
    END
  END wd_in_A[87]
  PIN wd_in_B[87]
    DIRECTION INPUT ;
    USE SIGNAL ;
    SHAPE ABUTMENT ;
    PORT
      LAYER M4 ;
      RECT 103.336 37.008 103.360 37.032 ;
    END
  END wd_in_B[87]
  PIN wd_in_A[88]
    DIRECTION INPUT ;
    USE SIGNAL ;
    SHAPE ABUTMENT ;
    PORT
      LAYER M4 ;
      RECT 0.000 37.104 0.024 37.128 ;
    END
  END wd_in_A[88]
  PIN wd_in_B[88]
    DIRECTION INPUT ;
    USE SIGNAL ;
    SHAPE ABUTMENT ;
    PORT
      LAYER M4 ;
      RECT 103.336 37.104 103.360 37.128 ;
    END
  END wd_in_B[88]
  PIN wd_in_A[89]
    DIRECTION INPUT ;
    USE SIGNAL ;
    SHAPE ABUTMENT ;
    PORT
      LAYER M4 ;
      RECT 0.000 37.200 0.024 37.224 ;
    END
  END wd_in_A[89]
  PIN wd_in_B[89]
    DIRECTION INPUT ;
    USE SIGNAL ;
    SHAPE ABUTMENT ;
    PORT
      LAYER M4 ;
      RECT 103.336 37.200 103.360 37.224 ;
    END
  END wd_in_B[89]
  PIN wd_in_A[90]
    DIRECTION INPUT ;
    USE SIGNAL ;
    SHAPE ABUTMENT ;
    PORT
      LAYER M4 ;
      RECT 0.000 37.296 0.024 37.320 ;
    END
  END wd_in_A[90]
  PIN wd_in_B[90]
    DIRECTION INPUT ;
    USE SIGNAL ;
    SHAPE ABUTMENT ;
    PORT
      LAYER M4 ;
      RECT 103.336 37.296 103.360 37.320 ;
    END
  END wd_in_B[90]
  PIN wd_in_A[91]
    DIRECTION INPUT ;
    USE SIGNAL ;
    SHAPE ABUTMENT ;
    PORT
      LAYER M4 ;
      RECT 0.000 37.392 0.024 37.416 ;
    END
  END wd_in_A[91]
  PIN wd_in_B[91]
    DIRECTION INPUT ;
    USE SIGNAL ;
    SHAPE ABUTMENT ;
    PORT
      LAYER M4 ;
      RECT 103.336 37.392 103.360 37.416 ;
    END
  END wd_in_B[91]
  PIN wd_in_A[92]
    DIRECTION INPUT ;
    USE SIGNAL ;
    SHAPE ABUTMENT ;
    PORT
      LAYER M4 ;
      RECT 0.000 37.488 0.024 37.512 ;
    END
  END wd_in_A[92]
  PIN wd_in_B[92]
    DIRECTION INPUT ;
    USE SIGNAL ;
    SHAPE ABUTMENT ;
    PORT
      LAYER M4 ;
      RECT 103.336 37.488 103.360 37.512 ;
    END
  END wd_in_B[92]
  PIN wd_in_A[93]
    DIRECTION INPUT ;
    USE SIGNAL ;
    SHAPE ABUTMENT ;
    PORT
      LAYER M4 ;
      RECT 0.000 37.584 0.024 37.608 ;
    END
  END wd_in_A[93]
  PIN wd_in_B[93]
    DIRECTION INPUT ;
    USE SIGNAL ;
    SHAPE ABUTMENT ;
    PORT
      LAYER M4 ;
      RECT 103.336 37.584 103.360 37.608 ;
    END
  END wd_in_B[93]
  PIN wd_in_A[94]
    DIRECTION INPUT ;
    USE SIGNAL ;
    SHAPE ABUTMENT ;
    PORT
      LAYER M4 ;
      RECT 0.000 37.680 0.024 37.704 ;
    END
  END wd_in_A[94]
  PIN wd_in_B[94]
    DIRECTION INPUT ;
    USE SIGNAL ;
    SHAPE ABUTMENT ;
    PORT
      LAYER M4 ;
      RECT 103.336 37.680 103.360 37.704 ;
    END
  END wd_in_B[94]
  PIN wd_in_A[95]
    DIRECTION INPUT ;
    USE SIGNAL ;
    SHAPE ABUTMENT ;
    PORT
      LAYER M4 ;
      RECT 0.000 37.776 0.024 37.800 ;
    END
  END wd_in_A[95]
  PIN wd_in_B[95]
    DIRECTION INPUT ;
    USE SIGNAL ;
    SHAPE ABUTMENT ;
    PORT
      LAYER M4 ;
      RECT 103.336 37.776 103.360 37.800 ;
    END
  END wd_in_B[95]
  PIN wd_in_A[96]
    DIRECTION INPUT ;
    USE SIGNAL ;
    SHAPE ABUTMENT ;
    PORT
      LAYER M4 ;
      RECT 0.000 37.872 0.024 37.896 ;
    END
  END wd_in_A[96]
  PIN wd_in_B[96]
    DIRECTION INPUT ;
    USE SIGNAL ;
    SHAPE ABUTMENT ;
    PORT
      LAYER M4 ;
      RECT 103.336 37.872 103.360 37.896 ;
    END
  END wd_in_B[96]
  PIN wd_in_A[97]
    DIRECTION INPUT ;
    USE SIGNAL ;
    SHAPE ABUTMENT ;
    PORT
      LAYER M4 ;
      RECT 0.000 37.968 0.024 37.992 ;
    END
  END wd_in_A[97]
  PIN wd_in_B[97]
    DIRECTION INPUT ;
    USE SIGNAL ;
    SHAPE ABUTMENT ;
    PORT
      LAYER M4 ;
      RECT 103.336 37.968 103.360 37.992 ;
    END
  END wd_in_B[97]
  PIN wd_in_A[98]
    DIRECTION INPUT ;
    USE SIGNAL ;
    SHAPE ABUTMENT ;
    PORT
      LAYER M4 ;
      RECT 0.000 38.064 0.024 38.088 ;
    END
  END wd_in_A[98]
  PIN wd_in_B[98]
    DIRECTION INPUT ;
    USE SIGNAL ;
    SHAPE ABUTMENT ;
    PORT
      LAYER M4 ;
      RECT 103.336 38.064 103.360 38.088 ;
    END
  END wd_in_B[98]
  PIN wd_in_A[99]
    DIRECTION INPUT ;
    USE SIGNAL ;
    SHAPE ABUTMENT ;
    PORT
      LAYER M4 ;
      RECT 0.000 38.160 0.024 38.184 ;
    END
  END wd_in_A[99]
  PIN wd_in_B[99]
    DIRECTION INPUT ;
    USE SIGNAL ;
    SHAPE ABUTMENT ;
    PORT
      LAYER M4 ;
      RECT 103.336 38.160 103.360 38.184 ;
    END
  END wd_in_B[99]
  PIN wd_in_A[100]
    DIRECTION INPUT ;
    USE SIGNAL ;
    SHAPE ABUTMENT ;
    PORT
      LAYER M4 ;
      RECT 0.000 38.256 0.024 38.280 ;
    END
  END wd_in_A[100]
  PIN wd_in_B[100]
    DIRECTION INPUT ;
    USE SIGNAL ;
    SHAPE ABUTMENT ;
    PORT
      LAYER M4 ;
      RECT 103.336 38.256 103.360 38.280 ;
    END
  END wd_in_B[100]
  PIN wd_in_A[101]
    DIRECTION INPUT ;
    USE SIGNAL ;
    SHAPE ABUTMENT ;
    PORT
      LAYER M4 ;
      RECT 0.000 38.352 0.024 38.376 ;
    END
  END wd_in_A[101]
  PIN wd_in_B[101]
    DIRECTION INPUT ;
    USE SIGNAL ;
    SHAPE ABUTMENT ;
    PORT
      LAYER M4 ;
      RECT 103.336 38.352 103.360 38.376 ;
    END
  END wd_in_B[101]
  PIN wd_in_A[102]
    DIRECTION INPUT ;
    USE SIGNAL ;
    SHAPE ABUTMENT ;
    PORT
      LAYER M4 ;
      RECT 0.000 38.448 0.024 38.472 ;
    END
  END wd_in_A[102]
  PIN wd_in_B[102]
    DIRECTION INPUT ;
    USE SIGNAL ;
    SHAPE ABUTMENT ;
    PORT
      LAYER M4 ;
      RECT 103.336 38.448 103.360 38.472 ;
    END
  END wd_in_B[102]
  PIN wd_in_A[103]
    DIRECTION INPUT ;
    USE SIGNAL ;
    SHAPE ABUTMENT ;
    PORT
      LAYER M4 ;
      RECT 0.000 38.544 0.024 38.568 ;
    END
  END wd_in_A[103]
  PIN wd_in_B[103]
    DIRECTION INPUT ;
    USE SIGNAL ;
    SHAPE ABUTMENT ;
    PORT
      LAYER M4 ;
      RECT 103.336 38.544 103.360 38.568 ;
    END
  END wd_in_B[103]
  PIN wd_in_A[104]
    DIRECTION INPUT ;
    USE SIGNAL ;
    SHAPE ABUTMENT ;
    PORT
      LAYER M4 ;
      RECT 0.000 38.640 0.024 38.664 ;
    END
  END wd_in_A[104]
  PIN wd_in_B[104]
    DIRECTION INPUT ;
    USE SIGNAL ;
    SHAPE ABUTMENT ;
    PORT
      LAYER M4 ;
      RECT 103.336 38.640 103.360 38.664 ;
    END
  END wd_in_B[104]
  PIN wd_in_A[105]
    DIRECTION INPUT ;
    USE SIGNAL ;
    SHAPE ABUTMENT ;
    PORT
      LAYER M4 ;
      RECT 0.000 38.736 0.024 38.760 ;
    END
  END wd_in_A[105]
  PIN wd_in_B[105]
    DIRECTION INPUT ;
    USE SIGNAL ;
    SHAPE ABUTMENT ;
    PORT
      LAYER M4 ;
      RECT 103.336 38.736 103.360 38.760 ;
    END
  END wd_in_B[105]
  PIN wd_in_A[106]
    DIRECTION INPUT ;
    USE SIGNAL ;
    SHAPE ABUTMENT ;
    PORT
      LAYER M4 ;
      RECT 0.000 38.832 0.024 38.856 ;
    END
  END wd_in_A[106]
  PIN wd_in_B[106]
    DIRECTION INPUT ;
    USE SIGNAL ;
    SHAPE ABUTMENT ;
    PORT
      LAYER M4 ;
      RECT 103.336 38.832 103.360 38.856 ;
    END
  END wd_in_B[106]
  PIN wd_in_A[107]
    DIRECTION INPUT ;
    USE SIGNAL ;
    SHAPE ABUTMENT ;
    PORT
      LAYER M4 ;
      RECT 0.000 38.928 0.024 38.952 ;
    END
  END wd_in_A[107]
  PIN wd_in_B[107]
    DIRECTION INPUT ;
    USE SIGNAL ;
    SHAPE ABUTMENT ;
    PORT
      LAYER M4 ;
      RECT 103.336 38.928 103.360 38.952 ;
    END
  END wd_in_B[107]
  PIN wd_in_A[108]
    DIRECTION INPUT ;
    USE SIGNAL ;
    SHAPE ABUTMENT ;
    PORT
      LAYER M4 ;
      RECT 0.000 39.024 0.024 39.048 ;
    END
  END wd_in_A[108]
  PIN wd_in_B[108]
    DIRECTION INPUT ;
    USE SIGNAL ;
    SHAPE ABUTMENT ;
    PORT
      LAYER M4 ;
      RECT 103.336 39.024 103.360 39.048 ;
    END
  END wd_in_B[108]
  PIN wd_in_A[109]
    DIRECTION INPUT ;
    USE SIGNAL ;
    SHAPE ABUTMENT ;
    PORT
      LAYER M4 ;
      RECT 0.000 39.120 0.024 39.144 ;
    END
  END wd_in_A[109]
  PIN wd_in_B[109]
    DIRECTION INPUT ;
    USE SIGNAL ;
    SHAPE ABUTMENT ;
    PORT
      LAYER M4 ;
      RECT 103.336 39.120 103.360 39.144 ;
    END
  END wd_in_B[109]
  PIN wd_in_A[110]
    DIRECTION INPUT ;
    USE SIGNAL ;
    SHAPE ABUTMENT ;
    PORT
      LAYER M4 ;
      RECT 0.000 39.216 0.024 39.240 ;
    END
  END wd_in_A[110]
  PIN wd_in_B[110]
    DIRECTION INPUT ;
    USE SIGNAL ;
    SHAPE ABUTMENT ;
    PORT
      LAYER M4 ;
      RECT 103.336 39.216 103.360 39.240 ;
    END
  END wd_in_B[110]
  PIN wd_in_A[111]
    DIRECTION INPUT ;
    USE SIGNAL ;
    SHAPE ABUTMENT ;
    PORT
      LAYER M4 ;
      RECT 0.000 39.312 0.024 39.336 ;
    END
  END wd_in_A[111]
  PIN wd_in_B[111]
    DIRECTION INPUT ;
    USE SIGNAL ;
    SHAPE ABUTMENT ;
    PORT
      LAYER M4 ;
      RECT 103.336 39.312 103.360 39.336 ;
    END
  END wd_in_B[111]
  PIN wd_in_A[112]
    DIRECTION INPUT ;
    USE SIGNAL ;
    SHAPE ABUTMENT ;
    PORT
      LAYER M4 ;
      RECT 0.000 39.408 0.024 39.432 ;
    END
  END wd_in_A[112]
  PIN wd_in_B[112]
    DIRECTION INPUT ;
    USE SIGNAL ;
    SHAPE ABUTMENT ;
    PORT
      LAYER M4 ;
      RECT 103.336 39.408 103.360 39.432 ;
    END
  END wd_in_B[112]
  PIN wd_in_A[113]
    DIRECTION INPUT ;
    USE SIGNAL ;
    SHAPE ABUTMENT ;
    PORT
      LAYER M4 ;
      RECT 0.000 39.504 0.024 39.528 ;
    END
  END wd_in_A[113]
  PIN wd_in_B[113]
    DIRECTION INPUT ;
    USE SIGNAL ;
    SHAPE ABUTMENT ;
    PORT
      LAYER M4 ;
      RECT 103.336 39.504 103.360 39.528 ;
    END
  END wd_in_B[113]
  PIN wd_in_A[114]
    DIRECTION INPUT ;
    USE SIGNAL ;
    SHAPE ABUTMENT ;
    PORT
      LAYER M4 ;
      RECT 0.000 39.600 0.024 39.624 ;
    END
  END wd_in_A[114]
  PIN wd_in_B[114]
    DIRECTION INPUT ;
    USE SIGNAL ;
    SHAPE ABUTMENT ;
    PORT
      LAYER M4 ;
      RECT 103.336 39.600 103.360 39.624 ;
    END
  END wd_in_B[114]
  PIN wd_in_A[115]
    DIRECTION INPUT ;
    USE SIGNAL ;
    SHAPE ABUTMENT ;
    PORT
      LAYER M4 ;
      RECT 0.000 39.696 0.024 39.720 ;
    END
  END wd_in_A[115]
  PIN wd_in_B[115]
    DIRECTION INPUT ;
    USE SIGNAL ;
    SHAPE ABUTMENT ;
    PORT
      LAYER M4 ;
      RECT 103.336 39.696 103.360 39.720 ;
    END
  END wd_in_B[115]
  PIN wd_in_A[116]
    DIRECTION INPUT ;
    USE SIGNAL ;
    SHAPE ABUTMENT ;
    PORT
      LAYER M4 ;
      RECT 0.000 39.792 0.024 39.816 ;
    END
  END wd_in_A[116]
  PIN wd_in_B[116]
    DIRECTION INPUT ;
    USE SIGNAL ;
    SHAPE ABUTMENT ;
    PORT
      LAYER M4 ;
      RECT 103.336 39.792 103.360 39.816 ;
    END
  END wd_in_B[116]
  PIN wd_in_A[117]
    DIRECTION INPUT ;
    USE SIGNAL ;
    SHAPE ABUTMENT ;
    PORT
      LAYER M4 ;
      RECT 0.000 39.888 0.024 39.912 ;
    END
  END wd_in_A[117]
  PIN wd_in_B[117]
    DIRECTION INPUT ;
    USE SIGNAL ;
    SHAPE ABUTMENT ;
    PORT
      LAYER M4 ;
      RECT 103.336 39.888 103.360 39.912 ;
    END
  END wd_in_B[117]
  PIN wd_in_A[118]
    DIRECTION INPUT ;
    USE SIGNAL ;
    SHAPE ABUTMENT ;
    PORT
      LAYER M4 ;
      RECT 0.000 39.984 0.024 40.008 ;
    END
  END wd_in_A[118]
  PIN wd_in_B[118]
    DIRECTION INPUT ;
    USE SIGNAL ;
    SHAPE ABUTMENT ;
    PORT
      LAYER M4 ;
      RECT 103.336 39.984 103.360 40.008 ;
    END
  END wd_in_B[118]
  PIN wd_in_A[119]
    DIRECTION INPUT ;
    USE SIGNAL ;
    SHAPE ABUTMENT ;
    PORT
      LAYER M4 ;
      RECT 0.000 40.080 0.024 40.104 ;
    END
  END wd_in_A[119]
  PIN wd_in_B[119]
    DIRECTION INPUT ;
    USE SIGNAL ;
    SHAPE ABUTMENT ;
    PORT
      LAYER M4 ;
      RECT 103.336 40.080 103.360 40.104 ;
    END
  END wd_in_B[119]
  PIN wd_in_A[120]
    DIRECTION INPUT ;
    USE SIGNAL ;
    SHAPE ABUTMENT ;
    PORT
      LAYER M4 ;
      RECT 0.000 40.176 0.024 40.200 ;
    END
  END wd_in_A[120]
  PIN wd_in_B[120]
    DIRECTION INPUT ;
    USE SIGNAL ;
    SHAPE ABUTMENT ;
    PORT
      LAYER M4 ;
      RECT 103.336 40.176 103.360 40.200 ;
    END
  END wd_in_B[120]
  PIN wd_in_A[121]
    DIRECTION INPUT ;
    USE SIGNAL ;
    SHAPE ABUTMENT ;
    PORT
      LAYER M4 ;
      RECT 0.000 40.272 0.024 40.296 ;
    END
  END wd_in_A[121]
  PIN wd_in_B[121]
    DIRECTION INPUT ;
    USE SIGNAL ;
    SHAPE ABUTMENT ;
    PORT
      LAYER M4 ;
      RECT 103.336 40.272 103.360 40.296 ;
    END
  END wd_in_B[121]
  PIN wd_in_A[122]
    DIRECTION INPUT ;
    USE SIGNAL ;
    SHAPE ABUTMENT ;
    PORT
      LAYER M4 ;
      RECT 0.000 40.368 0.024 40.392 ;
    END
  END wd_in_A[122]
  PIN wd_in_B[122]
    DIRECTION INPUT ;
    USE SIGNAL ;
    SHAPE ABUTMENT ;
    PORT
      LAYER M4 ;
      RECT 103.336 40.368 103.360 40.392 ;
    END
  END wd_in_B[122]
  PIN wd_in_A[123]
    DIRECTION INPUT ;
    USE SIGNAL ;
    SHAPE ABUTMENT ;
    PORT
      LAYER M4 ;
      RECT 0.000 40.464 0.024 40.488 ;
    END
  END wd_in_A[123]
  PIN wd_in_B[123]
    DIRECTION INPUT ;
    USE SIGNAL ;
    SHAPE ABUTMENT ;
    PORT
      LAYER M4 ;
      RECT 103.336 40.464 103.360 40.488 ;
    END
  END wd_in_B[123]
  PIN wd_in_A[124]
    DIRECTION INPUT ;
    USE SIGNAL ;
    SHAPE ABUTMENT ;
    PORT
      LAYER M4 ;
      RECT 0.000 40.560 0.024 40.584 ;
    END
  END wd_in_A[124]
  PIN wd_in_B[124]
    DIRECTION INPUT ;
    USE SIGNAL ;
    SHAPE ABUTMENT ;
    PORT
      LAYER M4 ;
      RECT 103.336 40.560 103.360 40.584 ;
    END
  END wd_in_B[124]
  PIN wd_in_A[125]
    DIRECTION INPUT ;
    USE SIGNAL ;
    SHAPE ABUTMENT ;
    PORT
      LAYER M4 ;
      RECT 0.000 40.656 0.024 40.680 ;
    END
  END wd_in_A[125]
  PIN wd_in_B[125]
    DIRECTION INPUT ;
    USE SIGNAL ;
    SHAPE ABUTMENT ;
    PORT
      LAYER M4 ;
      RECT 103.336 40.656 103.360 40.680 ;
    END
  END wd_in_B[125]
  PIN wd_in_A[126]
    DIRECTION INPUT ;
    USE SIGNAL ;
    SHAPE ABUTMENT ;
    PORT
      LAYER M4 ;
      RECT 0.000 40.752 0.024 40.776 ;
    END
  END wd_in_A[126]
  PIN wd_in_B[126]
    DIRECTION INPUT ;
    USE SIGNAL ;
    SHAPE ABUTMENT ;
    PORT
      LAYER M4 ;
      RECT 103.336 40.752 103.360 40.776 ;
    END
  END wd_in_B[126]
  PIN wd_in_A[127]
    DIRECTION INPUT ;
    USE SIGNAL ;
    SHAPE ABUTMENT ;
    PORT
      LAYER M4 ;
      RECT 0.000 40.848 0.024 40.872 ;
    END
  END wd_in_A[127]
  PIN wd_in_B[127]
    DIRECTION INPUT ;
    USE SIGNAL ;
    SHAPE ABUTMENT ;
    PORT
      LAYER M4 ;
      RECT 103.336 40.848 103.360 40.872 ;
    END
  END wd_in_B[127]
  PIN addr_in_A[0]
    DIRECTION INPUT ;
    USE SIGNAL ;
    SHAPE ABUTMENT ;
    PORT
      LAYER M4 ;
      RECT 0.000 42.960 0.024 42.984 ;
    END
  END addr_in_A[0]
  PIN addr_in_B[0]
    DIRECTION INPUT ;
    USE SIGNAL ;
    SHAPE ABUTMENT ;
    PORT
      LAYER M4 ;
      RECT 103.336 42.960 103.360 42.984 ;
    END
  END addr_in_B[0]
  PIN addr_in_A[1]
    DIRECTION INPUT ;
    USE SIGNAL ;
    SHAPE ABUTMENT ;
    PORT
      LAYER M4 ;
      RECT 0.000 43.056 0.024 43.080 ;
    END
  END addr_in_A[1]
  PIN addr_in_B[1]
    DIRECTION INPUT ;
    USE SIGNAL ;
    SHAPE ABUTMENT ;
    PORT
      LAYER M4 ;
      RECT 103.336 43.056 103.360 43.080 ;
    END
  END addr_in_B[1]
  PIN addr_in_A[2]
    DIRECTION INPUT ;
    USE SIGNAL ;
    SHAPE ABUTMENT ;
    PORT
      LAYER M4 ;
      RECT 0.000 43.152 0.024 43.176 ;
    END
  END addr_in_A[2]
  PIN addr_in_B[2]
    DIRECTION INPUT ;
    USE SIGNAL ;
    SHAPE ABUTMENT ;
    PORT
      LAYER M4 ;
      RECT 103.336 43.152 103.360 43.176 ;
    END
  END addr_in_B[2]
  PIN addr_in_A[3]
    DIRECTION INPUT ;
    USE SIGNAL ;
    SHAPE ABUTMENT ;
    PORT
      LAYER M4 ;
      RECT 0.000 43.248 0.024 43.272 ;
    END
  END addr_in_A[3]
  PIN addr_in_B[3]
    DIRECTION INPUT ;
    USE SIGNAL ;
    SHAPE ABUTMENT ;
    PORT
      LAYER M4 ;
      RECT 103.336 43.248 103.360 43.272 ;
    END
  END addr_in_B[3]
  PIN addr_in_A[4]
    DIRECTION INPUT ;
    USE SIGNAL ;
    SHAPE ABUTMENT ;
    PORT
      LAYER M4 ;
      RECT 0.000 43.344 0.024 43.368 ;
    END
  END addr_in_A[4]
  PIN addr_in_B[4]
    DIRECTION INPUT ;
    USE SIGNAL ;
    SHAPE ABUTMENT ;
    PORT
      LAYER M4 ;
      RECT 103.336 43.344 103.360 43.368 ;
    END
  END addr_in_B[4]
  PIN addr_in_A[5]
    DIRECTION INPUT ;
    USE SIGNAL ;
    SHAPE ABUTMENT ;
    PORT
      LAYER M4 ;
      RECT 0.000 43.440 0.024 43.464 ;
    END
  END addr_in_A[5]
  PIN addr_in_B[5]
    DIRECTION INPUT ;
    USE SIGNAL ;
    SHAPE ABUTMENT ;
    PORT
      LAYER M4 ;
      RECT 103.336 43.440 103.360 43.464 ;
    END
  END addr_in_B[5]
  PIN addr_in_A[6]
    DIRECTION INPUT ;
    USE SIGNAL ;
    SHAPE ABUTMENT ;
    PORT
      LAYER M4 ;
      RECT 0.000 43.536 0.024 43.560 ;
    END
  END addr_in_A[6]
  PIN addr_in_B[6]
    DIRECTION INPUT ;
    USE SIGNAL ;
    SHAPE ABUTMENT ;
    PORT
      LAYER M4 ;
      RECT 103.336 43.536 103.360 43.560 ;
    END
  END addr_in_B[6]
  PIN addr_in_A[7]
    DIRECTION INPUT ;
    USE SIGNAL ;
    SHAPE ABUTMENT ;
    PORT
      LAYER M4 ;
      RECT 0.000 43.632 0.024 43.656 ;
    END
  END addr_in_A[7]
  PIN addr_in_B[7]
    DIRECTION INPUT ;
    USE SIGNAL ;
    SHAPE ABUTMENT ;
    PORT
      LAYER M4 ;
      RECT 103.336 43.632 103.360 43.656 ;
    END
  END addr_in_B[7]
  PIN addr_in_A[8]
    DIRECTION INPUT ;
    USE SIGNAL ;
    SHAPE ABUTMENT ;
    PORT
      LAYER M4 ;
      RECT 0.000 43.728 0.024 43.752 ;
    END
  END addr_in_A[8]
  PIN addr_in_B[8]
    DIRECTION INPUT ;
    USE SIGNAL ;
    SHAPE ABUTMENT ;
    PORT
      LAYER M4 ;
      RECT 103.336 43.728 103.360 43.752 ;
    END
  END addr_in_B[8]
  PIN we_in_A
    DIRECTION INPUT ;
    USE SIGNAL ;
    SHAPE ABUTMENT ;
    PORT
      LAYER M4 ;
      RECT 0.000 45.840 0.024 45.864 ;
    END
  END we_in_A
  PIN we_in_B
    DIRECTION INPUT ;
    USE SIGNAL ;
    SHAPE ABUTMENT ;
    PORT
      LAYER M4 ;
      RECT 103.336 45.840 103.360 45.864 ;
    END
  END we_in_B
  PIN ce_in_A
    DIRECTION INPUT ;
    USE SIGNAL ;
    SHAPE ABUTMENT ;
    PORT
      LAYER M4 ;
      RECT 0.000 45.936 0.024 45.960 ;
    END
  END ce_in_A
  PIN clk_A
    DIRECTION INPUT ;
    USE SIGNAL ;
    SHAPE ABUTMENT ;
    PORT
      LAYER M4 ;
      RECT 0.000 46.032 0.024 46.056 ;
    END
  END clk_A
  PIN ce_in_B
    DIRECTION INPUT ;
    USE SIGNAL ;
    SHAPE ABUTMENT ;
    PORT
      LAYER M4 ;
      RECT 0.000 46.128 0.024 46.152 ;
    END
  END ce_in_B
  PIN clk_B
    DIRECTION INPUT ;
    USE SIGNAL ;
    SHAPE ABUTMENT ;
    PORT
      LAYER M4 ;
      RECT 0.000 46.224 0.024 46.248 ;
    END
  END clk_B
  PIN VSS
    DIRECTION INOUT ;
    USE GROUND ;
    PORT
      LAYER M4 ;
      RECT 0.048 0.000 103.312 0.096 ;
      RECT 0.048 0.768 103.312 0.864 ;
      RECT 0.048 1.536 103.312 1.632 ;
      RECT 0.048 2.304 103.312 2.400 ;
      RECT 0.048 3.072 103.312 3.168 ;
      RECT 0.048 3.840 103.312 3.936 ;
      RECT 0.048 4.608 103.312 4.704 ;
      RECT 0.048 5.376 103.312 5.472 ;
      RECT 0.048 6.144 103.312 6.240 ;
      RECT 0.048 6.912 103.312 7.008 ;
      RECT 0.048 7.680 103.312 7.776 ;
      RECT 0.048 8.448 103.312 8.544 ;
      RECT 0.048 9.216 103.312 9.312 ;
      RECT 0.048 9.984 103.312 10.080 ;
      RECT 0.048 10.752 103.312 10.848 ;
      RECT 0.048 11.520 103.312 11.616 ;
      RECT 0.048 12.288 103.312 12.384 ;
      RECT 0.048 13.056 103.312 13.152 ;
      RECT 0.048 13.824 103.312 13.920 ;
      RECT 0.048 14.592 103.312 14.688 ;
      RECT 0.048 15.360 103.312 15.456 ;
      RECT 0.048 16.128 103.312 16.224 ;
      RECT 0.048 16.896 103.312 16.992 ;
      RECT 0.048 17.664 103.312 17.760 ;
      RECT 0.048 18.432 103.312 18.528 ;
      RECT 0.048 19.200 103.312 19.296 ;
      RECT 0.048 19.968 103.312 20.064 ;
      RECT 0.048 20.736 103.312 20.832 ;
      RECT 0.048 21.504 103.312 21.600 ;
      RECT 0.048 22.272 103.312 22.368 ;
      RECT 0.048 23.040 103.312 23.136 ;
      RECT 0.048 23.808 103.312 23.904 ;
      RECT 0.048 24.576 103.312 24.672 ;
      RECT 0.048 25.344 103.312 25.440 ;
      RECT 0.048 26.112 103.312 26.208 ;
      RECT 0.048 26.880 103.312 26.976 ;
      RECT 0.048 27.648 103.312 27.744 ;
      RECT 0.048 28.416 103.312 28.512 ;
      RECT 0.048 29.184 103.312 29.280 ;
      RECT 0.048 29.952 103.312 30.048 ;
      RECT 0.048 30.720 103.312 30.816 ;
      RECT 0.048 31.488 103.312 31.584 ;
      RECT 0.048 32.256 103.312 32.352 ;
      RECT 0.048 33.024 103.312 33.120 ;
      RECT 0.048 33.792 103.312 33.888 ;
      RECT 0.048 34.560 103.312 34.656 ;
      RECT 0.048 35.328 103.312 35.424 ;
      RECT 0.048 36.096 103.312 36.192 ;
      RECT 0.048 36.864 103.312 36.960 ;
      RECT 0.048 37.632 103.312 37.728 ;
      RECT 0.048 38.400 103.312 38.496 ;
      RECT 0.048 39.168 103.312 39.264 ;
      RECT 0.048 39.936 103.312 40.032 ;
      RECT 0.048 40.704 103.312 40.800 ;
      RECT 0.048 41.472 103.312 41.568 ;
      RECT 0.048 42.240 103.312 42.336 ;
      RECT 0.048 43.008 103.312 43.104 ;
      RECT 0.048 43.776 103.312 43.872 ;
      RECT 0.048 44.544 103.312 44.640 ;
      RECT 0.048 45.312 103.312 45.408 ;
      RECT 0.048 46.080 103.312 46.176 ;
    END
  END VSS
  PIN VDD
    DIRECTION INOUT ;
    USE POWER ;
    PORT
      LAYER M4 ;
      RECT 0.048 0.384 103.312 0.480 ;
      RECT 0.048 1.152 103.312 1.248 ;
      RECT 0.048 1.920 103.312 2.016 ;
      RECT 0.048 2.688 103.312 2.784 ;
      RECT 0.048 3.456 103.312 3.552 ;
      RECT 0.048 4.224 103.312 4.320 ;
      RECT 0.048 4.992 103.312 5.088 ;
      RECT 0.048 5.760 103.312 5.856 ;
      RECT 0.048 6.528 103.312 6.624 ;
      RECT 0.048 7.296 103.312 7.392 ;
      RECT 0.048 8.064 103.312 8.160 ;
      RECT 0.048 8.832 103.312 8.928 ;
      RECT 0.048 9.600 103.312 9.696 ;
      RECT 0.048 10.368 103.312 10.464 ;
      RECT 0.048 11.136 103.312 11.232 ;
      RECT 0.048 11.904 103.312 12.000 ;
      RECT 0.048 12.672 103.312 12.768 ;
      RECT 0.048 13.440 103.312 13.536 ;
      RECT 0.048 14.208 103.312 14.304 ;
      RECT 0.048 14.976 103.312 15.072 ;
      RECT 0.048 15.744 103.312 15.840 ;
      RECT 0.048 16.512 103.312 16.608 ;
      RECT 0.048 17.280 103.312 17.376 ;
      RECT 0.048 18.048 103.312 18.144 ;
      RECT 0.048 18.816 103.312 18.912 ;
      RECT 0.048 19.584 103.312 19.680 ;
      RECT 0.048 20.352 103.312 20.448 ;
      RECT 0.048 21.120 103.312 21.216 ;
      RECT 0.048 21.888 103.312 21.984 ;
      RECT 0.048 22.656 103.312 22.752 ;
      RECT 0.048 23.424 103.312 23.520 ;
      RECT 0.048 24.192 103.312 24.288 ;
      RECT 0.048 24.960 103.312 25.056 ;
      RECT 0.048 25.728 103.312 25.824 ;
      RECT 0.048 26.496 103.312 26.592 ;
      RECT 0.048 27.264 103.312 27.360 ;
      RECT 0.048 28.032 103.312 28.128 ;
      RECT 0.048 28.800 103.312 28.896 ;
      RECT 0.048 29.568 103.312 29.664 ;
      RECT 0.048 30.336 103.312 30.432 ;
      RECT 0.048 31.104 103.312 31.200 ;
      RECT 0.048 31.872 103.312 31.968 ;
      RECT 0.048 32.640 103.312 32.736 ;
      RECT 0.048 33.408 103.312 33.504 ;
      RECT 0.048 34.176 103.312 34.272 ;
      RECT 0.048 34.944 103.312 35.040 ;
      RECT 0.048 35.712 103.312 35.808 ;
      RECT 0.048 36.480 103.312 36.576 ;
      RECT 0.048 37.248 103.312 37.344 ;
      RECT 0.048 38.016 103.312 38.112 ;
      RECT 0.048 38.784 103.312 38.880 ;
      RECT 0.048 39.552 103.312 39.648 ;
      RECT 0.048 40.320 103.312 40.416 ;
      RECT 0.048 41.088 103.312 41.184 ;
      RECT 0.048 41.856 103.312 41.952 ;
      RECT 0.048 42.624 103.312 42.720 ;
      RECT 0.048 43.392 103.312 43.488 ;
      RECT 0.048 44.160 103.312 44.256 ;
      RECT 0.048 44.928 103.312 45.024 ;
      RECT 0.048 45.696 103.312 45.792 ;
    END
  END VDD
  OBS
    LAYER M1 ;
    RECT 0 0 103.360 46.200 ;
    LAYER M2 ;
    RECT 0 0 103.360 46.200 ;
    LAYER M3 ;
    RECT 0 0 103.360 46.200 ;
    LAYER M4 ;
    RECT 0 0 103.360 46.200 ;
  END
END fakeram7_tdp_512x128

END LIBRARY
